// Mitsubishi GX Works2 project: PLC(原)   PLC: L06

// task 1# (event TRUE, interval 0, priority 31): 
// task 10# (event TRUE, interval 0, priority 31): 
// task 工位6（点胶A面） (event TRUE, interval 0, priority 31): 
// task 工位7（点胶B面） (event TRUE, interval 0, priority 31): 
// task 工位8 (event TRUE, interval 0, priority 31): 
// task 工位9（出料及载座升降） (event TRUE, interval 0, priority 31): 
// task 工站5（排不良） (event TRUE, interval 0, priority 31): 工站5（降载座）
// task 手动 (event TRUE, interval 0, priority 31): 手动
// task 报警 (event TRUE, interval 0, priority 31): 报警
// task 输出1 (event TRUE, interval 0, priority 31): 输出1
// task 降载座工位 (event TRUE, interval 0, priority 31): 降载座工位
// task 马达初始化 (event TRUE, interval 0, priority 31): 
// task 5# (event TRUE, interval 0, priority 31): 
// task 工站2（AOI测试） (event TRUE, interval 0, priority 31): 工站2
// task 工站3（开短路测试） (event TRUE, interval 0, priority 31): 工站3
// task 工站4（开短路测试） (event TRUE, interval 0, priority 31): 工站4
// task 测试程序 (event TRUE, interval 0, priority 31): 
// task 4# (event TRUE, interval 0, priority 31): 
// task 1#1 (event TRUE, interval 0, priority 31): 1#
// task 2# (event TRUE, interval 0, priority 31): 2#
// task 3# (event TRUE, interval 0, priority 31): 3#
// task 4#1 (event TRUE, interval 0, priority 31): 4#
// task 5#1 (event TRUE, interval 0, priority 31): 5#
// task 6# (event TRUE, interval 0, priority 31): 
// task 6#1 (event TRUE, interval 0, priority 31): 6#
// task 7#1 (event TRUE, interval 0, priority 31): 7#
// task 8#1 (event TRUE, interval 0, priority 31): 8#
// task 9#1 (event TRUE, interval 0, priority 31): 9#
// task 10#1 (event TRUE, interval 0, priority 31): 10#
// task 11# (event TRUE, interval 0, priority 31): 11#
// task 12# (event TRUE, interval 0, priority 31): 12#
// task 马达初始化1 (event TRUE, interval 0, priority 31): 马达初始化
// task 工位10 (event TRUE, interval 0, priority 31): 工位1
// task 7# (event TRUE, interval 0, priority 31): 
// task 8# (event TRUE, interval 0, priority 31): 
// task 9# (event TRUE, interval 0, priority 31): 
// task 初始化及工位控制 (event TRUE, interval 0, priority 31): 初始化及工位控制
// task 升载座 (event TRUE, interval 0, priority 31): 升载座
// task 工位1 (event TRUE, interval 0, priority 31): 

PROGRAM 1#
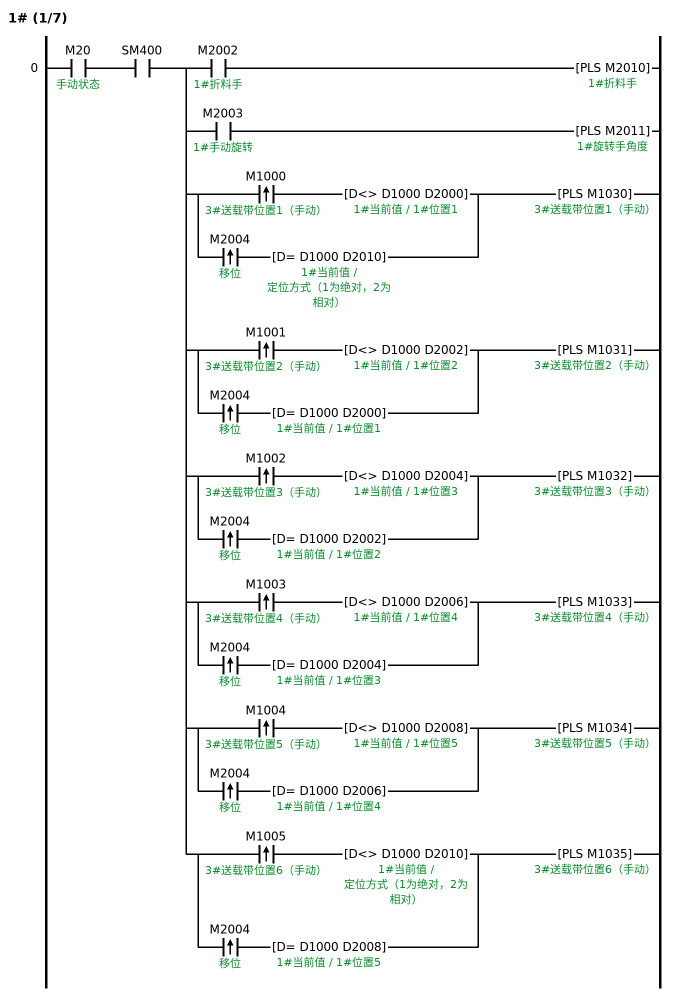
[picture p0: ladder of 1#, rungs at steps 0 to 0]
0     LD      M20  ; 手动状态
      AND     SM400
      MPS
      AND     M2002  ; 1#折料手
      PLS     M2010  ; 1#折料手
      MRD
      AND     M2003  ; 1#手动旋转
      PLS     M2011  ; 1#旋转手角度
      MRD
      LDP     M1000  ; 3#送载带位置1（手动）
      ANDD<>  D1000 D2000  ; 1#当前值 / 1#位置1
      LDP     M2004  ; 移位
      ANDD=   D1000 D2010  ; 1#当前值 / 定位方式（1为绝对，2为相对）
      ORB
      ANB
      PLS     M1030  ; 3#送载带位置1（手动）
      MRD
      LDP     M1001  ; 3#送载带位置2（手动）
      ANDD<>  D1000 D2002  ; 1#当前值 / 1#位置2
      LDP     M2004  ; 移位
      ANDD=   D1000 D2000  ; 1#当前值 / 1#位置1
      ORB
      ANB
      PLS     M1031  ; 3#送载带位置2（手动）
      MRD
      LDP     M1002  ; 3#送载带位置3（手动）
      ANDD<>  D1000 D2004  ; 1#当前值 / 1#位置3
      LDP     M2004  ; 移位
      ANDD=   D1000 D2002  ; 1#当前值 / 1#位置2
      ORB
      ANB
      PLS     M1032  ; 3#送载带位置3（手动）
      MRD
      LDP     M1003  ; 3#送载带位置4（手动）
      ANDD<>  D1000 D2006  ; 1#当前值 / 1#位置4
      LDP     M2004  ; 移位
      ANDD=   D1000 D2004  ; 1#当前值 / 1#位置3
      ORB
      ANB
      PLS     M1033  ; 3#送载带位置4（手动）
      MRD
      LDP     M1004  ; 3#送载带位置5（手动）
      ANDD<>  D1000 D2008  ; 1#当前值 / 1#位置5
      LDP     M2004  ; 移位
      ANDD=   D1000 D2006  ; 1#当前值 / 1#位置4
      ORB
      ANB
      PLS     M1034  ; 3#送载带位置5（手动）
      MPP
      LDP     M1005  ; 3#送载带位置6（手动）
      ANDD<>  D1000 D2010  ; 1#当前值 / 定位方式（1为绝对，2为相对）
      LDP     M2004  ; 移位
      ANDD=   D1000 D2008  ; 1#当前值 / 1#位置5
      ORB
      ANB
      PLS     M1035  ; 3#送载带位置6（手动）
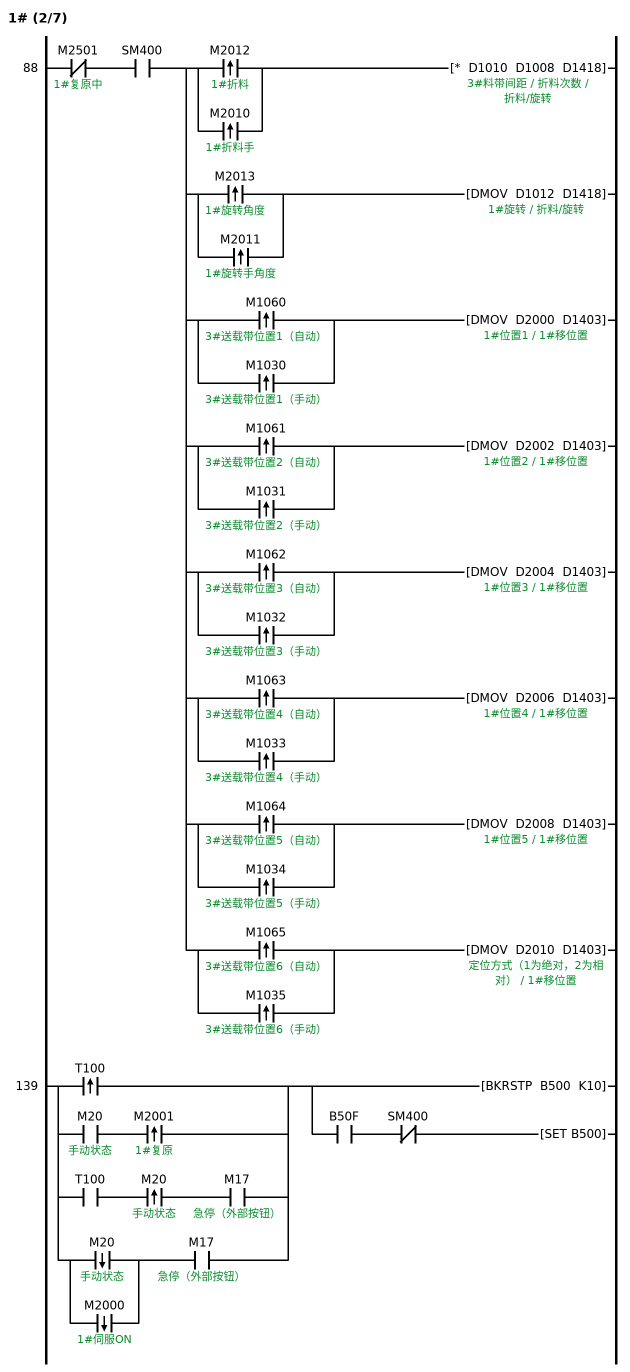
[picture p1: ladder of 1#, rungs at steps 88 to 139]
88    LDI     M2501  ; 1#复原中
      AND     SM400
      MPS
      LDP     M2012  ; 1#折料
      ORP     M2010  ; 1#折料手
      ANB
      *       D1010 D1008 D1418  ; 3#料带间距 / 折料次数 / 折料/旋转
      MRD
      LDP     M2013  ; 1#旋转角度
      ORP     M2011  ; 1#旋转手角度
      ANB
      DMOV    D1012 D1418  ; 1#旋转
      MRD
      LDP     M1060  ; 3#送载带位置1（自动）
      ORP     M1030  ; 3#送载带位置1（手动）
      ANB
      DMOV    D2000 D1403  ; 1#移位置
      MRD
      LDP     M1061  ; 3#送载带位置2（自动）
      ORP     M1031  ; 3#送载带位置2（手动）
      ANB
      DMOV    D2002 D1403
      MRD
      LDP     M1062  ; 3#送载带位置3（自动）
      ORP     M1032  ; 3#送载带位置3（手动）
      ANB
      DMOV    D2004 D1403
      MRD
      LDP     M1063  ; 3#送载带位置4（自动）
      ORP     M1033  ; 3#送载带位置4（手动）
      ANB
      DMOV    D2006 D1403
      MRD
      LDP     M1064  ; 3#送载带位置5（自动）
      ORP     M1034  ; 3#送载带位置5（手动）
      ANB
      DMOV    D2008 D1403
      MPP
      LDP     M1065  ; 3#送载带位置6（自动）
      ORP     M1035  ; 3#送载带位置6（手动）
      ANB
      DMOV    D2010 D1403
139   LDP     T100
      LD      M20  ; 手动状态
      ANDP    M2001  ; 1#复原
      ORB
      LD      T100
      ANDP    M20  ; 手动状态
      AND     M17  ; 急停（外部按钮）
      ORB
      LDF     M20  ; 手动状态
      ORF     M2000  ; 1#伺服ON
      AND     M17  ; 急停（外部按钮）
      ORB
      BKRSTP  B500 K10
      AND     B50F
      ANI     SM400
      SET     B500
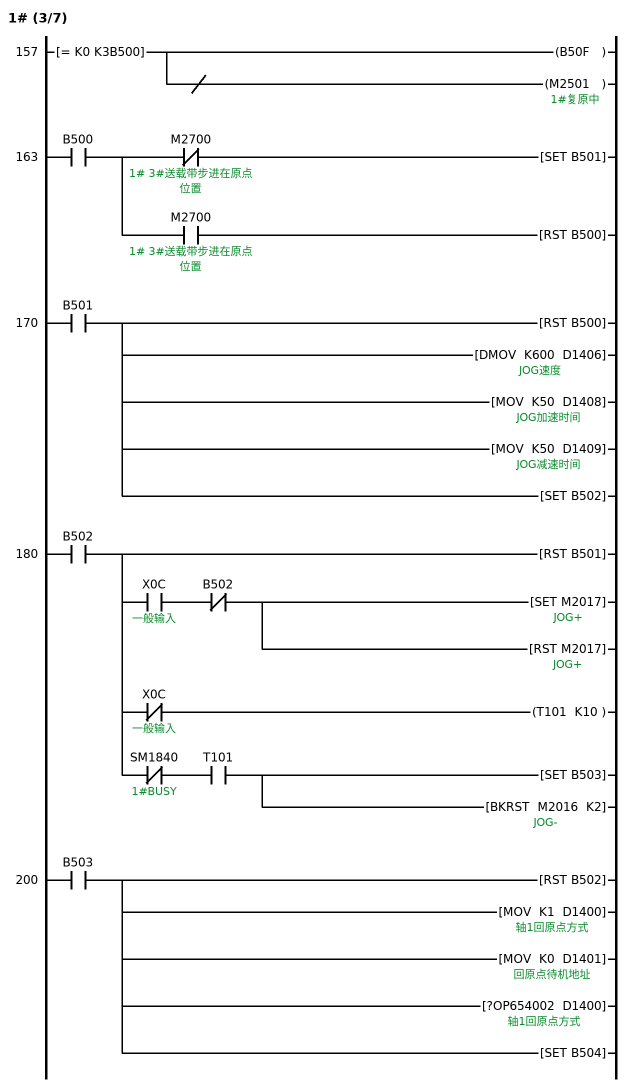
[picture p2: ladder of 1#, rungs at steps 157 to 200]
157   LD=     K0 K3B500
      OUT     B50F
      INV
      OUT     M2501  ; 1#复原中
163   LD      B500
      MPS
      ANI     M2700  ; 1# 3#送载带步进在原点位置
      SET     B501
      MPP
      AND     M2700  ; 1# 3#送载带步进在原点位置
      RST     B500
170   LD      B501
      RST     B500
      DMOV    K600 D1406  ; JOG速度
      MOV     K50 D1408  ; JOG加速时间
      MOV     K50 D1409  ; JOG减速时间
      SET     B502
180   LD      B502
      RST     B501
      MPS
      AND     X0C  ; 一般输入
      ANI     B502
      SET     M2017  ; JOG+
      RST     M2017  ; JOG+
      MRD
      ANI     X0C  ; 一般输入
      OUT     T101 K10
      MPP
      ANI     SM1840  ; 1#BUSY
      AND     T101
      SET     B503
      BKRST   M2016 K2  ; JOG-
200   LD      B503
      RST     B502
      MOV     K1 D1400  ; 轴1回原点方式
      MOV     K0 D1401  ; 回原点待机地址
      ?OP654002 D1400
      SET     B504
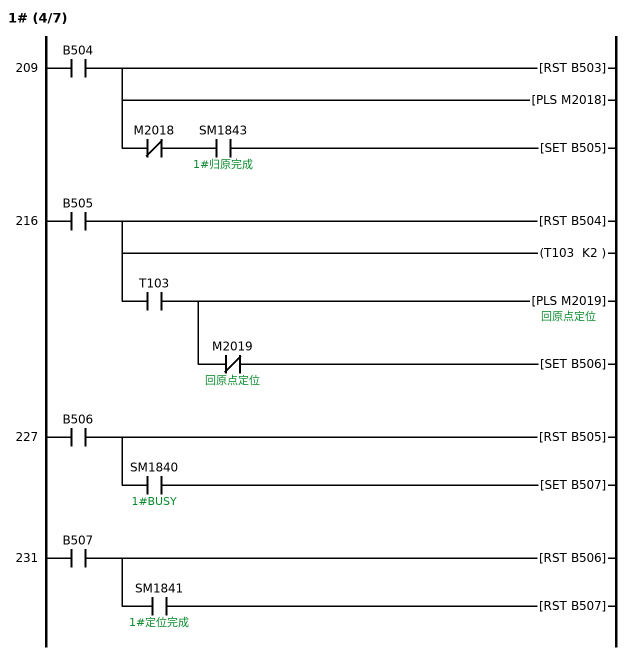
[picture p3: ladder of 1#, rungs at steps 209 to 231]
209   LD      B504
      RST     B503
      PLS     M2018
      ANI     M2018
      AND     SM1843  ; 1#归原完成
      SET     B505
216   LD      B505
      RST     B504
      OUT     T103 K2
      AND     T103
      PLS     M2019  ; 回原点定位
      ANI     M2019  ; 回原点定位
      SET     B506
227   LD      B506
      RST     B505
      AND     SM1840  ; 1#BUSY
      SET     B507
231   LD      B507
      RST     B506
      AND     SM1841  ; 1#定位完成
      RST     B507
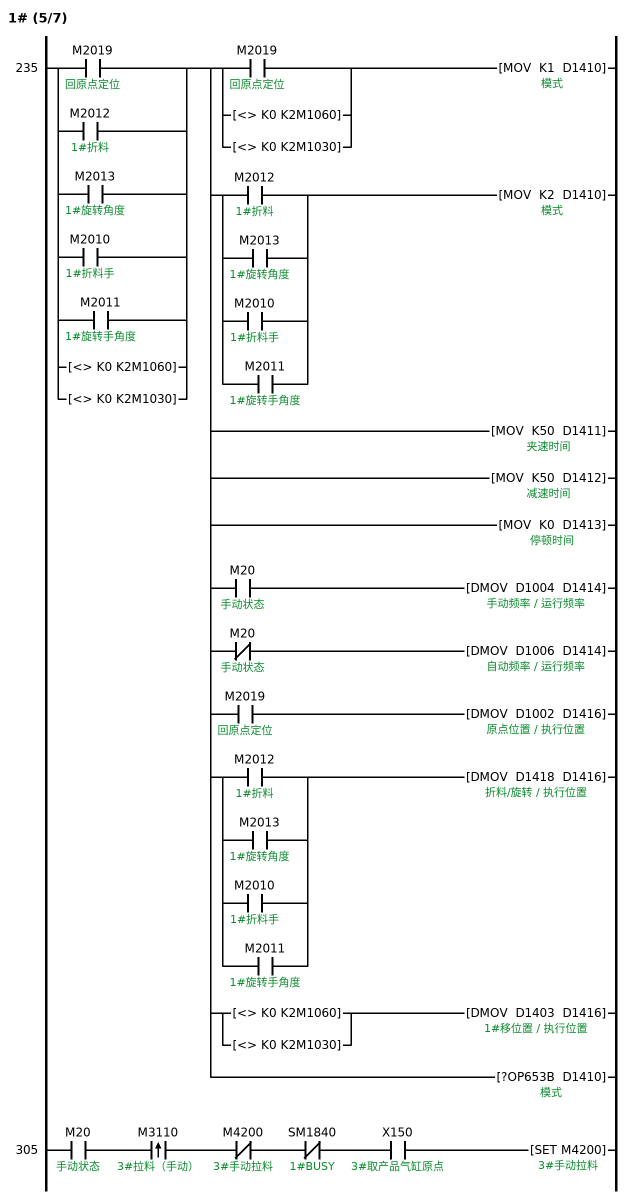
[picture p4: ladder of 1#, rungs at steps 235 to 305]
235   LD      M2019  ; 回原点定位
      OR      M2012  ; 1#折料
      OR      M2013  ; 1#旋转角度
      OR      M2010  ; 1#折料手
      OR      M2011  ; 1#旋转手角度
      OR<>    K0 K2M1060  ; 3#送载带位置1（自动）
      OR<>    K0 K2M1030  ; 3#送载带位置1（手动）
      MPS
      LD      M2019  ; 回原点定位
      OR<>    K0 K2M1060  ; 3#送载带位置1（自动）
      OR<>    K0 K2M1030  ; 3#送载带位置1（手动）
      ANB
      MOV     K1 D1410  ; 模式
      MRD
      LD      M2012  ; 1#折料
      OR      M2013  ; 1#旋转角度
      OR      M2010  ; 1#折料手
      OR      M2011  ; 1#旋转手角度
      ANB
      MOV     K2 D1410
      MPP
      MOV     K50 D1411  ; 夹速时间
      MOV     K50 D1412  ; 减速时间
      MOV     K0 D1413  ; 停顿时间
      MPS
      AND     M20  ; 手动状态
      DMOV    D1004 D1414  ; 手动频率 / 运行频率
      MRD
      ANI     M20  ; 手动状态
      DMOV    D1006 D1414  ; 自动频率
      MRD
      AND     M2019  ; 回原点定位
      DMOV    D1002 D1416  ; 原点位置 / 执行位置
      MRD
      LD      M2012  ; 1#折料
      OR      M2013  ; 1#旋转角度
      OR      M2010  ; 1#折料手
      OR      M2011  ; 1#旋转手角度
      ANB
      DMOV    D1418 D1416
      MRD
      LD<>    K0 K2M1060  ; 3#送载带位置1（自动）
      OR<>    K0 K2M1030  ; 3#送载带位置1（手动）
      ANB
      DMOV    D1403 D1416
      MPP
      ?OP653B D1410
305   LD      M20  ; 手动状态
      ANDP    M3110  ; 3#拉料（手动）
      ANI     M4200  ; 3#手动拉料
      ANI     SM1840  ; 1#BUSY
      AND     X150  ; 3#取产品气缸原点
      SET     M4200  ; 3#手动拉料
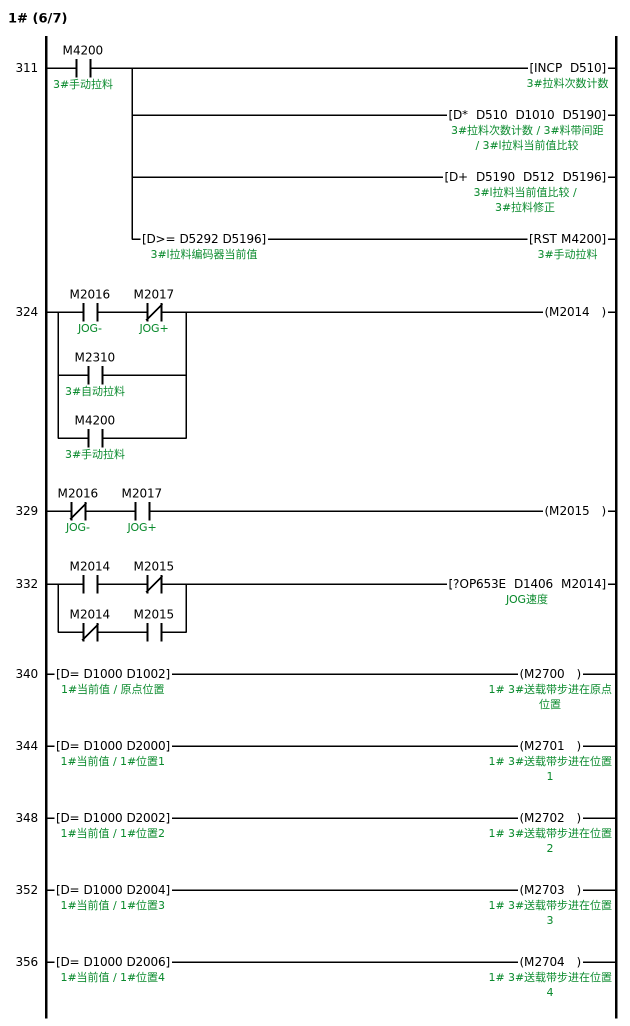
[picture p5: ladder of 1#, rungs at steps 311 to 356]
311   LD      M4200  ; 3#手动拉料
      INCP    D510  ; 3#拉料次数计数
      D*      D510 D1010 D5190  ; 3#l拉料当前值比较
      D+      D5190 D512 D5196  ; 3#拉料修正
      ANDD>=  D5292 D5196  ; 3#l拉料编码器当前值
      RST     M4200  ; 3#手动拉料
324   LD      M2016  ; JOG-
      ANI     M2017  ; JOG+
      OR      M2310  ; 3#自动拉料
      OR      M4200  ; 3#手动拉料
      OUT     M2014
329   LDI     M2016  ; JOG-
      AND     M2017  ; JOG+
      OUT     M2015
332   LD      M2014
      ANI     M2015
      LDI     M2014
      AND     M2015
      ORB
      ?OP653E D1406 M2014
340   LDD=    D1000 D1002  ; 1#当前值 / 原点位置
      OUT     M2700  ; 1# 3#送载带步进在原点位置
344   LDD=    D1000 D2000  ; 1#当前值 / 1#位置1
      OUT     M2701  ; 1# 3#送载带步进在位置1
348   LDD=    D1000 D2002  ; 1#当前值 / 1#位置2
      OUT     M2702  ; 1# 3#送载带步进在位置2
352   LDD=    D1000 D2004  ; 1#当前值 / 1#位置3
      OUT     M2703  ; 1# 3#送载带步进在位置3
356   LDD=    D1000 D2006  ; 1#当前值 / 1#位置4
      OUT     M2704  ; 1# 3#送载带步进在位置4
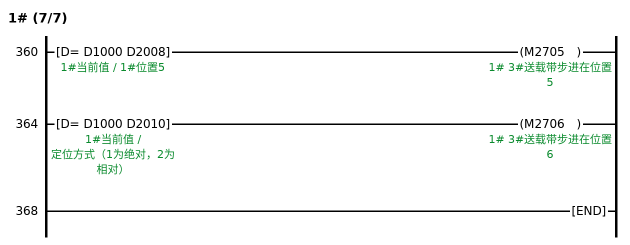
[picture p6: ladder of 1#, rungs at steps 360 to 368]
360   LDD=    D1000 D2008  ; 1#当前值 / 1#位置5
      OUT     M2705  ; 1# 3#送载带步进在位置5
364   LDD=    D1000 D2010  ; 1#当前值 / 定位方式（1为绝对，2为相对）
      OUT     M2706  ; 1# 3#送载带步进在位置6
368   END
END_PROGRAM

PROGRAM 10#
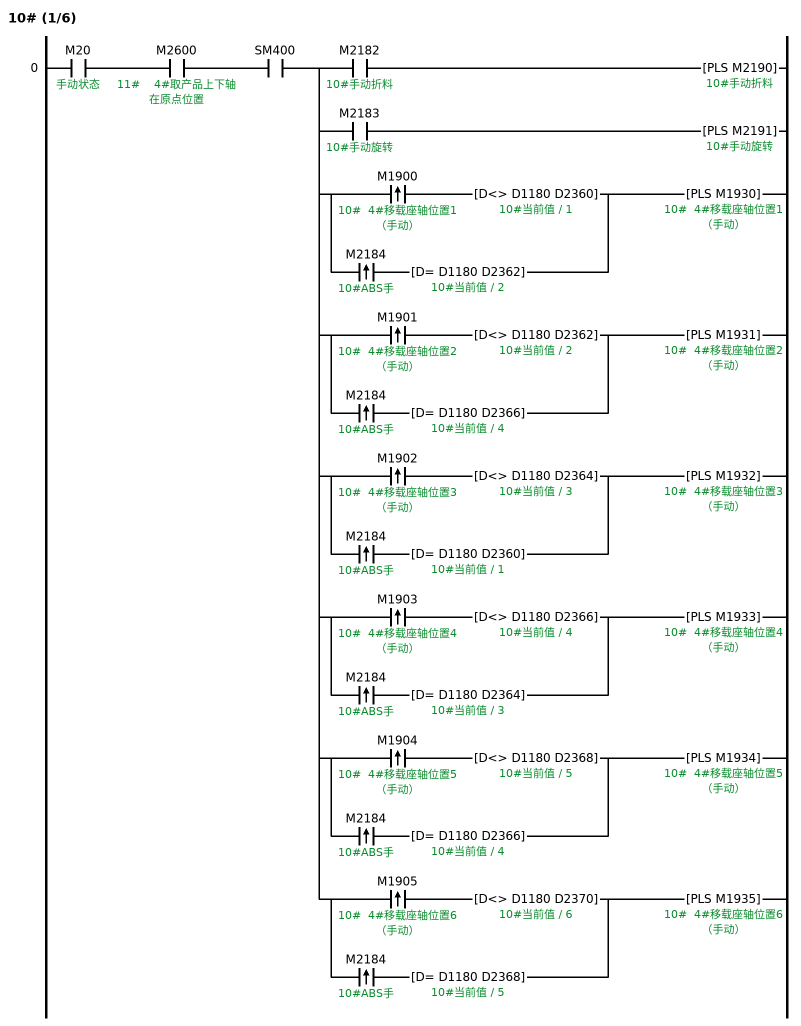
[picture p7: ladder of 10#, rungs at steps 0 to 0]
0     LD      M20  ; 手动状态
      AND     M2600  ; 11#    4#取产品上下轴在原点位置
      AND     SM400
      MPS
      AND     M2182  ; 10#手动折料
      PLS     M2190  ; 10#手动折料
      MRD
      AND     M2183  ; 10#手动旋转
      PLS     M2191  ; 10#手动旋转
      MRD
      LDP     M1900  ; 10#  4#移载座轴位置1（手动）
      ANDD<>  D1180 D2360  ; 10#当前值 / 1
      LDP     M2184  ; 10#ABS手
      ANDD=   D1180 D2362  ; 10#当前值 / 2
      ORB
      ANB
      PLS     M1930  ; 10#  4#移载座轴位置1（手动）
      MRD
      LDP     M1901  ; 10#  4#移载座轴位置2（手动）
      ANDD<>  D1180 D2362  ; 10#当前值 / 2
      LDP     M2184  ; 10#ABS手
      ANDD=   D1180 D2366  ; 10#当前值 / 4
      ORB
      ANB
      PLS     M1931  ; 10#  4#移载座轴位置2（手动）
      MRD
      LDP     M1902  ; 10#  4#移载座轴位置3（手动）
      ANDD<>  D1180 D2364  ; 10#当前值 / 3
      LDP     M2184  ; 10#ABS手
      ANDD=   D1180 D2360  ; 10#当前值 / 1
      ORB
      ANB
      PLS     M1932  ; 10#  4#移载座轴位置3（手动）
      MRD
      LDP     M1903  ; 10#  4#移载座轴位置4（手动）
      ANDD<>  D1180 D2366  ; 10#当前值 / 4
      LDP     M2184  ; 10#ABS手
      ANDD=   D1180 D2364  ; 10#当前值 / 3
      ORB
      ANB
      PLS     M1933  ; 10#  4#移载座轴位置4（手动）
      MRD
      LDP     M1904  ; 10#  4#移载座轴位置5（手动）
      ANDD<>  D1180 D2368  ; 10#当前值 / 5
      LDP     M2184  ; 10#ABS手
      ANDD=   D1180 D2366  ; 10#当前值 / 4
      ORB
      ANB
      PLS     M1934  ; 10#  4#移载座轴位置5（手动）
      MPP
      LDP     M1905  ; 10#  4#移载座轴位置6（手动）
      ANDD<>  D1180 D2370  ; 10#当前值 / 6
      LDP     M2184  ; 10#ABS手
      ANDD=   D1180 D2368  ; 10#当前值 / 5
      ORB
      ANB
      PLS     M1935  ; 10#  4#移载座轴位置6（手动）
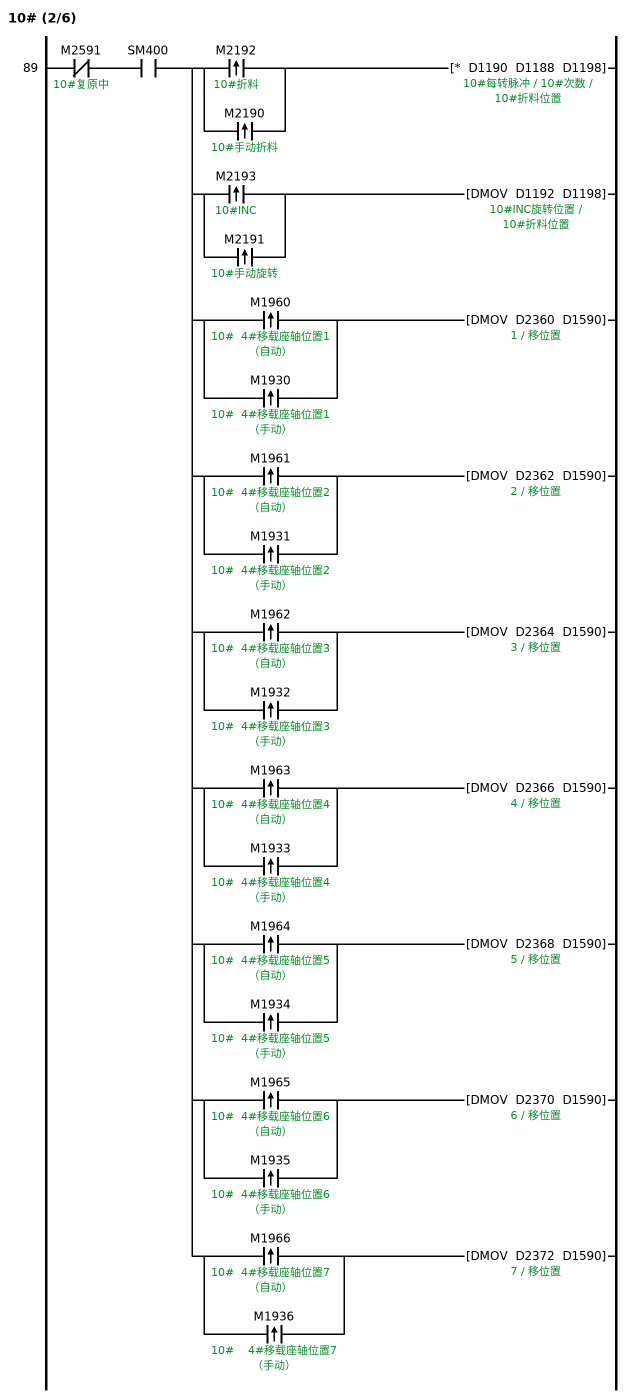
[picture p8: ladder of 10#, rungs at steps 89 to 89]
89    LDI     M2591  ; 10#复原中
      AND     SM400
      MPS
      LDP     M2192  ; 10#折料
      ORP     M2190  ; 10#手动折料
      ANB
      *       D1190 D1188 D1198  ; 10#每转脉冲 / 10#次数 / 10#折料位置
      MRD
      LDP     M2193  ; 10#INC
      ORP     M2191  ; 10#手动旋转
      ANB
      DMOV    D1192 D1198  ; 10#INC旋转位置
      MRD
      LDP     M1960  ; 10#  4#移载座轴位置1（自动）
      ORP     M1930  ; 10#  4#移载座轴位置1（手动）
      ANB
      DMOV    D2360 D1590  ; 移位置
      MRD
      LDP     M1961  ; 10#  4#移载座轴位置2（自动）
      ORP     M1931  ; 10#  4#移载座轴位置2（手动）
      ANB
      DMOV    D2362 D1590
      MRD
      LDP     M1962  ; 10#  4#移载座轴位置3（自动）
      ORP     M1932  ; 10#  4#移载座轴位置3（手动）
      ANB
      DMOV    D2364 D1590
      MRD
      LDP     M1963  ; 10#  4#移载座轴位置4（自动）
      ORP     M1933  ; 10#  4#移载座轴位置4（手动）
      ANB
      DMOV    D2366 D1590
      MRD
      LDP     M1964  ; 10#  4#移载座轴位置5（自动）
      ORP     M1934  ; 10#  4#移载座轴位置5（手动）
      ANB
      DMOV    D2368 D1590
      MRD
      LDP     M1965  ; 10#  4#移载座轴位置6（自动）
      ORP     M1935  ; 10#  4#移载座轴位置6（手动）
      ANB
      DMOV    D2370 D1590
      MPP
      LDP     M1966  ; 10#  4#移载座轴位置7（自动）
      ORP     M1936  ; 10#    4#移载座轴位置7（手动）
      ANB
      DMOV    D2372 D1590  ; 7
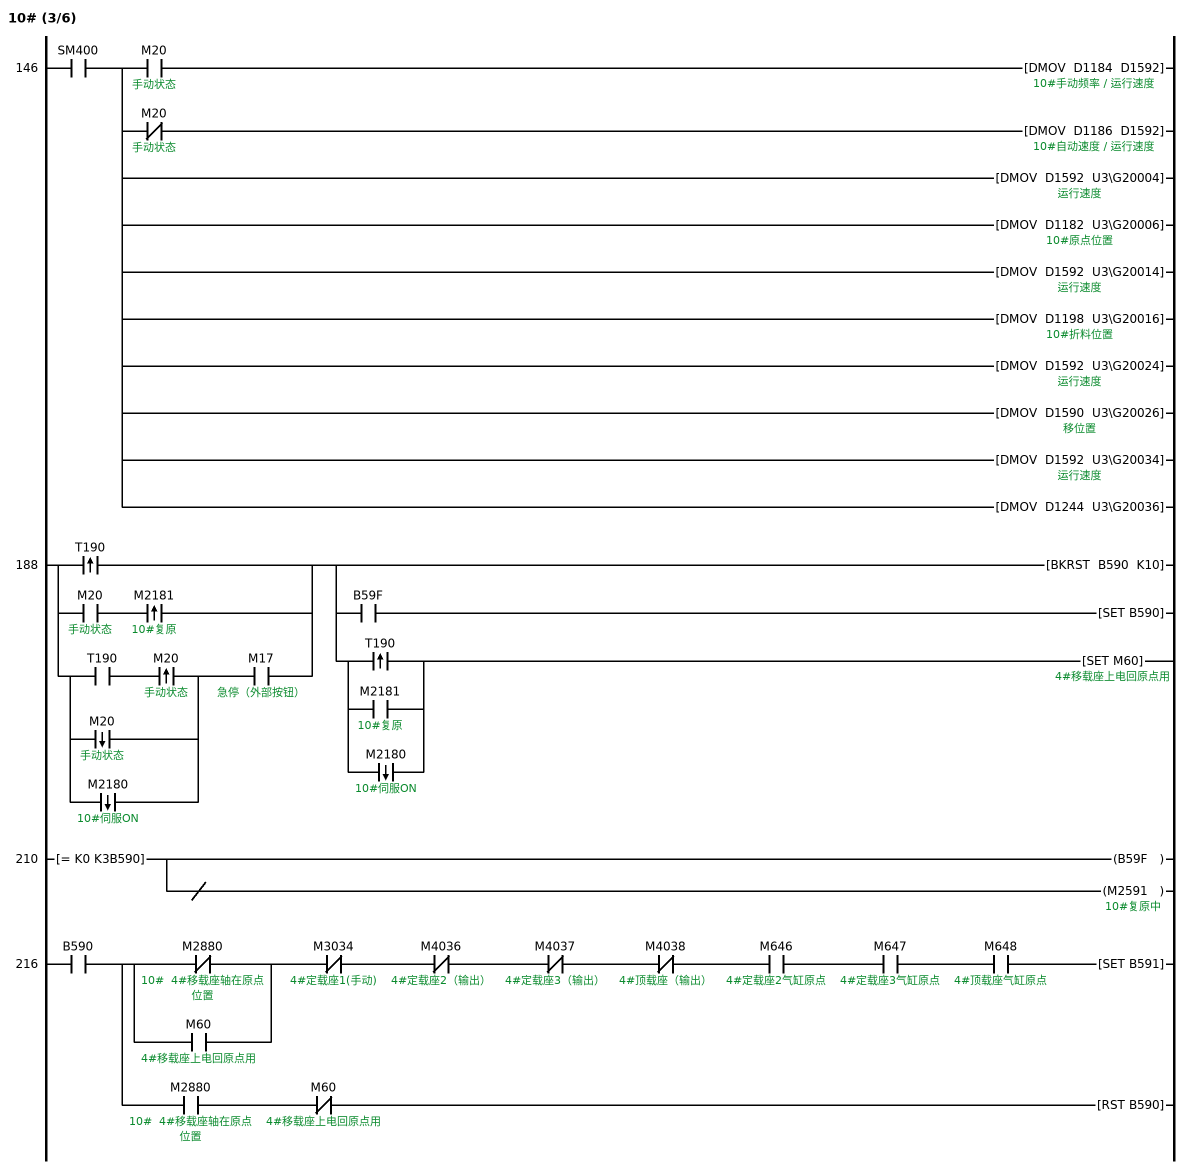
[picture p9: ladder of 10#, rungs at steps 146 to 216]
146   LD      SM400
      MPS
      AND     M20  ; 手动状态
      DMOV    D1184 D1592  ; 10#手动频率 / 运行速度
      MRD
      ANI     M20  ; 手动状态
      DMOV    D1186 D1592  ; 10#自动速度
      MPP
      DMOV    D1592 U3\G20004
      DMOV    D1182 U3\G20006  ; 10#原点位置
      DMOV    D1592 U3\G20014
      DMOV    D1198 U3\G20016
      DMOV    D1592 U3\G20024
      DMOV    D1590 U3\G20026
      DMOV    D1592 U3\G20034
      DMOV    D1244 U3\G20036
188   LDP     T190
      LD      M20  ; 手动状态
      ANDP    M2181  ; 10#复原
      ORB
      LD      T190
      ANDP    M20  ; 手动状态
      ORF     M20  ; 手动状态
      ORF     M2180  ; 10#伺服ON
      AND     M17  ; 急停（外部按钮）
      ORB
      BKRST   B590 K10
      MPS
      AND     B59F
      SET     B590
      MPP
      LDP     T190
      OR      M2181  ; 10#复原
      ORF     M2180  ; 10#伺服ON
      ANB
      SET     M60  ; 4#移载座上电回原点用
210   LD=     K0 K3B590
      OUT     B59F
      INV
      OUT     M2591  ; 10#复原中
216   LD      B590
      MPS
      LDI     M2880  ; 10#  4#移载座轴在原点位置
      OR      M60  ; 4#移载座上电回原点用
      ANB
      ANI     M3034  ; 4#定载座1(手动)
      ANI     M4036  ; 4#定载座2（输出）
      ANI     M4037  ; 4#定载座3（输出）
      ANI     M4038  ; 4#顶载座（输出）
      AND     M646  ; 4#定载座2气缸原点
      AND     M647  ; 4#定载座3气缸原点
      AND     M648  ; 4#顶载座气缸原点
      SET     B591
      MPP
      AND     M2880  ; 10#  4#移载座轴在原点位置
      ANI     M60  ; 4#移载座上电回原点用
      RST     B590
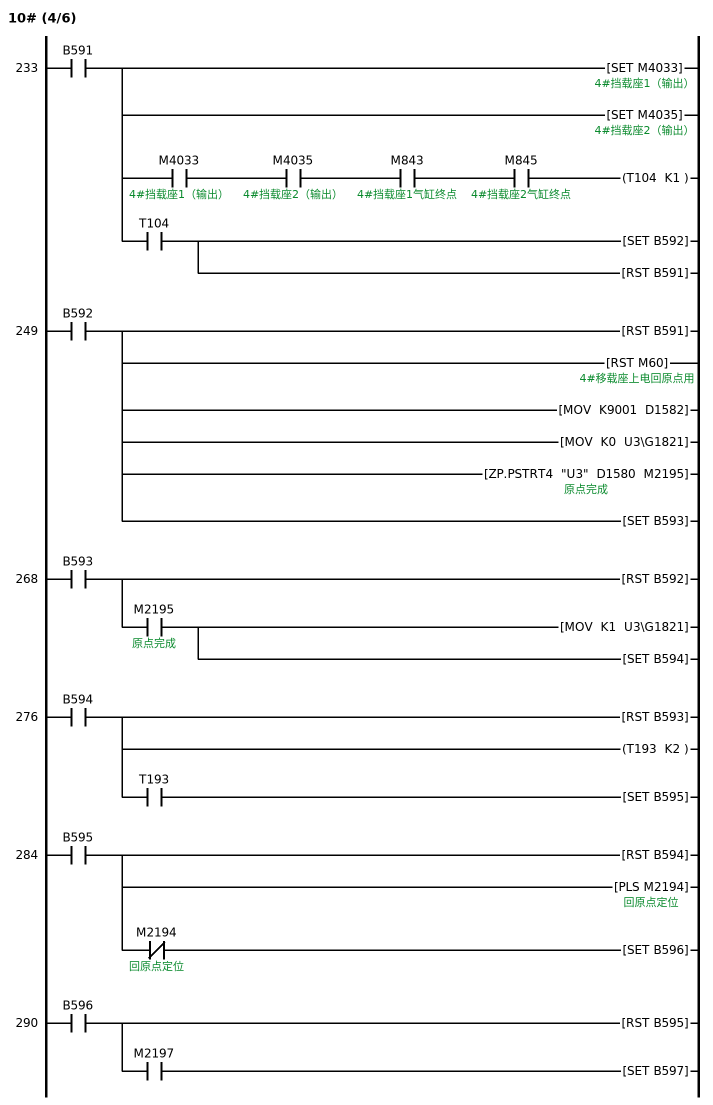
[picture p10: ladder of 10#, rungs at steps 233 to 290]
233   LD      B591
      SET     M4033  ; 4#挡载座1（输出）
      SET     M4035  ; 4#挡载座2（输出）
      MPS
      AND     M4033  ; 4#挡载座1（输出）
      AND     M4035  ; 4#挡载座2（输出）
      AND     M843  ; 4#挡载座1气缸终点
      AND     M845  ; 4#挡载座2气缸终点
      OUT     T104 K1
      MPP
      AND     T104
      SET     B592
      RST     B591
249   LD      B592
      RST     B591
      RST     M60  ; 4#移载座上电回原点用
      MOV     K9001 D1582
      MOV     K0 U3\G1821
      ZP.PSTRT4 "U3" D1580 M2195  ; 原点完成
      SET     B593
268   LD      B593
      RST     B592
      AND     M2195  ; 原点完成
      MOV     K1 U3\G1821
      SET     B594
276   LD      B594
      RST     B593
      OUT     T193 K2
      AND     T193
      SET     B595
284   LD      B595
      RST     B594
      PLS     M2194  ; 回原点定位
      ANI     M2194  ; 回原点定位
      SET     B596
290   LD      B596
      RST     B595
      AND     M2197
      SET     B597
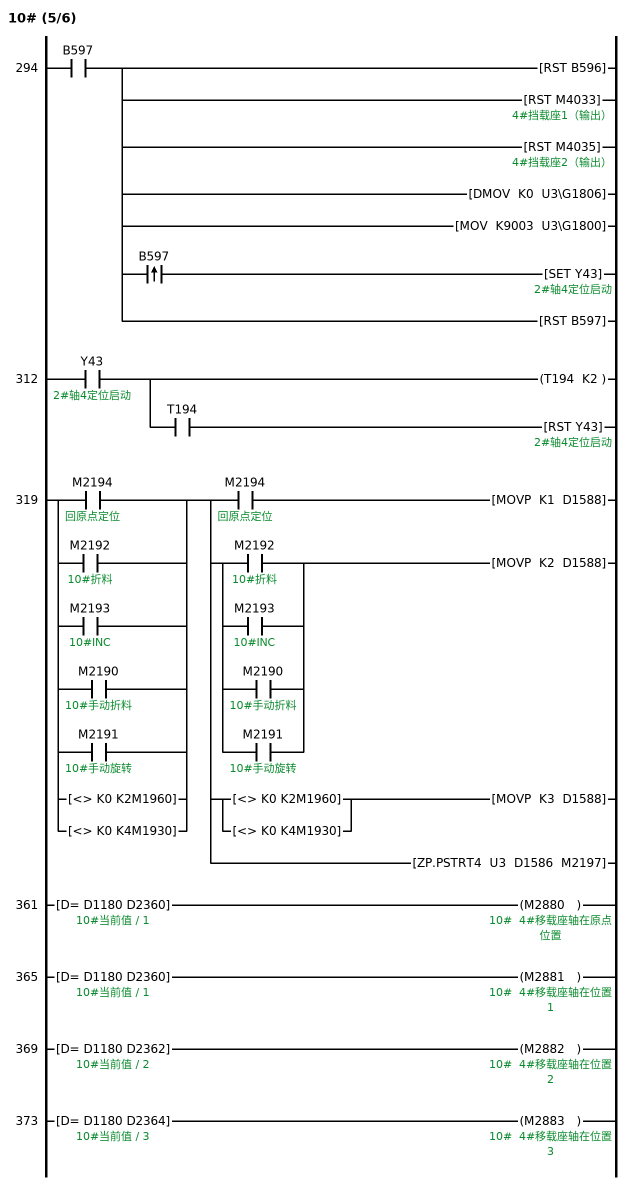
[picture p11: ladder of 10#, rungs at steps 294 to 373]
294   LD      B597
      RST     B596
      RST     M4033  ; 4#挡载座1（输出）
      RST     M4035  ; 4#挡载座2（输出）
      DMOV    K0 U3\G1806
      MOV     K9003 U3\G1800
      MPS
      ANDP    B597
      SET     Y43  ; 2#轴4定位启动
      MPP
      RST     B597
312   LD      Y43  ; 2#轴4定位启动
      OUT     T194 K2
      AND     T194
      RST     Y43  ; 2#轴4定位启动
319   LD      M2194  ; 回原点定位
      OR      M2192  ; 10#折料
      OR      M2193  ; 10#INC
      OR      M2190  ; 10#手动折料
      OR      M2191  ; 10#手动旋转
      OR<>    K0 K2M1960  ; 10#  4#移载座轴位置1（自动）
      OR<>    K0 K4M1930  ; 10#  4#移载座轴位置1（手动）
      MPS
      AND     M2194  ; 回原点定位
      MOVP    K1 D1588
      MRD
      LD      M2192  ; 10#折料
      OR      M2193  ; 10#INC
      OR      M2190  ; 10#手动折料
      OR      M2191  ; 10#手动旋转
      ANB
      MOVP    K2 D1588
      MRD
      LD<>    K0 K2M1960  ; 10#  4#移载座轴位置1（自动）
      OR<>    K0 K4M1930  ; 10#  4#移载座轴位置1（手动）
      ANB
      MOVP    K3 D1588
      MPP
      ZP.PSTRT4 U3 D1586 M2197
361   LDD=    D1180 D2360  ; 10#当前值 / 1
      OUT     M2880  ; 10#  4#移载座轴在原点位置
365   LDD=    D1180 D2360  ; 10#当前值 / 1
      OUT     M2881  ; 10#  4#移载座轴在位置1
369   LDD=    D1180 D2362  ; 10#当前值 / 2
      OUT     M2882  ; 10#  4#移载座轴在位置2
373   LDD=    D1180 D2364  ; 10#当前值 / 3
      OUT     M2883  ; 10#  4#移载座轴在位置3
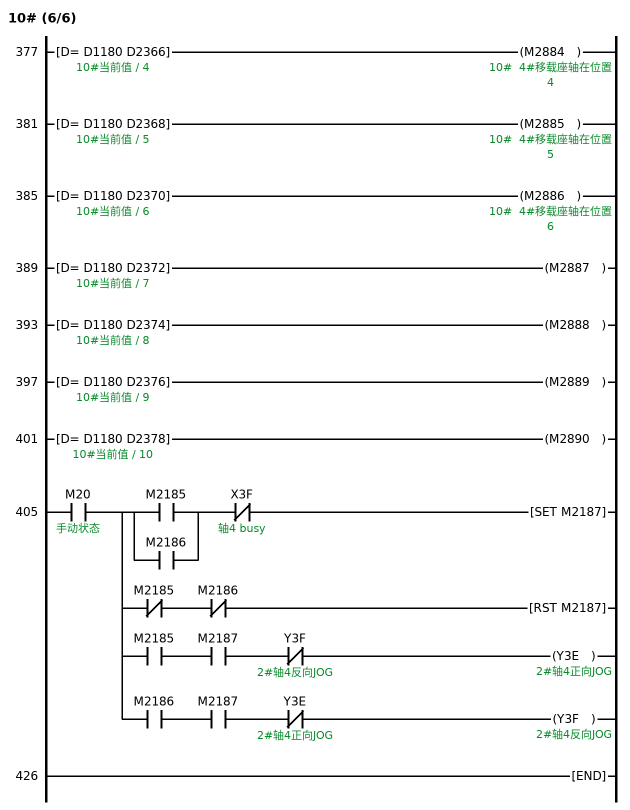
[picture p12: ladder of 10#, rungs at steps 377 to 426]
377   LDD=    D1180 D2366  ; 10#当前值 / 4
      OUT     M2884  ; 10#  4#移载座轴在位置4
381   LDD=    D1180 D2368  ; 10#当前值 / 5
      OUT     M2885  ; 10#  4#移载座轴在位置5
385   LDD=    D1180 D2370  ; 10#当前值 / 6
      OUT     M2886  ; 10#  4#移载座轴在位置6
389   LDD=    D1180 D2372  ; 10#当前值 / 7
      OUT     M2887
393   LDD=    D1180 D2374  ; 10#当前值 / 8
      OUT     M2888
397   LDD=    D1180 D2376  ; 10#当前值 / 9
      OUT     M2889
401   LDD=    D1180 D2378  ; 10#当前值 / 10
      OUT     M2890
405   LD      M20  ; 手动状态
      MPS
      LD      M2185
      OR      M2186
      ANB
      ANI     X3F  ; 轴4 busy
      SET     M2187
      MRD
      ANI     M2185
      ANI     M2186
      RST     M2187
      MRD
      AND     M2185
      AND     M2187
      ANI     Y3F  ; 2#轴4反向JOG
      OUT     Y3E  ; 2#轴4正向JOG
      MPP
      AND     M2186
      AND     M2187
      ANI     Y3E  ; 2#轴4正向JOG
      OUT     Y3F  ; 2#轴4反向JOG
426   END
END_PROGRAM

PROGRAM 11#
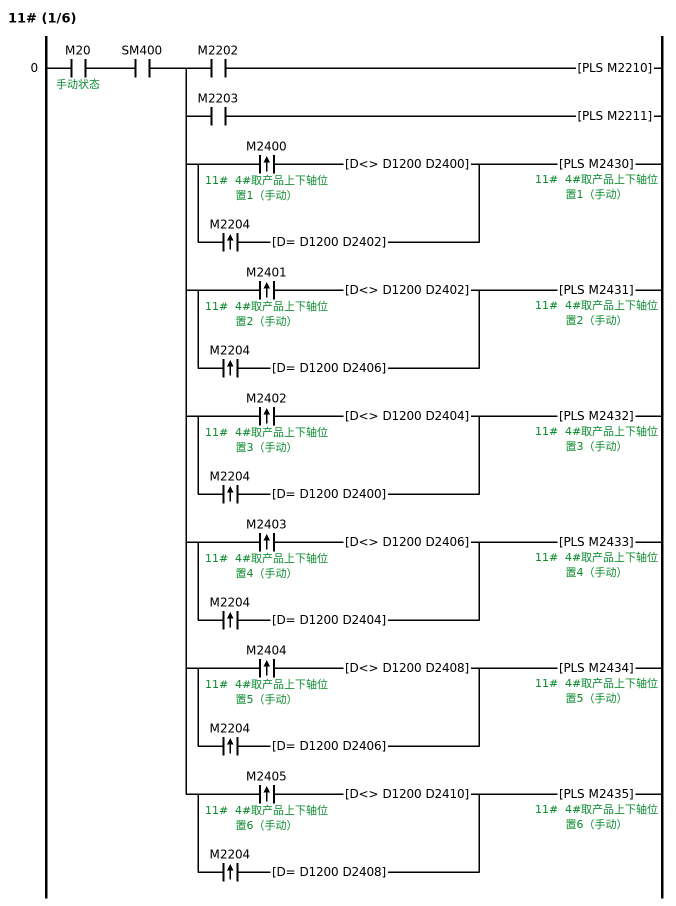
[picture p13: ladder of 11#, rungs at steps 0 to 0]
0     LD      M20  ; 手动状态
      AND     SM400
      MPS
      AND     M2202
      PLS     M2210
      MRD
      AND     M2203
      PLS     M2211
      MRD
      LDP     M2400  ; 11#  4#取产品上下轴位置1（手动）
      ANDD<>  D1200 D2400
      LDP     M2204
      ANDD=   D1200 D2402
      ORB
      ANB
      PLS     M2430  ; 11#  4#取产品上下轴位置1（手动）
      MRD
      LDP     M2401  ; 11#  4#取产品上下轴位置2（手动）
      ANDD<>  D1200 D2402
      LDP     M2204
      ANDD=   D1200 D2406
      ORB
      ANB
      PLS     M2431  ; 11#  4#取产品上下轴位置2（手动）
      MRD
      LDP     M2402  ; 11#  4#取产品上下轴位置3（手动）
      ANDD<>  D1200 D2404
      LDP     M2204
      ANDD=   D1200 D2400
      ORB
      ANB
      PLS     M2432  ; 11#  4#取产品上下轴位置3（手动）
      MRD
      LDP     M2403  ; 11#  4#取产品上下轴位置4（手动）
      ANDD<>  D1200 D2406
      LDP     M2204
      ANDD=   D1200 D2404
      ORB
      ANB
      PLS     M2433  ; 11#  4#取产品上下轴位置4（手动）
      MRD
      LDP     M2404  ; 11#  4#取产品上下轴位置5（手动）
      ANDD<>  D1200 D2408
      LDP     M2204
      ANDD=   D1200 D2406
      ORB
      ANB
      PLS     M2434  ; 11#  4#取产品上下轴位置5（手动）
      MPP
      LDP     M2405  ; 11#  4#取产品上下轴位置6（手动）
      ANDD<>  D1200 D2410
      LDP     M2204
      ANDD=   D1200 D2408
      ORB
      ANB
      PLS     M2435  ; 11#  4#取产品上下轴位置6（手动）
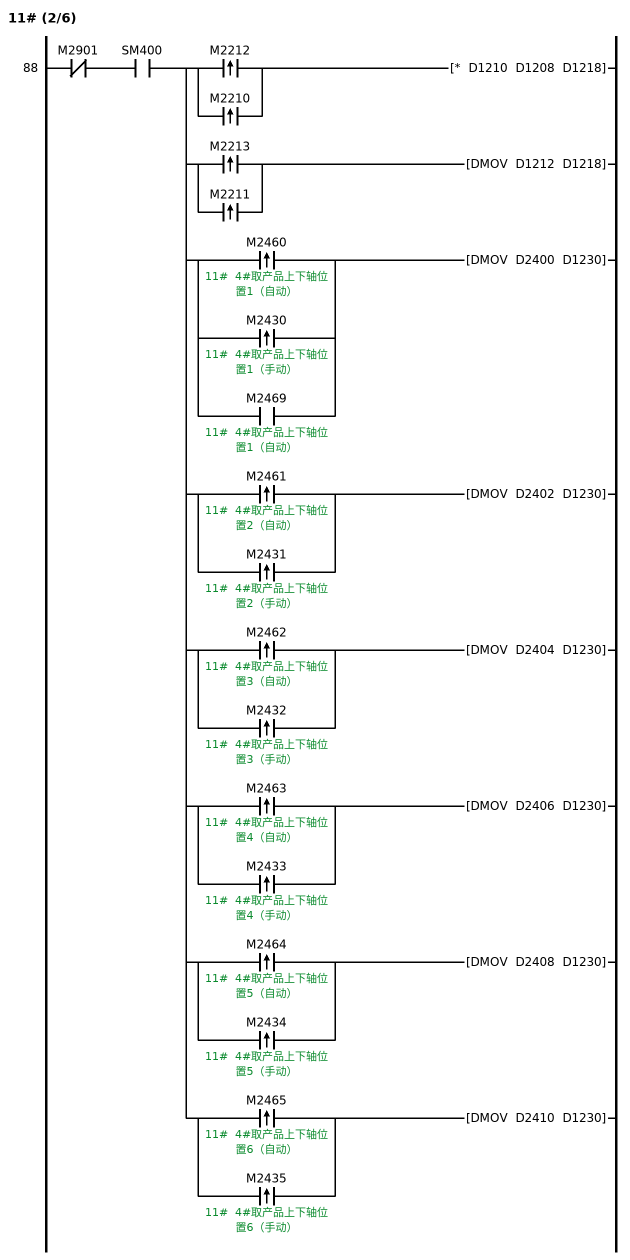
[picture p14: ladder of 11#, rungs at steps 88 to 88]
88    LDI     M2901
      AND     SM400
      MPS
      LDP     M2212
      ORP     M2210
      ANB
      *       D1210 D1208 D1218
      MRD
      LDP     M2213
      ORP     M2211
      ANB
      DMOV    D1212 D1218
      MRD
      LDP     M2460  ; 11#  4#取产品上下轴位置1（自动）
      ORP     M2430  ; 11#  4#取产品上下轴位置1（手动）
      OR      M2469  ; 11#  4#取产品上下轴位置1（自动）
      ANB
      DMOV    D2400 D1230
      MRD
      LDP     M2461  ; 11#  4#取产品上下轴位置2（自动）
      ORP     M2431  ; 11#  4#取产品上下轴位置2（手动）
      ANB
      DMOV    D2402 D1230
      MRD
      LDP     M2462  ; 11#  4#取产品上下轴位置3（自动）
      ORP     M2432  ; 11#  4#取产品上下轴位置3（手动）
      ANB
      DMOV    D2404 D1230
      MRD
      LDP     M2463  ; 11#  4#取产品上下轴位置4（自动）
      ORP     M2433  ; 11#  4#取产品上下轴位置4（手动）
      ANB
      DMOV    D2406 D1230
      MRD
      LDP     M2464  ; 11#  4#取产品上下轴位置5（自动）
      ORP     M2434  ; 11#  4#取产品上下轴位置5（手动）
      ANB
      DMOV    D2408 D1230
      MPP
      LDP     M2465  ; 11#  4#取产品上下轴位置6（自动）
      ORP     M2435  ; 11#  4#取产品上下轴位置6（手动）
      ANB
      DMOV    D2410 D1230
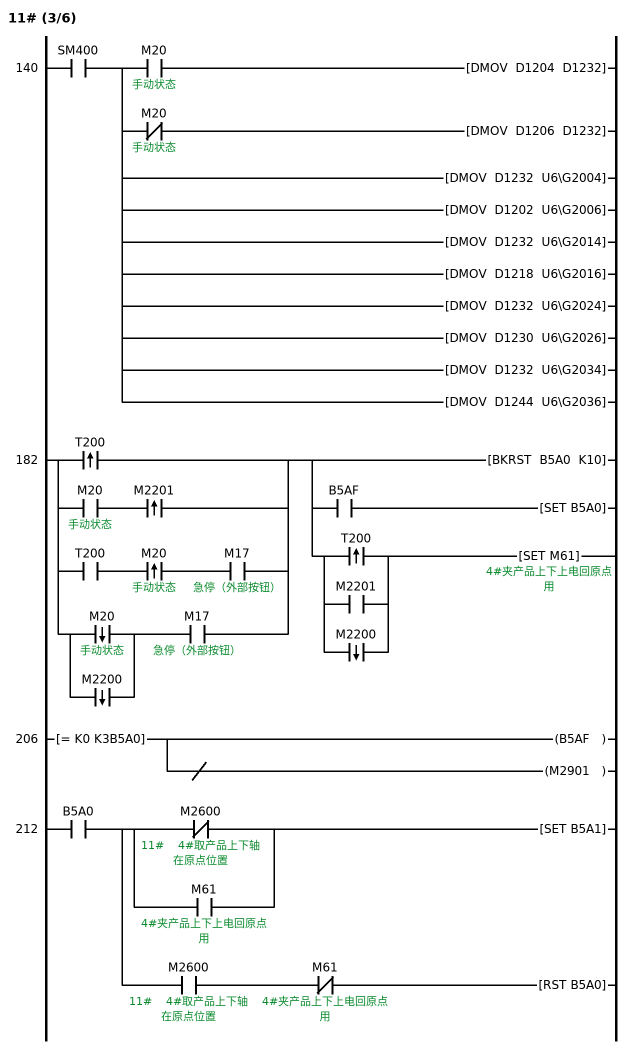
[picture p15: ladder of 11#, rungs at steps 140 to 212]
140   LD      SM400
      MPS
      AND     M20  ; 手动状态
      DMOV    D1204 D1232
      MRD
      ANI     M20  ; 手动状态
      DMOV    D1206 D1232
      MPP
      DMOV    D1232 U6\G2004
      DMOV    D1202 U6\G2006
      DMOV    D1232 U6\G2014
      DMOV    D1218 U6\G2016
      DMOV    D1232 U6\G2024
      DMOV    D1230 U6\G2026
      DMOV    D1232 U6\G2034
      DMOV    D1244 U6\G2036
182   LDP     T200
      LD      M20  ; 手动状态
      ANDP    M2201
      ORB
      LD      T200
      ANDP    M20  ; 手动状态
      AND     M17  ; 急停（外部按钮）
      ORB
      LDF     M20  ; 手动状态
      ORF     M2200
      AND     M17  ; 急停（外部按钮）
      ORB
      BKRST   B5A0 K10
      MPS
      AND     B5AF
      SET     B5A0
      MPP
      LDP     T200
      OR      M2201
      ORF     M2200
      ANB
      SET     M61  ; 4#夹产品上下上电回原点用
206   LD=     K0 K3B5A0
      OUT     B5AF
      INV
      OUT     M2901
212   LD      B5A0
      MPS
      LDI     M2600  ; 11#    4#取产品上下轴在原点位置
      OR      M61  ; 4#夹产品上下上电回原点用
      ANB
      SET     B5A1
      MPP
      AND     M2600  ; 11#    4#取产品上下轴在原点位置
      ANI     M61  ; 4#夹产品上下上电回原点用
      RST     B5A0
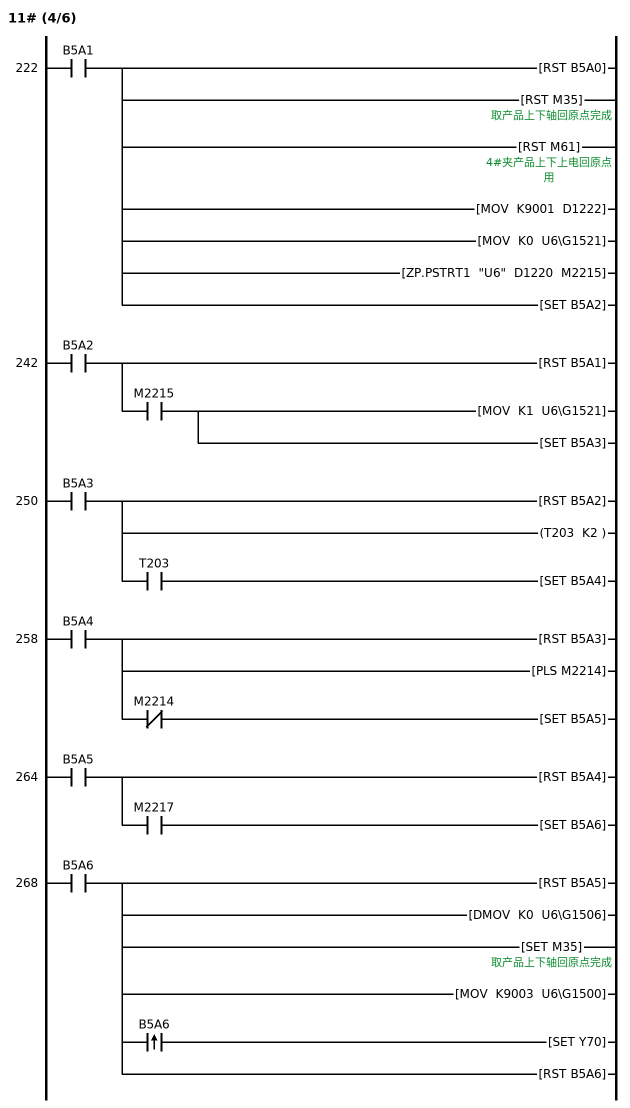
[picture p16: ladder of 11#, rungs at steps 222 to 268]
222   LD      B5A1
      RST     B5A0
      RST     M35  ; 取产品上下轴回原点完成
      RST     M61  ; 4#夹产品上下上电回原点用
      MOV     K9001 D1222
      MOV     K0 U6\G1521
      ZP.PSTRT1 "U6" D1220 M2215
      SET     B5A2
242   LD      B5A2
      RST     B5A1
      AND     M2215
      MOV     K1 U6\G1521
      SET     B5A3
250   LD      B5A3
      RST     B5A2
      OUT     T203 K2
      AND     T203
      SET     B5A4
258   LD      B5A4
      RST     B5A3
      PLS     M2214
      ANI     M2214
      SET     B5A5
264   LD      B5A5
      RST     B5A4
      AND     M2217
      SET     B5A6
268   LD      B5A6
      RST     B5A5
      DMOV    K0 U6\G1506
      SET     M35  ; 取产品上下轴回原点完成
      MOV     K9003 U6\G1500
      MPS
      ANDP    B5A6
      SET     Y70
      MPP
      RST     B5A6
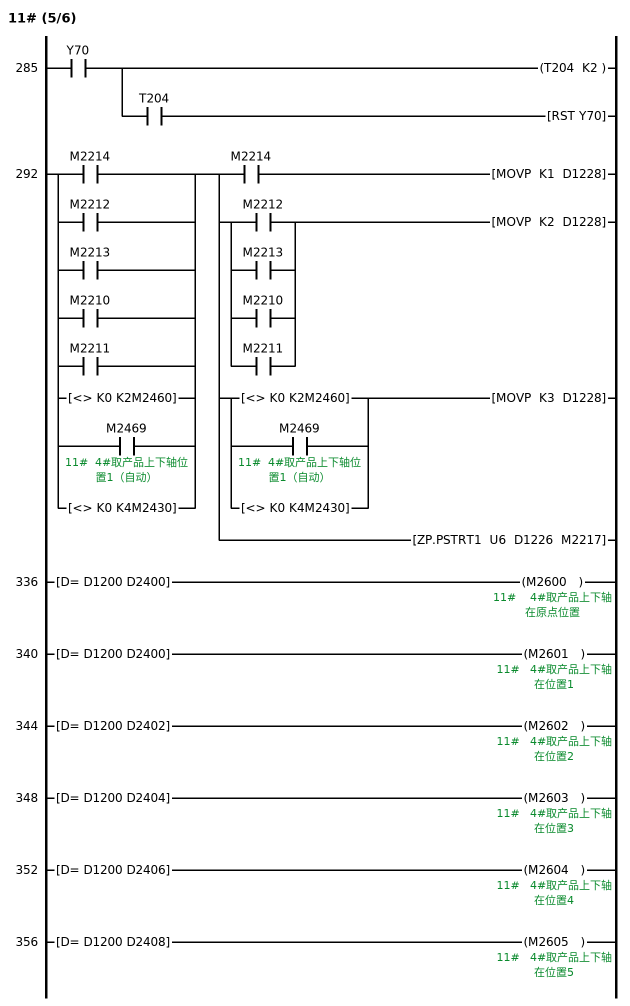
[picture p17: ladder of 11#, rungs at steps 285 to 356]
285   LD      Y70
      OUT     T204 K2
      AND     T204
      RST     Y70
292   LD      M2214
      OR      M2212
      OR      M2213
      OR      M2210
      OR      M2211
      OR<>    K0 K2M2460  ; 11#  4#取产品上下轴位置1（自动）
      OR      M2469  ; 11#  4#取产品上下轴位置1（自动）
      OR<>    K0 K4M2430  ; 11#  4#取产品上下轴位置1（手动）
      MPS
      AND     M2214
      MOVP    K1 D1228
      MRD
      LD      M2212
      OR      M2213
      OR      M2210
      OR      M2211
      ANB
      MOVP    K2 D1228
      MRD
      LD<>    K0 K2M2460  ; 11#  4#取产品上下轴位置1（自动）
      OR      M2469  ; 11#  4#取产品上下轴位置1（自动）
      OR<>    K0 K4M2430  ; 11#  4#取产品上下轴位置1（手动）
      ANB
      MOVP    K3 D1228
      MPP
      ZP.PSTRT1 U6 D1226 M2217
336   LDD=    D1200 D2400
      OUT     M2600  ; 11#    4#取产品上下轴在原点位置
340   LDD=    D1200 D2400
      OUT     M2601  ; 11#   4#取产品上下轴在位置1
344   LDD=    D1200 D2402
      OUT     M2602  ; 11#   4#取产品上下轴在位置2
348   LDD=    D1200 D2404
      OUT     M2603  ; 11#   4#取产品上下轴在位置3
352   LDD=    D1200 D2406
      OUT     M2604  ; 11#   4#取产品上下轴在位置4
356   LDD=    D1200 D2408
      OUT     M2605  ; 11#   4#取产品上下轴在位置5
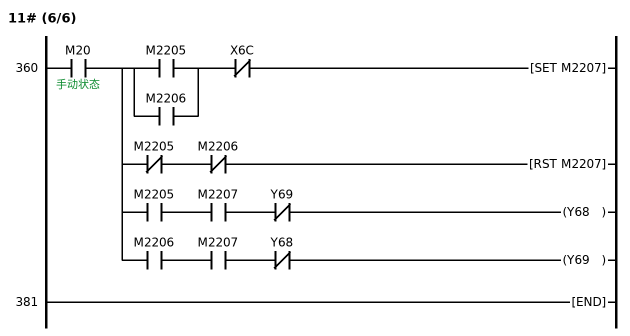
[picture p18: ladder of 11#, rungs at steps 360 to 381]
360   LD      M20  ; 手动状态
      MPS
      LD      M2205
      OR      M2206
      ANB
      ANI     X6C
      SET     M2207
      MRD
      ANI     M2205
      ANI     M2206
      RST     M2207
      MRD
      AND     M2205
      AND     M2207
      ANI     Y69
      OUT     Y68
      MPP
      AND     M2206
      AND     M2207
      ANI     Y68
      OUT     Y69
381   END
END_PROGRAM

PROGRAM 12#
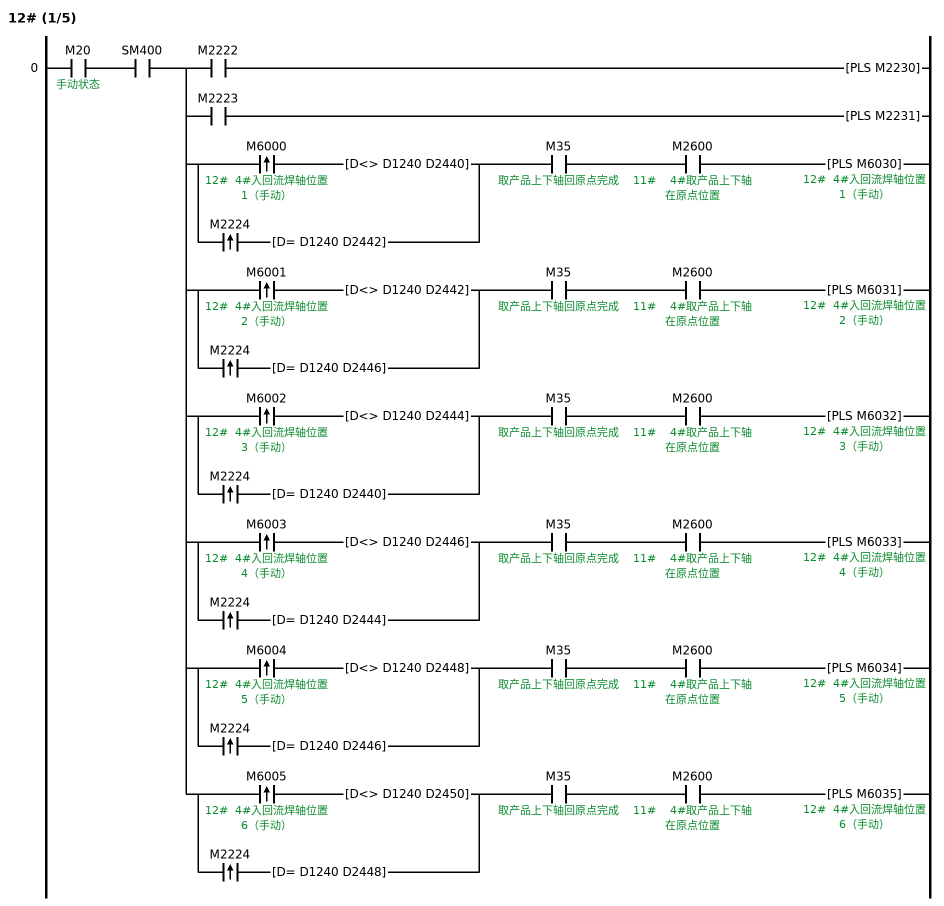
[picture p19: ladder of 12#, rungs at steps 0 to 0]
0     LD      M20  ; 手动状态
      AND     SM400
      MPS
      AND     M2222
      PLS     M2230
      MRD
      AND     M2223
      PLS     M2231
      MRD
      LDP     M6000  ; 12#  4#入回流焊轴位置1（手动）
      ANDD<>  D1240 D2440
      LDP     M2224
      ANDD=   D1240 D2442
      ORB
      ANB
      AND     M35  ; 取产品上下轴回原点完成
      AND     M2600  ; 11#    4#取产品上下轴在原点位置
      PLS     M6030  ; 12#  4#入回流焊轴位置1（手动）
      MRD
      LDP     M6001  ; 12#  4#入回流焊轴位置2（手动）
      ANDD<>  D1240 D2442
      LDP     M2224
      ANDD=   D1240 D2446
      ORB
      ANB
      AND     M35  ; 取产品上下轴回原点完成
      AND     M2600  ; 11#    4#取产品上下轴在原点位置
      PLS     M6031  ; 12#  4#入回流焊轴位置2（手动）
      MRD
      LDP     M6002  ; 12#  4#入回流焊轴位置3（手动）
      ANDD<>  D1240 D2444
      LDP     M2224
      ANDD=   D1240 D2440
      ORB
      ANB
      AND     M35  ; 取产品上下轴回原点完成
      AND     M2600  ; 11#    4#取产品上下轴在原点位置
      PLS     M6032  ; 12#  4#入回流焊轴位置3（手动）
      MRD
      LDP     M6003  ; 12#  4#入回流焊轴位置4（手动）
      ANDD<>  D1240 D2446
      LDP     M2224
      ANDD=   D1240 D2444
      ORB
      ANB
      AND     M35  ; 取产品上下轴回原点完成
      AND     M2600  ; 11#    4#取产品上下轴在原点位置
      PLS     M6033  ; 12#  4#入回流焊轴位置4（手动）
      MRD
      LDP     M6004  ; 12#  4#入回流焊轴位置5（手动）
      ANDD<>  D1240 D2448
      LDP     M2224
      ANDD=   D1240 D2446
      ORB
      ANB
      AND     M35  ; 取产品上下轴回原点完成
      AND     M2600  ; 11#    4#取产品上下轴在原点位置
      PLS     M6034  ; 12#  4#入回流焊轴位置5（手动）
      MPP
      LDP     M6005  ; 12#  4#入回流焊轴位置6（手动）
      ANDD<>  D1240 D2450
      LDP     M2224
      ANDD=   D1240 D2448
      ORB
      ANB
      AND     M35  ; 取产品上下轴回原点完成
      AND     M2600  ; 11#    4#取产品上下轴在原点位置
      PLS     M6035  ; 12#  4#入回流焊轴位置6（手动）
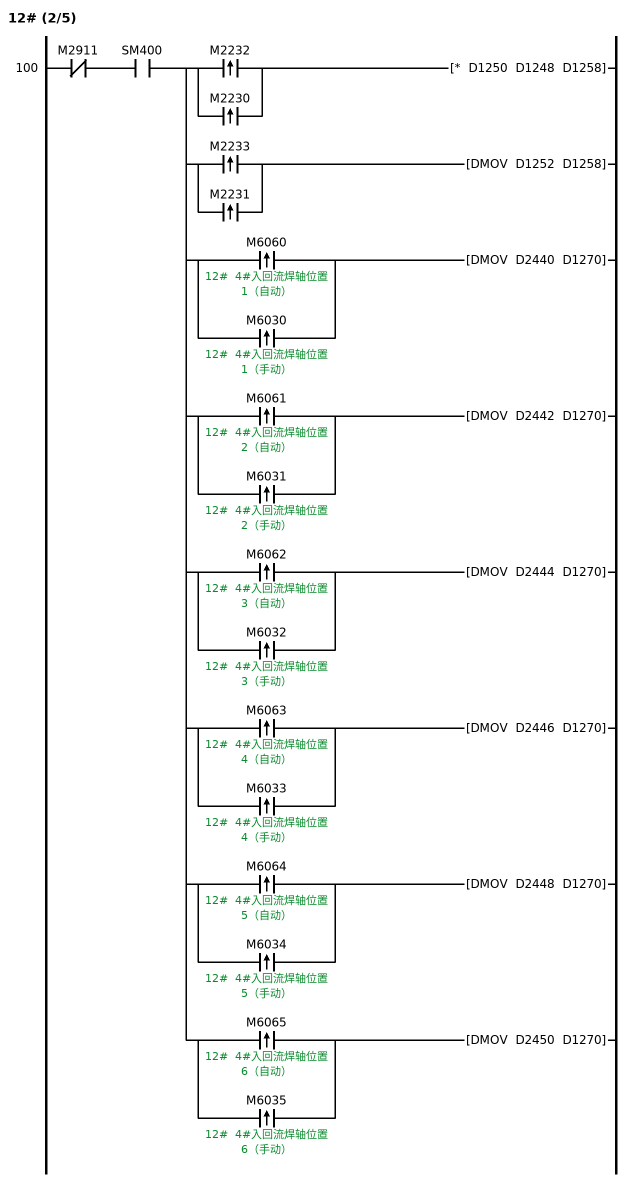
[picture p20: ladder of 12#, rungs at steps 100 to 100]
100   LDI     M2911
      AND     SM400
      MPS
      LDP     M2232
      ORP     M2230
      ANB
      *       D1250 D1248 D1258
      MRD
      LDP     M2233
      ORP     M2231
      ANB
      DMOV    D1252 D1258
      MRD
      LDP     M6060  ; 12#  4#入回流焊轴位置1（自动）
      ORP     M6030  ; 12#  4#入回流焊轴位置1（手动）
      ANB
      DMOV    D2440 D1270
      MRD
      LDP     M6061  ; 12#  4#入回流焊轴位置2（自动）
      ORP     M6031  ; 12#  4#入回流焊轴位置2（手动）
      ANB
      DMOV    D2442 D1270
      MRD
      LDP     M6062  ; 12#  4#入回流焊轴位置3（自动）
      ORP     M6032  ; 12#  4#入回流焊轴位置3（手动）
      ANB
      DMOV    D2444 D1270
      MRD
      LDP     M6063  ; 12#  4#入回流焊轴位置4（自动）
      ORP     M6033  ; 12#  4#入回流焊轴位置4（手动）
      ANB
      DMOV    D2446 D1270
      MRD
      LDP     M6064  ; 12#  4#入回流焊轴位置5（自动）
      ORP     M6034  ; 12#  4#入回流焊轴位置5（手动）
      ANB
      DMOV    D2448 D1270
      MPP
      LDP     M6065  ; 12#  4#入回流焊轴位置6（自动）
      ORP     M6035  ; 12#  4#入回流焊轴位置6（手动）
      ANB
      DMOV    D2450 D1270
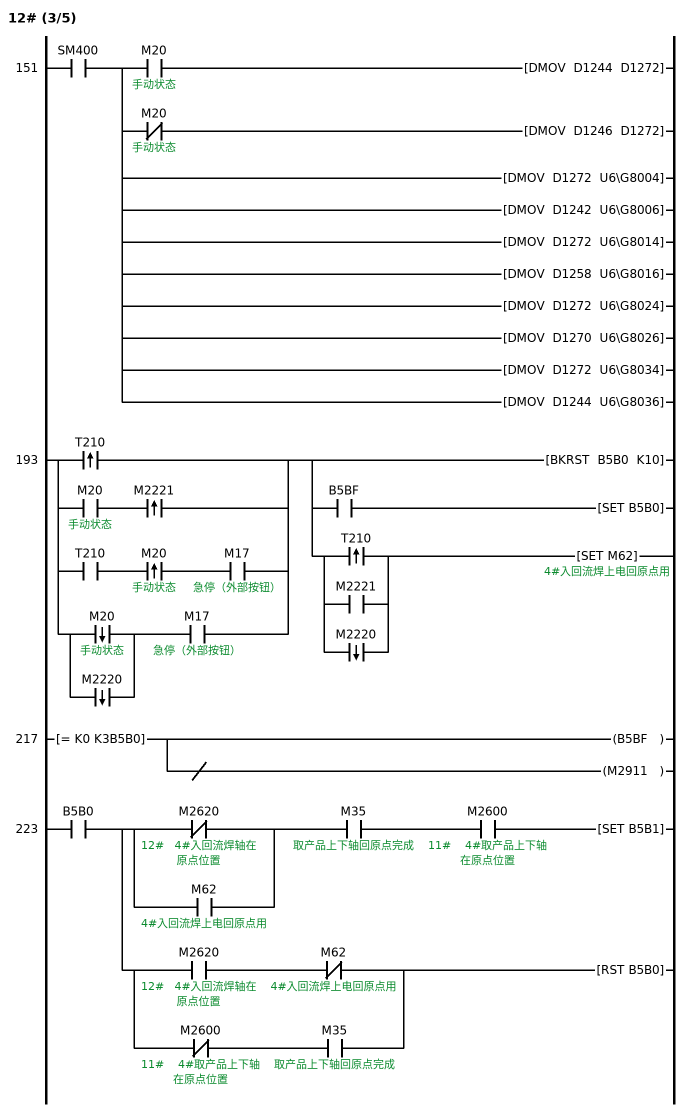
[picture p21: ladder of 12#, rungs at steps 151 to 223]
151   LD      SM400
      MPS
      AND     M20  ; 手动状态
      DMOV    D1244 D1272
      MRD
      ANI     M20  ; 手动状态
      DMOV    D1246 D1272
      MPP
      DMOV    D1272 U6\G8004
      DMOV    D1242 U6\G8006
      DMOV    D1272 U6\G8014
      DMOV    D1258 U6\G8016
      DMOV    D1272 U6\G8024
      DMOV    D1270 U6\G8026
      DMOV    D1272 U6\G8034
      DMOV    D1244 U6\G8036
193   LDP     T210
      LD      M20  ; 手动状态
      ANDP    M2221
      ORB
      LD      T210
      ANDP    M20  ; 手动状态
      AND     M17  ; 急停（外部按钮）
      ORB
      LDF     M20  ; 手动状态
      ORF     M2220
      AND     M17  ; 急停（外部按钮）
      ORB
      BKRST   B5B0 K10
      MPS
      AND     B5BF
      SET     B5B0
      MPP
      LDP     T210
      OR      M2221
      ORF     M2220
      ANB
      SET     M62  ; 4#入回流焊上电回原点用
217   LD=     K0 K3B5B0
      OUT     B5BF
      INV
      OUT     M2911
223   LD      B5B0
      MPS
      LDI     M2620  ; 12#   4#入回流焊轴在原点位置
      OR      M62  ; 4#入回流焊上电回原点用
      ANB
      AND     M35  ; 取产品上下轴回原点完成
      AND     M2600  ; 11#    4#取产品上下轴在原点位置
      SET     B5B1
      MPP
      LD      M2620  ; 12#   4#入回流焊轴在原点位置
      ANI     M62  ; 4#入回流焊上电回原点用
      LDI     M2600  ; 11#    4#取产品上下轴在原点位置
      AND     M35  ; 取产品上下轴回原点完成
      ORB
      ANB
      RST     B5B0
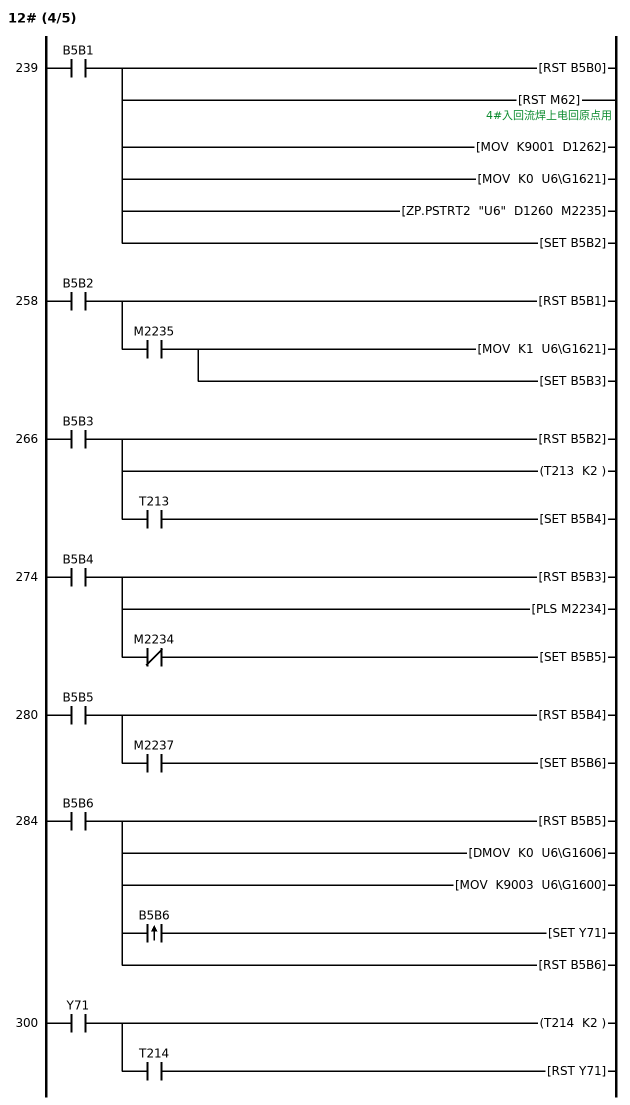
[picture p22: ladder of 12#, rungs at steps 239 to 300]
239   LD      B5B1
      RST     B5B0
      RST     M62  ; 4#入回流焊上电回原点用
      MOV     K9001 D1262
      MOV     K0 U6\G1621
      ZP.PSTRT2 "U6" D1260 M2235
      SET     B5B2
258   LD      B5B2
      RST     B5B1
      AND     M2235
      MOV     K1 U6\G1621
      SET     B5B3
266   LD      B5B3
      RST     B5B2
      OUT     T213 K2
      AND     T213
      SET     B5B4
274   LD      B5B4
      RST     B5B3
      PLS     M2234
      ANI     M2234
      SET     B5B5
280   LD      B5B5
      RST     B5B4
      AND     M2237
      SET     B5B6
284   LD      B5B6
      RST     B5B5
      DMOV    K0 U6\G1606
      MOV     K9003 U6\G1600
      MPS
      ANDP    B5B6
      SET     Y71
      MPP
      RST     B5B6
300   LD      Y71
      OUT     T214 K2
      AND     T214
      RST     Y71
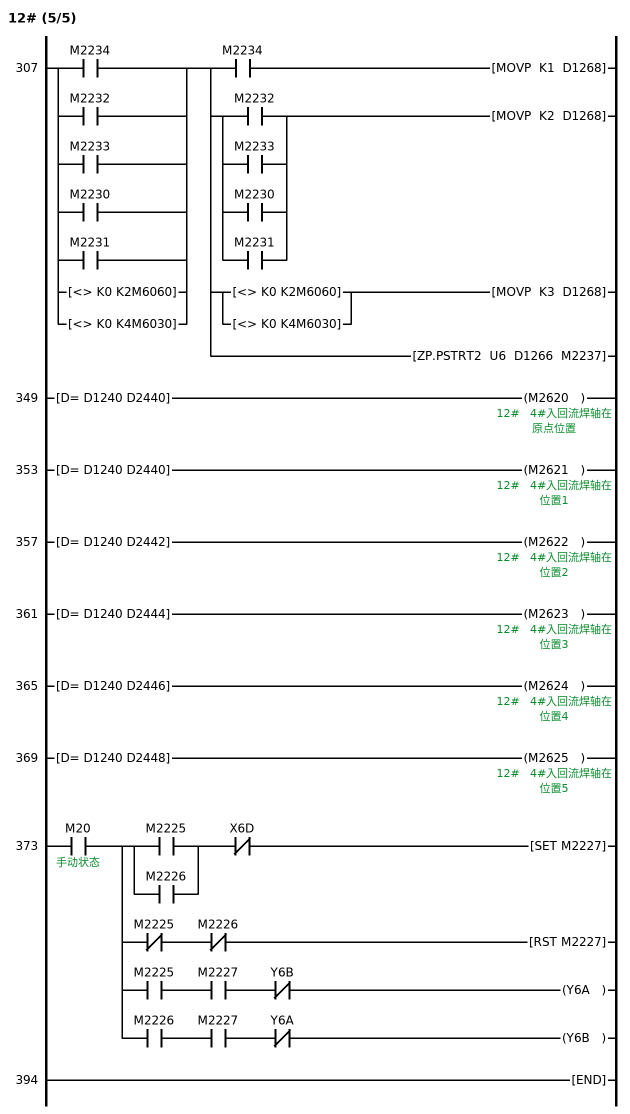
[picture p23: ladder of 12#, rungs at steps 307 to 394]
307   LD      M2234
      OR      M2232
      OR      M2233
      OR      M2230
      OR      M2231
      OR<>    K0 K2M6060  ; 12#  4#入回流焊轴位置1（自动）
      OR<>    K0 K4M6030  ; 12#  4#入回流焊轴位置1（手动）
      MPS
      AND     M2234
      MOVP    K1 D1268
      MRD
      LD      M2232
      OR      M2233
      OR      M2230
      OR      M2231
      ANB
      MOVP    K2 D1268
      MRD
      LD<>    K0 K2M6060  ; 12#  4#入回流焊轴位置1（自动）
      OR<>    K0 K4M6030  ; 12#  4#入回流焊轴位置1（手动）
      ANB
      MOVP    K3 D1268
      MPP
      ZP.PSTRT2 U6 D1266 M2237
349   LDD=    D1240 D2440
      OUT     M2620  ; 12#   4#入回流焊轴在原点位置
353   LDD=    D1240 D2440
      OUT     M2621  ; 12#   4#入回流焊轴在位置1
357   LDD=    D1240 D2442
      OUT     M2622  ; 12#   4#入回流焊轴在位置2
361   LDD=    D1240 D2444
      OUT     M2623  ; 12#   4#入回流焊轴在位置3
365   LDD=    D1240 D2446
      OUT     M2624  ; 12#   4#入回流焊轴在位置4
369   LDD=    D1240 D2448
      OUT     M2625  ; 12#   4#入回流焊轴在位置5
373   LD      M20  ; 手动状态
      MPS
      LD      M2225
      OR      M2226
      ANB
      ANI     X6D
      SET     M2227
      MRD
      ANI     M2225
      ANI     M2226
      RST     M2227
      MRD
      AND     M2225
      AND     M2227
      ANI     Y6B
      OUT     Y6A
      MPP
      AND     M2226
      AND     M2227
      ANI     Y6A
      OUT     Y6B
394   END
END_PROGRAM

PROGRAM 2#
0     LD      M20  ; 手动状态
      AND     SM400
      MPS
      AND     M2022  ; 2#折料手
      PLS     M2030  ; 2#折料手
      MRD
      AND     M2023  ; 2#旋转手
      PLS     M2031  ; 2#旋转手
      MRD
      LDP     M1100
      ANDD<>  D1020 D2040  ; 2#当前 / 2#位置1
      LDP     M2024  ; 2#手动移位
      ANDD=   D1020 D2050  ; 2#当前 / 2#位置6
      ORB
      ANB
      PLS     M1130
      MRD
      LDP     M1101
      ANDD<>  D1020 D2042  ; 2#当前 / 2#位置2
      LDP     M2024  ; 2#手动移位
      ANDD=   D1020 D2040  ; 2#当前 / 2#位置1
      ORB
      ANB
      PLS     M1131
      MRD
      LDP     M1102
      ANDD<>  D1020 D2044  ; 2#当前 / 2#位置3
      LDP     M2024  ; 2#手动移位
      ANDD=   D1020 D2042  ; 2#当前 / 2#位置2
      ORB
      ANB
      PLS     M1132
      MRD
      LDP     M1103
      ANDD<>  D1020 D2046  ; 2#当前 / 2#位置4
      LDP     M2024  ; 2#手动移位
      ANDD=   D1020 D2044  ; 2#当前 / 2#位置3
      ORB
      ANB
      PLS     M1133
      MRD
      LDP     M1104
      ANDD<>  D1020 D2048  ; 2#当前 / 2#位置5
      LDP     M2024  ; 2#手动移位
      ANDD=   D1020 D2046  ; 2#当前 / 2#位置4
      ORB
      ANB
      PLS     M1134
      MPP
      LDP     M1105
      ANDD<>  D1020 D2050  ; 2#当前 / 2#位置6
      LDP     M2024  ; 2#手动移位
      ANDD=   D1020 D2048  ; 2#当前 / 2#位置5
      ORB
      ANB
      PLS     M1135
88    LDI     M2511  ; 2#复原中
      AND     SM400
      MPS
      LDP     M2032  ; 2#折料
      ORP     M2030  ; 2#折料手
      ANB
      *       D1030 D1028 D1438  ; 一圈脉冲 / 次数 / 折料/旋转
      MRD
      LDP     M2033  ; 2#旋转
      ORP     M2031  ; 2#旋转手
      ANB
      DMOV    D1032 D1438  ; 2#旋转角度
      MRD
      LDP     M1160
      ORP     M1130
      ANB
      DMOV    D2040 D1423  ; 2#移位置
      MRD
      LDP     M1161
      ORP     M1131
      ANB
      DMOV    D2042 D1423
      MRD
      LDP     M1162
      ORP     M1132
      ANB
      DMOV    D2044 D1423
      MRD
      LDP     M1163
      ORP     M1133
      ANB
      DMOV    D2046 D1423
      MRD
      LDP     M1164
      ORP     M1134
      ANB
      DMOV    D2048 D1423
      MPP
      LDP     M1165
      ORP     M1135
      ANB
      DMOV    D2050 D1423
139   LDP     T110
      LD      M20  ; 手动状态
      ANDP    M2021  ; 2#复原
      ORB
      LDP     M20  ; 手动状态
      AND     T110
      ORF     M20  ; 手动状态
      ORF     M2020  ; 2#伺服ON
      AND     M17  ; 急停（外部按钮）
      ORB
      BKRSTP  B510 K10
      AND     B51F
      SET     B510
154   LD=     K0 K3B510
      OUT     B51F
      INV
      OUT     M2511  ; 2#复原中
160   LD      B510
      MPS
      ANI     M2720  ; 2#
      SET     B511
      MPP
      AND     M2720  ; 2#
      RST     B510
167   LD      B511
      RST     B510
      DMOV    K1000 D1426  ; JOG速度
      MOV     K50 D1428  ; JOG加速时间
      MOV     K50 D1429  ; JOG减速时间
      SET     B512
177   LD      B512
      RST     B511
      OUT     T111 K1
      ANI     SM1860
      AND     T111
      SET     B513
      BKRST   M2036 K2  ; GOJ+
189   LD      B513
      RST     B512
      MOV     K1 D1420  ; 回原点类型
      MOV     K0 D1421  ; 回原点待机地址
      ?OP654102 D1420
      SET     B514
198   LD      B514
      RST     B513
      PLS     M2038
      ANI     M2038
      AND     SM1863
      SET     B515
205   LD      B515
      RST     B514
      OUT     T113 K2
      AND     T113
      PLS     M2039  ; 2#原点定位
      ANI     M2039  ; 2#原点定位
      SET     B516
216   LD      B516
      RST     B515
      AND     SM1860
      SET     B517
220   LD      B517
      RST     B516
      AND     SM1861
      RST     B517
224   LD      M2039  ; 2#原点定位
      OR      M2032  ; 2#折料
      OR      M2033  ; 2#旋转
      OR      M2030  ; 2#折料手
      OR      M2031  ; 2#旋转手
      OR<>    K0 K2M1160
      OR<>    K0 K2M1130
      MPS
      LD      M2039  ; 2#原点定位
      OR<>    K0 K2M1160
      OR<>    K0 K2M1130
      ANB
      MOV     K1 D1430  ; 模式
      MRD
      LD      M2032  ; 2#折料
      OR      M2033  ; 2#旋转
      OR      M2030  ; 2#折料手
      OR      M2031  ; 2#旋转手
      ANB
      MOV     K2 D1430
      MPP
      MOV     K50 D1431  ; 夹速时间
      MOV     K50 D1432  ; 减速时间
      MOV     K0 D1433  ; 停顿时间
      MPS
      AND     M20  ; 手动状态
      DMOV    D1024 D1434  ; 手动频率 / 运行频率
      MRD
      ANI     M20  ; 手动状态
      DMOV    D1026 D1434  ; 自动频率
      MRD
      AND     M2039  ; 2#原点定位
      DMOV    D1022 D1436  ; 机械原点 / 执行位置
      MRD
      LD      M2032  ; 2#折料
      OR      M2033  ; 2#旋转
      OR      M2030  ; 2#折料手
      OR      M2031  ; 2#旋转手
      ANB
      DMOV    D1438 D1436
      MRD
      LD<>    K0 K2M1160
      OR<>    K0 K2M1130
      ANB
      DMOV    D1423 D1436
      MPP
      ?OP653C D1430
294   LD      M2036  ; GOJ+
      ANI     M2037  ; GOJ-
      OUT     M2034
297   LDI     M2036  ; GOJ+
      AND     M2037  ; GOJ-
      OUT     M2035
300   LD      M2034
      ANI     M2035
      LDI     M2034
      AND     M2035
      ORB
      ?OP653F D1426 M2034
308   LDD=    D1020 D1022  ; 2#当前 / 机械原点
      OUT     M2720  ; 2#
312   LDD=    D1020 D2040  ; 2#当前 / 2#位置1
      OUT     M2721  ; 2#
316   LDD=    D1020 D2042  ; 2#当前 / 2#位置2
      OUT     M2722  ; 2#
320   LDD=    D1020 D2044  ; 2#当前 / 2#位置3
      OUT     M2723  ; 2#
324   LDD=    D1020 D2046  ; 2#当前 / 2#位置4
      OUT     M2724  ; 2#
328   LDD=    D1020 D2048  ; 2#当前 / 2#位置5
      OUT     M2725  ; 2#
332   LDD=    D1020 D2050  ; 2#当前 / 2#位置6
      OUT     M2726  ; 2#
336   LDD=    D1020 D2052  ; 2#当前 / 2#位置7
      OUT     M2727  ; 2#
340   LDD=    D1020 D2054  ; 2#当前 / 2#位置8
      OUT     M2728
344   LDD=    D1020 D2056  ; 2#当前 / 2#位置9
      OUT     M2729
348   END
END_PROGRAM

PROGRAM 3#
0     LD      M20  ; 手动状态
      AND     SM400
      MPS
      AND     M2042  ; 3#手动折料
      PLS     M2050  ; 3#手动折料
      MRD
      AND     M2043  ; 3#手动旋转
      PLS     M2051  ; 3#手动旋转
      MRD
      LDP     M1200  ; 3#  2#送载带位置1（手动）
      ANDD<>  D1040 D2080  ; 3#当前值 / 1
      LDP     M2044  ; 3#ABS手
      ANDD=   D1040 D2082  ; 3#当前值 / 2
      ORB
      ANB
      PLS     M1230  ; 3#  2#送载带位置1（手动）
      MRD
      LDP     M1201  ; 3#  2#送载带位置2（手动）
      ANDD<>  D1040 D2082  ; 3#当前值 / 2
      LDP     M2044  ; 3#ABS手
      ANDD=   D1040 D2086  ; 3#当前值 / 4
      ORB
      ANB
      PLS     M1231  ; 3#  2#送载带位置2（手动）
      MRD
      LDP     M1202  ; 3#  2#送载带位置3（手动）
      ANDD<>  D1040 D2084  ; 3#当前值 / 3
      LDP     M2044  ; 3#ABS手
      ANDD=   D1040 D2080  ; 3#当前值 / 1
      ORB
      ANB
      PLS     M1232  ; 3#  2#送载带位置3（手动）
      MRD
      LDP     M1203  ; 3#  2#送载带位置4（手动）
      ANDD<>  D1040 D2086  ; 3#当前值 / 4
      LDP     M2044  ; 3#ABS手
      ANDD=   D1040 D2084  ; 3#当前值 / 3
      ORB
      ANB
      PLS     M1233  ; 3#  2#送载带位置4（手动）
      MRD
      LDP     M1204  ; 3#  2#送载带位置5（手动）
      ANDD<>  D1040 D2088  ; 3#当前值 / 5
      LDP     M2044  ; 3#ABS手
      ANDD=   D1040 D2086  ; 3#当前值 / 4
      ORB
      ANB
      PLS     M1234  ; 3#  2#送载带位置5（手动）
      MPP
      LDP     M1205
      ANDD<>  D1040 D2090  ; 3#当前值 / 6
      LDP     M2044  ; 3#ABS手
      ANDD=   D1040 D2088  ; 3#当前值 / 5
      ORB
      ANB
      PLS     M1235
88    LDI     M2521  ; 3#复原中
      AND     SM400
      MPS
      LDP     M2052  ; 3#折料
      ORP     M2050  ; 3#手动折料
      ANB
      *       D1050 D1048 D1058  ; 2#料带间距 / 3#次数 / 3#折料位置
      MRD
      LDP     M2053  ; 3#INC
      ORP     M2051  ; 3#手动旋转
      ANB
      DMOV    D1052 D1058  ; 3#INC旋转位置
      MRD
      LDP     M1260  ; 3#  2#送载带位置1（自动）
      ORP     M1230  ; 3#  2#送载带位置1（手动）
      ANB
      DMOV    D2080 D1450  ; 3#移位位置
      MRD
      LDP     M1261  ; 3#  2#送载带位置2（自动）
      ORP     M1231  ; 3#  2#送载带位置2（手动）
      ANB
      DMOV    D2082 D1450
      MRD
      LDP     M1262  ; 3#  2#送载带位置3（自动）
      ORP     M1232  ; 3#  2#送载带位置3（手动）
      ANB
      DMOV    D2084 D1450
      MRD
      LDP     M1263  ; 3#  2#送载带位置4（自动）
      ORP     M1233  ; 3#  2#送载带位置4（手动）
      ANB
      DMOV    D2086 D1450
      MRD
      LDP     M1264  ; 3#  2#送载带位置5（自动）
      ORP     M1234  ; 3#  2#送载带位置5（手动）
      ANB
      DMOV    D2088 D1450
      MPP
      LDP     M1265
      ORP     M1235
      ANB
      DMOV    D2090 D1450
139   LD      SM400
      MPS
      AND     M20  ; 手动状态
      DMOV    D1044 D1452  ; 3#手动频率 / 3#速度
      MRD
      ANI     M20  ; 手动状态
      DMOV    D1046 D1452  ; 3#自动速度
      MPP
      DMOV    D1452 U1\G2004
      DMOV    D1042 U1\G2006  ; 3#原点位置
      DMOV    D1452 U1\G2014
      DMOV    D1058 U1\G2016
      DMOV    D1452 U1\G2024
      DMOV    D1450 U1\G2026
      DMOV    D1452 U1\G2034
      DMOV    D1244 U1\G2036
181   LDP     T120
      LD      M20  ; 手动状态
      ANDP    M2041  ; 3#复原
      ORB
      LD      T120
      ANDP    M20  ; 手动状态
      ORF     M20  ; 手动状态
      ORF     M2040  ; 3#伺服ON
      AND     M17  ; 急停（外部按钮）
      ORB
      BKRST   B520 K10
      AND     B52F
      SET     B520
196   LD=     K0 K3B520
      OUT     B52F
      INV
      OUT     M2521  ; 3#复原中
202   LD      B520
      MPS
      ANI     M2740  ; 3#  2#送载带步进在原点位置
      ANI     SM400
      SET     B521
      MPP
      LD      M2740  ; 3#  2#送载带步进在原点位置
      OR      SM400
      ANB
      RST     B520
212   LD      B521
      RST     B520
      MOV     K9001 D1442  ; 原点执行
      MOV     K0 U1\G1521
      ZP.PSTRT1 "U1" D1440 M2055  ; 原点执行 / 原点完成
      SET     B522
230   LD      B522
      RST     B521
      AND     M2055  ; 原点完成
      MOV     K1 U1\G1521
      SET     B523
238   LD      B523
      RST     B522
      OUT     T123 K2
      AND     T123
      SET     B524
246   LD      B524
      RST     B523
      PLS     M2054  ; 回原点定位
      ANI     M2054  ; 回原点定位
      SET     B525
252   LD      B525
      RST     B524
      AND     M2057  ; 点胶A面X轴定位完成标志
      SET     B526
256   LD      B526
      RST     B525
      DMOV    K0 U1\G1506
      MOV     K9003 U1\G1500
      MPS
      ANDP    B526
      SET     Y20  ; 轴1定位启动
      MPP
      RST     B526
272   LD      Y20  ; 轴1定位启动
      OUT     T124 K2
      AND     T124
      RST     Y20  ; 轴1定位启动
279   LD      M2054  ; 回原点定位
      OR      M2052  ; 3#折料
      OR      M2053  ; 3#INC
      OR      M2050  ; 3#手动折料
      OR      M2051  ; 3#手动旋转
      OR<>    K0 K2M1260  ; 3#  2#送载带位置1（自动）
      OR<>    K0 K4M1230  ; 3#  2#送载带位置1（手动）
      MPS
      AND     M2054  ; 回原点定位
      MOVP    K1 D1448  ; 定位
      MRD
      LD      M2052  ; 3#折料
      OR      M2053  ; 3#INC
      OR      M2050  ; 3#手动折料
      OR      M2051  ; 3#手动旋转
      ANB
      MOVP    K2 D1448
      MRD
      LD<>    K0 K2M1260  ; 3#  2#送载带位置1（自动）
      OR<>    K0 K4M1230  ; 3#  2#送载带位置1（手动）
      ANB
      MOVP    K3 D1448
      MPP
      ZP.PSTRT1 U1 D1446 M2057  ; 定位
321   LDD=    D1040 D1042  ; 3#当前值 / 3#原点位置
      OUT     M2740  ; 3#  2#送载带步进在原点位置
325   LDD=    D1040 D2080  ; 3#当前值 / 1
      OUT     M2741  ; 3#  2#送载带步进在位置1
329   LDD=    D1040 D2082  ; 3#当前值 / 2
      OUT     M2742  ; 3#  2#送载带步进在位置2
333   LDD=    D1040 D2084  ; 3#当前值 / 3
      OUT     M2743  ; 3#  2#送载带步进在位置3
337   LDD=    D1040 D2086  ; 3#当前值 / 4
      OUT     M2744  ; 3#  2#送载带步进在位置4
341   LDD=    D1040 D2088  ; 3#当前值 / 5
      OUT     M2745  ; 3#  2#送载带步进在位置5
345   LD      M20  ; 手动状态
      ANDP    M3100  ; 2#拉料（手动）
      OR      M4102
      ANI     X1C  ; 轴1 busy
      ANI     M4100  ; 2#手动拉料
      AND     M615  ; 2#取产品上下气缸原点
      SET     M4100  ; 2#手动拉料
352   LD      M4100  ; 2#手动拉料
      INCP    D500  ; 2#拉料次数计数
      D*      D500 D1050 D5180  ; 2#拉料当前值比较
      D+P     D5180 D502 D5186  ; 2#拉料修正
      ANDD>=  D5280 D5186  ; 2#拉料编码器当前值
      RST     M4100  ; 2#手动拉料
365   LD      M20  ; 手动状态
      OR      M2300
      MPS
      LD      M2045  ; 2#拉料JOG+
      OR      M2046  ; 2#拉料JOG-
      OR      M4100  ; 2#手动拉料
      OR      M2300
      ANB
      ANI     X1C  ; 轴1 busy
      SET     M2047
      MRD
      ANI     M2045  ; 2#拉料JOG+
      ANI     M2046  ; 2#拉料JOG-
      ANI     M4100  ; 2#手动拉料
      ANI     M2300
      RST     M2047
      MRD
      AND     M2045  ; 2#拉料JOG+
      AND     M2047
      ANI     Y19  ; 轴1反向JOG
      OUT     Y18  ; 轴1正向JOG
      MPP
      LD      M2046  ; 2#拉料JOG-
      OR      M4100  ; 2#手动拉料
      OR      M2300
      ANB
      AND     M2047
      ANI     Y18  ; 轴1正向JOG
      OUT     Y19  ; 轴1反向JOG
394   END
END_PROGRAM

PROGRAM 4#
0     LD      M20  ; 手动状态
      AND     SM400
      MPS
      AND     M2062  ; 4#手动折料
      PLS     M2070  ; 4#手动折料
      MRD
      AND     M2063  ; 4#手动旋转
      PLS     M2071  ; 4#手动旋转
      MRD
      LDP     M1300  ; 4#  2#移载座轴位置1（手动）
      ANDD<>  D1060 D2120  ; 4#当前值 / 4#位置1
      LDP     M2064  ; 4#ABS手
      ANDD=   D1060 D2138  ; 4#当前值 / 4#位置10
      ORB
      ANB
      PLS     M1330  ; 4#  2#移载座轴位置1（手动）
      MRD
      LDP     M1301  ; 4#  2#移载座轴位置2（手动）
      ANDD<>  D1060 D2122  ; 4#当前值 / 4#位置2
      LDP     M2064  ; 4#ABS手
      ANDD=   D1060 D2120  ; 4#当前值 / 4#位置1
      ORB
      ANB
      PLS     M1331  ; 4#  2#移载座轴位置2（手动）
      MRD
      LDP     M1302  ; 4#  2#移载座轴位置3（手动）
      ANDD<>  D1060 D2124  ; 4#当前值 / 4#位置3
      LDP     M2064  ; 4#ABS手
      ANDD=   D1060 D2122  ; 4#当前值 / 4#位置2
      ORB
      ANB
      PLS     M1332  ; 4#  2#移载座轴位置3（手动）
      MRD
      LDP     M1303  ; 4#  2#移载座轴位置4（手动）
      ANDD<>  D1060 D2126  ; 4#当前值 / 4#位置4
      LDP     M2064  ; 4#ABS手
      ANDD=   D1060 D2124  ; 4#当前值 / 4#位置3
      ORB
      ANB
      PLS     M1333  ; 4#  2#移载座轴位置4（手动）
      MRD
      LDP     M1304  ; 4#  2#移载座轴位置5（手动）
      ANDD<>  D1060 D2128  ; 4#当前值 / 4#位置5
      LDP     M2064  ; 4#ABS手
      ANDD=   D1060 D2126  ; 4#当前值 / 4#位置4
      ORB
      ANB
      PLS     M1334  ; 4#  2#移载座轴位置5（手动）
      MRD
      LDP     M1305  ; 4#  2#移载座轴位置6（手动）
      ANDD<>  D1060 D2130  ; 4#当前值 / 4#位置6
      LDP     M2064  ; 4#ABS手
      ANDD=   D1060 D2128  ; 4#当前值 / 4#位置5
      ORB
      ANB
      PLS     M1335  ; 4#  2#移载座轴位置6（手动）
      MRD
      LDP     M1306  ; 4#  2#移载座轴位置7（手动）
      ANDD<>  D1060 D2132  ; 4#当前值 / 4#位置7
      LDP     M2064  ; 4#ABS手
      ANDD=   D1060 D2130  ; 4#当前值 / 4#位置6
      ORB
      ANB
      PLS     M1336  ; 4#  2#移载座轴位置7（手动）
      MRD
      LDP     M1307  ; 4#  2#移载座轴位置8（手动）
      ANDD<>  D1060 D2134  ; 4#当前值 / 4#位置8
      LDP     M2064  ; 4#ABS手
      ANDD=   D1060 D2132  ; 4#当前值 / 4#位置7
      ORB
      ANB
      PLS     M1337  ; 4#  2#移载座轴位置8（手动）
      MRD
      LDP     M1308  ; 4#  2#移载座轴位置9（手动）
      ANDD<>  D1060 D2136  ; 4#当前值 / 4#位置9
      LDP     M2064  ; 4#ABS手
      ANDD=   D1060 D2134  ; 4#当前值 / 4#位置8
      ORB
      ANB
      PLS     M1338  ; 4#  2#移载座轴位置9（手动）
      MPP
      LDP     M1309  ; 4#  2#移载座轴位置10（手动）
      ANDD<>  D1060 D2138  ; 4#当前值 / 4#位置10
      LDP     M2064  ; 4#ABS手
      ANDD=   D1060 D2136  ; 4#当前值 / 4#位置9
      ORB
      ANB
      PLS     M1339  ; 4#  2#移载座轴位置10（手动）
140   LD      SM400
      MPS
      ANI     M4515  ; 产品选择按钮（OFF为产品1）
      DMOV    D6100 D2120  ; 2#产品1移载座位置1
      MRD
      AND     M4515  ; 产品选择按钮（OFF为产品1）
      DMOV    D6200 D2120  ; 2#产品2移载座位置1
      MRD
      ANI     M4515  ; 产品选择按钮（OFF为产品1）
      DMOV    D6102 D2122  ; 2#产品1移载座位置2
      MRD
      AND     M4515  ; 产品选择按钮（OFF为产品1）
      DMOV    D6202 D2122  ; 2#产品2移载座位置2
      MRD
      ANI     M4515  ; 产品选择按钮（OFF为产品1）
      DMOV    D6104 D2124  ; 2#产品1移载座位置3
      MRD
      AND     M4515  ; 产品选择按钮（OFF为产品1）
      DMOV    D6204 D2124  ; 2#产品2移载座位置3
      MRD
      ANI     M4515  ; 产品选择按钮（OFF为产品1）
      DMOV    D6106 D2126  ; 2#产品1移载座位置4
      MRD
      AND     M4515  ; 产品选择按钮（OFF为产品1）
      DMOV    D6206 D2126  ; 2#产品2移载座位置4
      MRD
      ANI     M4515  ; 产品选择按钮（OFF为产品1）
      DMOV    D6108 D2128  ; 2#产品1移载座位置5
      MPP
      AND     M4515  ; 产品选择按钮（OFF为产品1）
      DMOV    D6208 D2128  ; 2#产品2移载座位置5
181   LDI     M2531  ; 4#复原中
      AND     M2801  ; 6#  2#装产品轴在位置1
      AND     SM400
      MPS
      LDP     M2072  ; 4#折料
      ORP     M2070  ; 4#手动折料
      ANB
      *       D1070 D1068 D1078  ; 4#每转脉冲 / 4#次数 / 4#折料位置
      MRD
      LDP     M2073  ; 4#INC
      ORP     M2071  ; 4#手动旋转
      ANB
      DMOV    D1072 D1078  ; 4#INC旋转位置
      MRD
      LDP     M1360  ; 4#  2#移载座轴位置1（自动）
      ORP     M1330  ; 4#  2#移载座轴位置1（手动）
      ANB
      DMOV    D2120 D1470  ; 移位置
      MRD
      LDP     M1361  ; 4#  2#移载座轴位置2（自动）
      ORP     M1331  ; 4#  2#移载座轴位置2（手动）
      ANB
      DMOV    D2122 D1470
      MRD
      LDP     M1362  ; 4#  2#移载座轴位置3（自动）
      ORP     M1332  ; 4#  2#移载座轴位置3（手动）
      ANB
      DMOV    D2124 D1470
      MRD
      LDP     M1363  ; 4#  2#移载座轴位置4（自动）
      ORP     M1333  ; 4#  2#移载座轴位置4（手动）
      ANB
      DMOV    D2126 D1470
      MPP
      LDP     M1364  ; 4#  2#移载座轴位置5（自动）
      ORP     M1334  ; 4#  2#移载座轴位置5（手动）
      ANB
      DMOV    D2128 D1470
227   LD      SM400
      MPS
      ANI     M4515  ; 产品选择按钮（OFF为产品1）
      DMOV    D6110 D2130  ; 2#产品1移载座位置6
      MRD
      AND     M4515  ; 产品选择按钮（OFF为产品1）
      DMOV    D6210 D2130  ; 2#产品2移载座位置6
      MRD
      ANI     M4515  ; 产品选择按钮（OFF为产品1）
      DMOV    D6112 D2132  ; 2#产品1移载座位置7
      MRD
      AND     M4515  ; 产品选择按钮（OFF为产品1）
      DMOV    D6212 D2132  ; 2#产品2移载座位置7
      MRD
      ANI     M4515  ; 产品选择按钮（OFF为产品1）
      DMOV    D6114 D2134  ; 2#产品1移载座位置8
      MRD
      AND     M4515  ; 产品选择按钮（OFF为产品1）
      DMOV    D6214 D2134  ; 2#产品2移载座位置8
      MRD
      ANI     M4515  ; 产品选择按钮（OFF为产品1）
      DMOV    D6116 D2136  ; 2#产品1移载座位置9
      MRD
      AND     M4515  ; 产品选择按钮（OFF为产品1）
      DMOV    D6216 D2136  ; 2#产品2移载座位置9
      MRD
      ANI     M4515  ; 产品选择按钮（OFF为产品1）
      DMOV    D6118 D2138  ; 2#产品1移载座位置10
      MPP
      AND     M4515  ; 产品选择按钮（OFF为产品1）
      DMOV    D6218 D2138
268   LDI     M2531  ; 4#复原中
      AND     SM400
      MPS
      LDP     M1365  ; 4#  2#移载座轴位置6（自动）
      ORP     M1335  ; 4#  2#移载座轴位置6（手动）
      ANB
      DMOV    D2130 D1470
      MRD
      LDP     M1366  ; 4#  2#移载座轴位置7（自动）
      ORP     M1336  ; 4#  2#移载座轴位置7（手动）
      ANB
      DMOV    D2132 D1470
      MRD
      LDP     M1367  ; 4#  2#移载座轴位置8（自动）
      ORP     M1337  ; 4#  2#移载座轴位置8（手动）
      ANB
      DMOV    D2134 D1470
      MRD
      LDP     M1368  ; 4#  2#移载座轴位置9（自动）
      ORP     M1338  ; 4#  2#移载座轴位置9（手动）
      ANB
      DMOV    D2136 D1470
      MPP
      LDP     M1369  ; 4#  2#移载座轴位置10（自动）
      ORP     M1339  ; 4#  2#移载座轴位置10（手动）
      ANB
      DMOV    D2138 D1470
300   LD      SM400
      MPS
      AND     M20  ; 手动状态
      DMOV    D1064 D1472  ; 4#手动频率 / 运行速度
      MRD
      ANI     M20  ; 手动状态
      DMOV    D1066 D1472  ; 4#自动速度
      MPP
      DMOV    D1472 U1\G8004
      DMOV    D1062 U1\G8006  ; 4#原点位置
      DMOV    D1472 U1\G8014
      DMOV    D1078 U1\G8016
      DMOV    D1472 U1\G8024
      DMOV    D1470 U1\G8026
      DMOV    D1472 U1\G8034
      DMOV    D1244 U1\G8036
342   LDP     T130
      LD      M20  ; 手动状态
      ANDP    M2061  ; 4#复原
      ORB
      LDP     M20  ; 手动状态
      AND     T130
      ORF     M20  ; 手动状态
      ORF     M2060  ; 4#伺服ON
      AND     M17  ; 急停（外部按钮）
      ORB
      BKRST   B530 K10
      MPS
      AND     B53F
      SET     B530
      MPP
      LDP     T130
      OR      M2061  ; 4#复原
      ORF     M2060  ; 4#伺服ON
      ANB
      SET     M54  ; 2#移载座轴上电回原点用
364   LD=     K0 K3B530
      OUT     B53F
      INV
      OUT     M2531  ; 4#复原中
370   LD      B530
      MPS
      LDI     M2760  ; 4#  2#移载座轴在原点位置
      OR      M54  ; 2#移载座轴上电回原点用
      ANB
      AND     M609  ; 2#挡载座气缸原点
      ANI     M4010  ; 2#定载座1（输出）
      ANI     M4011  ; 2#定载座2（输出）
      ANI     M4012  ; 2#压产品（输出）
      AND     M610  ; 2#定载座1气缸原点
      AND     M611  ; 2#定载座2气缸原点
      AND     M612  ; 2#压产品气缸原点
      SET     B531
      MPP
      AND     M2760  ; 4#  2#移载座轴在原点位置
      ANI     M54  ; 2#移载座轴上电回原点用
      RST     B530
387   LD      B531
      RST     B530
      RST     M54  ; 2#移载座轴上电回原点用
      MOV     K9001 D1462
      MOV     K0 U1\G1621
      ZP.PSTRT2 "U1" D1460 M2075  ; 原点完成
      SET     B532
406   LD      B532
      RST     B531
      AND     M2075  ; 原点完成
      MOV     K1 U1\G1621
      SET     B533
414   LD      B533
      RST     B532
      OUT     T133 K2
      AND     T133
      SET     B534
422   LD      B534
      RST     B533
      PLS     M2074  ; 回原点定位
      ANI     M2074  ; 回原点定位
      SET     B535
428   LD      B535
      RST     B534
      AND     M2077
      SET     B536
432   LD      B536
      RST     B535
      DMOV    K0 U1\G1606
      MOV     K9003 U1\G1600
      MPS
      ANDP    B536
      SET     Y21  ; 轴2定位启动
      MPP
      RST     B536
448   LD      Y21  ; 轴2定位启动
      OUT     T134 K2
      AND     T134
      RST     Y21  ; 轴2定位启动
455   LD      M2074  ; 回原点定位
      OR      M2072  ; 4#折料
      OR      M2073  ; 4#INC
      OR      M2070  ; 4#手动折料
      OR      M2071  ; 4#手动旋转
      OR<>    K0 K2M1360  ; 4#  2#移载座轴位置1（自动）
      OR      M1368  ; 4#  2#移载座轴位置9（自动）
      OR      M1369  ; 4#  2#移载座轴位置10（自动）
      OR<>    K0 K4M1330  ; 4#  2#移载座轴位置1（手动）
      MPS
      AND     M2074  ; 回原点定位
      MOVP    K1 D1468
      MRD
      LD      M2072  ; 4#折料
      OR      M2073  ; 4#INC
      OR      M2070  ; 4#手动折料
      OR      M2071  ; 4#手动旋转
      ANB
      MOVP    K2 D1468
      MRD
      LD<>    K0 K2M1360  ; 4#  2#移载座轴位置1（自动）
      OR      M1368  ; 4#  2#移载座轴位置9（自动）
      OR      M1369  ; 4#  2#移载座轴位置10（自动）
      OR<>    K0 K4M1330  ; 4#  2#移载座轴位置1（手动）
      ANB
      MOVP    K3 D1468
      MPP
      ZP.PSTRT2 U1 D1466 M2077
501   LDD=    D1060 D2120  ; 4#当前值 / 4#位置1
      OUT     M2760  ; 4#  2#移载座轴在原点位置
505   LDD=    D1060 D2120  ; 4#当前值 / 4#位置1
      OUT     M2761  ; 4#  2#移载座轴在位置1
509   LDD=    D1060 D2122  ; 4#当前值 / 4#位置2
      OUT     M2762  ; 4#  2#移载座轴在位置2
513   LDD=    D1060 D2124  ; 4#当前值 / 4#位置3
      OUT     M2763  ; 4#  2#移载座轴在位置3
517   LDD=    D1060 D2126  ; 4#当前值 / 4#位置4
      OUT     M2764  ; 4#  2#移载座轴在位置4
521   LDD=    D1060 D2128  ; 4#当前值 / 4#位置5
      OUT     M2765  ; 4#  2#移载座轴在位置5
525   LDD=    D1060 D2130  ; 4#当前值 / 4#位置6
      OUT     M2766  ; 4#  2#移载座轴在位置6
529   LDD=    D1060 D2132  ; 4#当前值 / 4#位置7
      OUT     M2767  ; 4#  2#移载座轴在位置7
533   LDD=    D1060 D2134  ; 4#当前值 / 4#位置8
      OUT     M2768  ; 4#  2#移载座轴在位置8
537   LDD=    D1060 D2136  ; 4#当前值 / 4#位置9
      OUT     M2769  ; 4#  2#移载座轴在位置9
541   LDD=    D1060 D2138  ; 4#当前值 / 4#位置10
      OUT     M2770  ; 4#  2#移载座轴在位置10
545   LD      M20  ; 手动状态
      MPS
      LD      M2065
      OR      M2066
      ANB
      ANI     X1D  ; 轴2 busy
      SET     M2067
      MRD
      ANI     M2065
      ANI     M2066
      RST     M2067
      MRD
      AND     M2065
      AND     M2067
      ANI     Y1B  ; 轴2反向JOG
      OUT     Y1A  ; 轴2正向JOG
      MPP
      AND     M2066
      AND     M2067
      ANI     Y1A  ; 轴2正向JOG
      OUT     Y1B  ; 轴2反向JOG
566   END
END_PROGRAM

PROGRAM 5#
0     LD      M20  ; 手动状态
      AND     SM400
      MPS
      AND     M2082  ; 5#手动折料
      PLS     M2090  ; 5#手动折料
      MRD
      AND     M2083  ; 5#手动旋转
      PLS     M2091  ; 5#手动旋转
      MRD
      LDP     M1400  ; 5#  2#出载带移载位置1（手动）
      ANDD<>  D1080 D2160  ; 5#当前值 / 1
      LDP     M2084  ; 5#ABS手
      ANDD=   D1080 D2162  ; 5#当前值 / 2
      ORB
      ANB
      ANI     M4015  ; 2#取产品上下输出
      AND     M615  ; 2#取产品上下气缸原点
      PLS     M1430  ; 5#  2#出载带移载位置1（手动）
      MRD
      LDP     M1401  ; 5#  2#出载带移载位置2（手动）
      ANDD<>  D1080 D2162  ; 5#当前值 / 2
      LDP     M2084  ; 5#ABS手
      ANDD=   D1080 D2166  ; 5#当前值 / 4
      ORB
      ANB
      ANI     M4015  ; 2#取产品上下输出
      AND     M615  ; 2#取产品上下气缸原点
      PLS     M1431  ; 5#  2#出载带移载位置2（手动）
      MRD
      LDP     M1402  ; 5#  2#出载带移载位置3（手动）
      ANDD<>  D1080 D2164  ; 5#当前值 / 3
      LDP     M2084  ; 5#ABS手
      ANDD=   D1080 D2160  ; 5#当前值 / 1
      ORB
      ANB
      ANI     M4015  ; 2#取产品上下输出
      AND     M615  ; 2#取产品上下气缸原点
      PLS     M1432  ; 5#  2#出载带移载位置3（手动）
      MRD
      LDP     M1403  ; 5#  2#出载带移载位置4（手动）
      ANDD<>  D1080 D2166  ; 5#当前值 / 4
      LDP     M2084  ; 5#ABS手
      ANDD=   D1080 D2164  ; 5#当前值 / 3
      ORB
      ANB
      ANI     M4015  ; 2#取产品上下输出
      AND     M615  ; 2#取产品上下气缸原点
      PLS     M1433  ; 5#  2#出载带移载位置4（手动）
      MRD
      LDP     M1404  ; 5#  2#出载带移载位置5（手动）
      ANDD<>  D1080 D2168  ; 5#当前值 / 5
      LDP     M2084  ; 5#ABS手
      ANDD=   D1080 D2166  ; 5#当前值 / 4
      ORB
      ANB
      ANI     M4015  ; 2#取产品上下输出
      AND     M615  ; 2#取产品上下气缸原点
      PLS     M1434  ; 5#  2#出载带移载位置5（手动）
      MPP
      LDP     M1405  ; 5#  2#出载带移载位置6（手动）
      ANDD<>  D1080 D2170  ; 5#当前值 / 6
      LDP     M2084  ; 5#ABS手
      ANDD=   D1080 D2168  ; 5#当前值 / 5
      ORB
      ANB
      ANI     M4015  ; 2#取产品上下输出
      AND     M615  ; 2#取产品上下气缸原点
      PLS     M1435  ; 5#  2#出载带移载位置6（手动）
100   LDI     M2541  ; 5#复原中
      AND     SM400
      MPS
      LDP     M2092  ; 5#折料
      ORP     M2090  ; 5#手动折料
      ANB
      *       D1090 D1088 D1098  ; 5#每转脉冲 / 5#次数 / 5#折料位置
      MRD
      LDP     M2093  ; 5#INC
      ORP     M2091  ; 5#手动旋转
      ANB
      DMOV    D1092 D1098  ; 5#INC旋转位置
      MRD
      LDP     M1460  ; 5#  2#出载带移载位置1（自动）
      ORP     M1430  ; 5#  2#出载带移载位置1（手动）
      ANB
      DMOV    D2160 D1490  ; 移位置
      MRD
      LDP     M1461  ; 5#  2#出载带移载位置2（自动）
      ORP     M1431  ; 5#  2#出载带移载位置2（手动）
      ANB
      DMOV    D2162 D1490
      MRD
      LDP     M1462  ; 5#  2#出载带移载位置3（自动）
      ORP     M1432  ; 5#  2#出载带移载位置3（手动）
      ANB
      DMOV    D2164 D1490
      MRD
      LDP     M1463  ; 5#  2#出载带移载位置4（自动）
      ORP     M1433  ; 5#  2#出载带移载位置4（手动）
      ANB
      DMOV    D2166 D1490
      MRD
      LDP     M1464  ; 5#  2#出载带移载位置5（自动）
      ORP     M1434  ; 5#  2#出载带移载位置5（手动）
      ANB
      DMOV    D2168 D1490
      MPP
      LDP     M1465  ; 5#  2#出载带移载位置6（自动）
      ORP     M1435  ; 5#  2#出载带移载位置6（手动）
      ANB
      DMOV    D2170 D1490
151   LD      SM400
      MPS
      AND     M20  ; 手动状态
      DMOV    D1084 D1492  ; 5#手动频率 / 运行速度
      MRD
      ANI     M20  ; 手动状态
      DMOV    D1086 D1492  ; 5#自动速度
      MPP
      DMOV    D1492 U1\G14004
      DMOV    D1082 U1\G14006  ; 5#原点位置
      DMOV    D1492 U1\G14014
      DMOV    D1098 U1\G14016
      DMOV    D1492 U1\G14024
      DMOV    D1490 U1\G14026
      DMOV    D1492 U1\G14034
      DMOV    D1244 U1\G14036
193   LDP     T140
      LD      M20  ; 手动状态
      ANDP    M2081  ; 5#复原
      ORB
      LD      T140
      ANDP    M20  ; 手动状态
      ORF     M20  ; 手动状态
      ORF     M2080  ; 5#伺服ON
      AND     M17  ; 急停（外部按钮）
      ORB
      BKRST   B540 K10
      MPS
      AND     B54F
      SET     B540
      MPP
      LDP     T140
      OR      M2081  ; 5#复原
      ORF     M2080  ; 5#伺服ON
      ANB
      SET     M55  ; 2#出载带移栽上电回原点用
215   LD=     K0 K3B540
      OUT     B54F
      INV
      OUT     M2541  ; 5#复原中
221   LD      B540
      MPS
      LDI     M2780  ; 5#  2#出载带移载在原点位置
      OR      M55  ; 2#出载带移栽上电回原点用
      ANB
      ANI     M4015  ; 2#取产品上下输出
      AND     M615  ; 2#取产品上下气缸原点
      SET     B541
      MPP
      AND     M2780  ; 5#  2#出载带移载在原点位置
      ANI     M55  ; 2#出载带移栽上电回原点用
      RST     B540
233   LD      B541
      RST     B540
      RST     M55  ; 2#出载带移栽上电回原点用
      MOV     K9001 D1482
      MOV     K0 U1\G1721
      ZP.PSTRT3 "U1" D1480 M2095  ; 原点完成
      SET     B542
252   LD      B542
      RST     B541
      AND     M2095  ; 原点完成
      MOV     K1 U1\G1721
      SET     B543
260   LD      B543
      RST     B542
      OUT     T143 K2
      AND     T143
      SET     B544
268   LD      B544
      RST     B543
      PLS     M2094  ; 回原点定位
      ANI     M2094  ; 回原点定位
      SET     B545
274   LD      B545
      RST     B544
      AND     M2097
      SET     B546
278   LD      B546
      RST     B545
      DMOV    K0 U1\G1706
      MOV     K9003 U1\G1700
      MPS
      ANDP    B546
      SET     Y22  ; 轴+3定位启动
      MPP
      RST     B546
294   LD      Y22  ; 轴+3定位启动
      OUT     T144 K2
      AND     T144
      RST     Y22  ; 轴+3定位启动
301   LD      M2094  ; 回原点定位
      OR      M2092  ; 5#折料
      OR      M2093  ; 5#INC
      OR      M2090  ; 5#手动折料
      OR      M2091  ; 5#手动旋转
      OR<>    K0 K2M1460  ; 5#  2#出载带移载位置1（自动）
      OR<>    K0 K4M1430  ; 5#  2#出载带移载位置1（手动）
      MPS
      AND     M2094  ; 回原点定位
      MOVP    K1 D1488
      MRD
      LD      M2092  ; 5#折料
      OR      M2093  ; 5#INC
      OR      M2090  ; 5#手动折料
      OR      M2091  ; 5#手动旋转
      ANB
      MOVP    K2 D1488
      MRD
      LD<>    K0 K2M1460  ; 5#  2#出载带移载位置1（自动）
      OR<>    K0 K4M1430  ; 5#  2#出载带移载位置1（手动）
      ANB
      MOVP    K3 D1488
      MPP
      ANI     M4015  ; 2#取产品上下输出
      AND     M615  ; 2#取产品上下气缸原点
      ZP.PSTRT3 U1 D1486 M2097
345   LDD=    D1080 D2160  ; 5#当前值 / 1
      OUT     M2780  ; 5#  2#出载带移载在原点位置
349   LDD=    D1080 D2160  ; 5#当前值 / 1
      OUT     M2781  ; 5#  2#出载带移载在位置1
353   LDD=    D1080 D2162  ; 5#当前值 / 2
      OUT     M2782  ; 5#  2#出载带移载在位置2
357   LDD=    D1080 D2164  ; 5#当前值 / 3
      OUT     M2783  ; 5#  2#出载带移载在位置3
361   LDD=    D1080 D2166  ; 5#当前值 / 4
      OUT     M2784  ; 5#  2#出载带移载在位置4
365   LDD=    D1080 D2168  ; 5#当前值 / 5
      OUT     M2785  ; 5#  2#出载带移载在位置5
369   LDD=    D1080 D2170  ; 5#当前值 / 6
      OUT     M2786  ; 5#  2#出载带移载在位置6
373   LD      M20  ; 手动状态
      MPS
      LD      M2085
      OR      M2086
      ANB
      ANI     X1E  ; 轴3 busy
      SET     M2087
      MRD
      ANI     M2085
      ANI     M2086
      RST     M2087
      MRD
      AND     M2085
      AND     M2087
      ANI     Y1D  ; 轴3反向JOG
      OUT     Y1C  ; 轴3正向JOG
      MPP
      AND     M2086
      AND     M2087
      ANI     Y1C  ; 轴3正向JOG
      OUT     Y1D  ; 轴3反向JOG
394   END
END_PROGRAM

PROGRAM 6#
0     LD      M20  ; 手动状态
      AND     SM400
      MPS
      AND     M2102  ; 6#手动折料
      PLS     M2110  ; 6#手动折料
      MRD
      AND     M2103  ; 6#手动旋转
      PLS     M2111  ; 6#手动旋转
      MRD
      LDP     M1500  ; 6#  2#装产品轴位置1（手动）
      ANDD<>  D1100 D2200  ; 6#当前值 / 1
      LDP     M2104  ; 6#ABS手
      ANDD=   D1100 D2202  ; 6#当前值 / 2
      ORB
      ANB
      ANI     M4017  ; 2#推产品（输出）
      ANI     M4018  ; 2#挡产品（输出）
      AND     M617  ; 2#推产品气缸原点
      AND     M618  ; 2#挡产品气缸原点
      PLS     M1530  ; 6#  2#装产品轴位置1（手动）
      MRD
      LDP     M1501  ; 6#  2#装产品轴位置2（手动）
      ANDD<>  D1100 D2202  ; 6#当前值 / 2
      LDP     M2104  ; 6#ABS手
      ANDD=   D1100 D2206  ; 6#当前值 / 4
      ORB
      ANB
      ANI     M4017  ; 2#推产品（输出）
      ANI     M4018  ; 2#挡产品（输出）
      AND     M617  ; 2#推产品气缸原点
      AND     M618  ; 2#挡产品气缸原点
      PLS     M1531  ; 6#  2#装产品轴位置2（手动）
      MRD
      LDP     M1502  ; 6#  2#装产品轴位置3（手动）
      ANDD<>  D1100 D2204  ; 6#当前值 / 3
      LDP     M2104  ; 6#ABS手
      ANDD=   D1100 D2200  ; 6#当前值 / 1
      ORB
      ANB
      ANI     M4017  ; 2#推产品（输出）
      ANI     M4018  ; 2#挡产品（输出）
      AND     M617  ; 2#推产品气缸原点
      AND     M618  ; 2#挡产品气缸原点
      PLS     M1532  ; 6#   2#装产品轴位置3（手动）
      MRD
      LDP     M1503  ; 6#  2#装产品轴位置4（手动）
      ANDD<>  D1100 D2206  ; 6#当前值 / 4
      LDP     M2104  ; 6#ABS手
      ANDD=   D1100 D2204  ; 6#当前值 / 3
      ORB
      ANB
      ANI     M4017  ; 2#推产品（输出）
      ANI     M4018  ; 2#挡产品（输出）
      AND     M617  ; 2#推产品气缸原点
      AND     M618  ; 2#挡产品气缸原点
      PLS     M1533  ; 6#  2# 装产品轴位置4（手动）
      MRD
      LDP     M1504  ; 6#   2#装产品轴位置5（手动）
      ANDD<>  D1100 D2208  ; 6#当前值 / 5
      LDP     M2104  ; 6#ABS手
      ANDD=   D1100 D2206  ; 6#当前值 / 4
      ORB
      ANB
      ANI     M4017  ; 2#推产品（输出）
      ANI     M4018  ; 2#挡产品（输出）
      AND     M617  ; 2#推产品气缸原点
      AND     M618  ; 2#挡产品气缸原点
      PLS     M1534  ; 6#  2#装产品轴位置5（手动）
      MPP
      LDP     M1505  ; 6#  2#装产品轴位置6（手动）
      ANDD<>  D1100 D2210  ; 6#当前值 / 6
      LDP     M2104  ; 6#ABS手
      ANDD=   D1100 D2208  ; 6#当前值 / 5
      ORB
      ANB
      ANI     M4017  ; 2#推产品（输出）
      ANI     M4018  ; 2#挡产品（输出）
      AND     M617  ; 2#推产品气缸原点
      AND     M618  ; 2#挡产品气缸原点
      PLS     M1535  ; 6#  2#装产品轴位置6（手动）
112   LDI     M2551  ; 6#复原中
      AND     SM400
      MPS
      LDP     M2112  ; 6#折料
      ORP     M2110  ; 6#手动折料
      ANB
      *       D1110 D1108 D1118  ; 6#每转脉冲 / 6#次数 / 6#折料位置
      MRD
      LDP     M2113  ; 6#INC
      ORP     M2111  ; 6#手动旋转
      ANB
      DMOV    D1112 D1118  ; 6#INC旋转位置
      MRD
      LDP     M1560  ; 6#   2#装产品轴位置1（自动）
      ORP     M1530  ; 6#  2#装产品轴位置1（手动）
      ANB
      DMOV    D2200 D1510  ; 开路NG位
      MRD
      LDP     M1561  ; 6#  2#装产品轴位置2（自动）
      ORP     M1531  ; 6#  2#装产品轴位置2（手动）
      ANB
      DMOV    D2202 D1510
      MRD
      LDP     M1562  ; 6#  2#装产品轴位置3（自动）
      ORP     M1532  ; 6#   2#装产品轴位置3（手动）
      ANB
      DMOV    D2204 D1510
      MRD
      LDP     M1563  ; 6#   2#装产品轴位置4（自动）
      ORP     M1533  ; 6#  2# 装产品轴位置4（手动）
      ANB
      DMOV    D2206 D1510
      MRD
      LDP     M1564  ; 6#  2#装产品轴位置5（自动）
      ORP     M1534  ; 6#  2#装产品轴位置5（手动）
      ANB
      DMOV    D2208 D1510
      MPP
      LDP     M1565  ; 6#  2#装产品轴位置6（自动）
      ORP     M1535  ; 6#  2#装产品轴位置6（手动）
      ANB
      DMOV    D2210 D1510
163   LD      SM400
      MPS
      AND     M20  ; 手动状态
      DMOV    D1104 D1512  ; 6#手动频率 / 短路NG位
      MRD
      ANI     M20  ; 手动状态
      DMOV    D1106 D1512  ; 6#自动速度
      MPP
      DMOV    D1512 U1\G20004
      DMOV    D1102 U1\G20006  ; 6#原点位置
      DMOV    D1512 U1\G20014
      DMOV    D1118 U1\G20016
      DMOV    D1512 U1\G20024
      DMOV    D1510 U1\G20026
      DMOV    D1512 U1\G20034
      DMOV    D1244 U1\G20036
205   LDP     T150
      LD      M20  ; 手动状态
      ANDP    M2101  ; 6#复原
      ORB
      LD      T150
      ANDP    M20  ; 手动状态
      ORF     M20  ; 手动状态
      ORF     M2100  ; 6#伺服ON
      AND     M17  ; 急停（外部按钮）
      ORB
      BKRST   B550 K10
      MPS
      AND     B55F
      SET     B550
      MPP
      LDP     T150
      OR      M2101  ; 6#复原
      ORF     M2100  ; 6#伺服ON
      ANB
      SET     M56  ; 2#装产品上电回原点用
227   LD=     K0 K3B550
      OUT     B55F
      INV
      OUT     M2551  ; 6#复原中
233   LD      B550
      MPS
      LDI     M2800  ; 6#  2#装产品轴在原点位置
      OR      M56  ; 2#装产品上电回原点用
      ANB
      ANI     M4017  ; 2#推产品（输出）
      ANI     M4018  ; 2#挡产品（输出）
      AND     M617  ; 2#推产品气缸原点
      AND     M618  ; 2#挡产品气缸原点
      SET     B551
      MPP
      AND     M2800  ; 6#  2#装产品轴在原点位置
      ANI     M56  ; 2#装产品上电回原点用
      RST     B550
247   LD      B551
      RST     B550
      RST     M56  ; 2#装产品上电回原点用
      MOV     K9001 D1502  ; 位置2
      MOV     K0 U1\G1821
      ZP.PSTRT4 "U1" D1500 M2115  ; 位置1 / 原点完成
      SET     B552
266   LD      B552
      RST     B551
      AND     M2115  ; 原点完成
      MOV     K1 U1\G1821
      SET     B553
274   LD      B553
      RST     B552
      OUT     T153 K2
      AND     T153
      SET     B554
282   LD      B554
      RST     B553
      PLS     M2114  ; 回原点定位
      ANI     M2114  ; 回原点定位
      SET     B555
288   LD      B555
      RST     B554
      AND     M2117
      SET     B556
292   LD      B556
      RST     B555
      DMOV    K0 U1\G1806
      MOV     K9003 U1\G1800
      MPS
      ANDP    B556
      SET     Y23  ; 轴4定位启动
      MPP
      RST     B556
308   LD      Y23  ; 轴4定位启动
      OUT     T154 K2
      AND     T154
      RST     Y23  ; 轴4定位启动
315   LD      M2114  ; 回原点定位
      OR      M2112  ; 6#折料
      OR      M2113  ; 6#INC
      OR      M2110  ; 6#手动折料
      OR      M2111  ; 6#手动旋转
      OR<>    K0 K2M1560  ; 6#   2#装产品轴位置1（自动）
      OR<>    K0 K4M1530  ; 6#  2#装产品轴位置1（手动）
      MPS
      AND     M2114  ; 回原点定位
      MOVP    K1 D1508  ; 位置5
      MRD
      LD      M2112  ; 6#折料
      OR      M2113  ; 6#INC
      OR      M2110  ; 6#手动折料
      OR      M2111  ; 6#手动旋转
      ANB
      MOVP    K2 D1508
      MRD
      LD<>    K0 K2M1560  ; 6#   2#装产品轴位置1（自动）
      OR<>    K0 K4M1530  ; 6#  2#装产品轴位置1（手动）
      ANB
      MOVP    K3 D1508
      MPP
      ZP.PSTRT4 U1 D1506 M2117  ; 位置4
357   LDD=    D1100 D2200  ; 6#当前值 / 1
      OUT     M2800  ; 6#  2#装产品轴在原点位置
361   LDD=    D1100 D2200  ; 6#当前值 / 1
      OUT     M2801  ; 6#  2#装产品轴在位置1
365   LDD=    D1100 D2202  ; 6#当前值 / 2
      OUT     M2802  ; 6#  2#装产品轴在位置2
369   LDD=    D1100 D2204  ; 6#当前值 / 3
      OUT     M2803  ; 6#  2#装产品轴在位置3
373   LDD=    D1100 D2206  ; 6#当前值 / 4
      OUT     M2804  ; 6#  2#装产品轴在位置4
377   LDD=    D1100 D2208  ; 6#当前值 / 5
      OUT     M2805  ; 6#  2#装产品轴在位置5
381   LDD=    D1100 D2210  ; 6#当前值 / 6
      OUT     M2806  ; 6#  2#装产品轴在位置6
385   LD      M20  ; 手动状态
      MPS
      LD      M2105
      OR      M2106
      ANB
      ANI     X1F  ; 轴4 busy
      SET     M2107
      MRD
      ANI     M2105
      ANI     M2106
      RST     M2107
      MRD
      AND     M2105
      AND     M2107
      ANI     Y1F  ; 轴4反向JOG
      OUT     Y1E  ; 轴4正向JOG
      MPP
      AND     M2106
      AND     M2107
      ANI     Y1E  ; 轴4正向JOG
      OUT     Y1F  ; 轴4反向JOG
406   END
END_PROGRAM

PROGRAM 7#
0     LD      M20  ; 手动状态
      AND     SM400
      MPS
      AND     M2122  ; 7#手动折料
      PLS     M2130  ; 7#手动折料
      MRD
      AND     M2123  ; 7#手动旋转
      PLS     M2131  ; 7#手动旋转
      MRD
      LDP     M1600  ; 7#  3#移载座轴位置1（手动）
      ANDD<>  D1120 D2240  ; 7#当前值 / 1
      LDP     M2124  ; 7#ABS手
      ANDD=   D1120 D2258  ; 7#当前值 / 10
      ORB
      ANB
      PLS     M1630  ; 7#  3#移载座轴位置1（手动）
      MRD
      LDP     M1601  ; 7#  3#移载座轴位置2（手动）
      ANDD<>  D1120 D2242  ; 7#当前值 / 2
      LDP     M2124  ; 7#ABS手
      ANDD=   D1120 D2240  ; 7#当前值 / 1
      ORB
      ANB
      PLS     M1631  ; 7#  3#移载座轴位置2（手动）
      MRD
      LDP     M1602  ; 7#  3#移载座轴位置3（手动）
      ANDD<>  D1120 D2244  ; 7#当前值 / 3
      LDP     M2124  ; 7#ABS手
      ANDD=   D1120 D2242  ; 7#当前值 / 2
      ORB
      ANB
      PLS     M1632  ; 7#  3#移载座轴位置3（手动）
      MRD
      LDP     M1603  ; 7#  3#移载座轴位置4（手动）
      ANDD<>  D1120 D2246  ; 7#当前值 / 4
      LDP     M2124  ; 7#ABS手
      ANDD=   D1120 D2244  ; 7#当前值 / 3
      ORB
      ANB
      PLS     M1633  ; 7#  3#移载座轴位置4（手动）
      MRD
      LDP     M1604  ; 7#  3#移载座轴位置5（手动）
      ANDD<>  D1120 D2248  ; 7#当前值 / 5
      LDP     M2124  ; 7#ABS手
      ANDD=   D1120 D2246  ; 7#当前值 / 4
      ORB
      ANB
      PLS     M1634  ; 7#  3#移载座轴位置5（手动）
      MRD
      LDP     M1605  ; 7#  3#移载座轴位置6（手动）
      ANDD<>  D1120 D2250  ; 7#当前值 / 6
      LDP     M2124  ; 7#ABS手
      ANDD=   D1120 D2248  ; 7#当前值 / 5
      ORB
      ANB
      PLS     M1635  ; 7#  3#移载座轴位置6（手动）
      MRD
      LDP     M1606  ; 7#  3#位置7
      ANDD<>  D1120 D2252  ; 7#当前值 / 7
      LDP     M2124  ; 7#ABS手
      ANDD=   D1120 D2250  ; 7#当前值 / 6
      ORB
      ANB
      PLS     M1636  ; 7#  3#位置7
      MRD
      LDP     M1607  ; 7#  3#位置8
      ANDD<>  D1120 D2254  ; 7#当前值 / 8
      LDP     M2124  ; 7#ABS手
      ANDD=   D1120 D2252  ; 7#当前值 / 7
      ORB
      ANB
      PLS     M1637  ; 7#  3#位置8
      MRD
      LDP     M1608  ; 7#  3#位置9
      ANDD<>  D1120 D2256  ; 7#当前值 / 9
      LDP     M2124  ; 7#ABS手
      ANDD=   D1120 D2254  ; 7#当前值 / 8
      ORB
      ANB
      PLS     M1638  ; 7#  3#位置9
      MPP
      LDP     M1609  ; 7#  3#位置10
      ANDD<>  D1120 D2258  ; 7#当前值 / 10
      LDP     M2124  ; 7#ABS手
      ANDD=   D1120 D2256  ; 7#当前值 / 9
      ORB
      ANB
      PLS     M1639  ; 7#  3#位置10
140   LD      SM400
      MPS
      ANI     M4515  ; 产品选择按钮（OFF为产品1）
      DMOV    D6300 D2240  ; 3#产品1移载座位置1
      MRD
      AND     M4515  ; 产品选择按钮（OFF为产品1）
      DMOV    D6400 D2240  ; 3#产品2移载座位置1
      MRD
      ANI     M4515  ; 产品选择按钮（OFF为产品1）
      DMOV    D6302 D2242  ; 3#产品1移载座位置2
      MRD
      AND     M4515  ; 产品选择按钮（OFF为产品1）
      DMOV    D6402 D2242  ; 3#产品2移载座位置2
      MRD
      ANI     M4515  ; 产品选择按钮（OFF为产品1）
      DMOV    D6304 D2244  ; 3#产品1移载座位置3
      MRD
      AND     M4515  ; 产品选择按钮（OFF为产品1）
      DMOV    D6404 D2244  ; 3#产品2移载座位置3
      MRD
      ANI     M4515  ; 产品选择按钮（OFF为产品1）
      DMOV    D6306 D2246  ; 3#产品1移载座位置4
      MRD
      AND     M4515  ; 产品选择按钮（OFF为产品1）
      DMOV    D6406 D2246  ; 3#产品2移载座位置4
      MRD
      ANI     M4515  ; 产品选择按钮（OFF为产品1）
      DMOV    D6308 D2248  ; 3#产品1移载座位置5
      MPP
      AND     M4515  ; 产品选择按钮（OFF为产品1）
      DMOV    D6408 D2248  ; 3#产品2移载座位置5
181   LD      SM400
      MPS
      ANI     M4516
      DMOV    D6310 D2250  ; 3#产品1移载座位置6
      MRD
      AND     M4516
      DMOV    D6410 D2250  ; 3#产品2移载座位置6
      MRD
      ANI     M4516
      DMOV    D6312 D2252  ; 3#产品1移载座位置7
      MRD
      AND     M4516
      DMOV    D6412 D2252  ; 3#产品2移载座位置7
      MRD
      ANI     M4516
      DMOV    D6314 D2254  ; 3#产品1移载座位置8
      MRD
      AND     M4516
      DMOV    D6414 D2254  ; 3#产品2移载座位置8
      MRD
      ANI     M4516
      DMOV    D6316 D2256  ; 3#产品1移载座位置9
      MRD
      AND     M4516
      DMOV    D6416 D2256  ; 3#产品2移载座位置9
      MRD
      ANI     M4516
      DMOV    D6318 D2258  ; 3#产品1移载座位置10
      MPP
      AND     M4516
      DMOV    D6418 D2258
222   LDI     M2561
      AND     M2861  ; 9#  3#装产品轴在位置1
      AND     SM400
      MPS
      LDP     M2132  ; 7#折料
      ORP     M2130  ; 7#手动折料
      ANB
      *       D1130 D1128 D1138  ; 7#每转脉冲 / 7#次数 / 7#折料位置
      MRD
      LDP     M2133  ; 7#INC
      ORP     M2131  ; 7#手动旋转
      ANB
      DMOV    D1132 D1138  ; 7#INC旋转位置
      MRD
      LDP     M1660  ; 7#  3#移载座轴位置1（自动）
      ORP     M1630  ; 7#  3#移载座轴位置1（手动）
      ANB
      DMOV    D2240 D1530  ; 移位置
      MRD
      LDP     M1661  ; 7#  3#移载座轴位置2（自动）
      ORP     M1631  ; 7#  3#移载座轴位置2（手动）
      ANB
      DMOV    D2242 D1530
      MRD
      LDP     M1662  ; 7#  3#移载座轴位置3（自动）
      ORP     M1632  ; 7#  3#移载座轴位置3（手动）
      ANB
      DMOV    D2244 D1530
      MRD
      LDP     M1663  ; 7#  3#移载座轴位置4（自动）
      ORP     M1633  ; 7#  3#移载座轴位置4（手动）
      ANB
      DMOV    D2246 D1530
      MRD
      LDP     M1664  ; 7#  3#移载座轴位置5（自动）
      ORP     M1634  ; 7#  3#移载座轴位置5（手动）
      ANB
      DMOV    D2248 D1530
      MRD
      LDP     M1665  ; 7#  3#移载座轴位置6（自动）
      ORP     M1635  ; 7#  3#移载座轴位置6（手动）
      ANB
      DMOV    D2250 D1530
      MRD
      LDP     M1666  ; 7#  3#位置7
      ORP     M1636  ; 7#  3#位置7
      ANB
      DMOV    D2252 D1530
      MRD
      LDP     M1667  ; 7#  3#位置8
      ORP     M1637  ; 7#  3#位置8
      ANB
      DMOV    D2254 D1530
      MRD
      LDP     M1668  ; 7#  3#位置9
      ORP     M1638  ; 7#  3#位置9
      ANB
      DMOV    D2256 D1530
      MPP
      LDP     M1669  ; 7#  3#位置10
      ORP     M1639  ; 7#  3#位置10
      ANB
      DMOV    D2258 D1530
298   LD      SM400
      MPS
      AND     M20  ; 手动状态
      DMOV    D1124 D1532  ; 7#手动频率 / 7#频率
      MRD
      ANI     M20  ; 手动状态
      DMOV    D1126 D1532  ; 7#自动速度
      MPP
      DMOV    D1532 U3\G2004
      DMOV    D1122 U3\G2006  ; 7#原点位置
      DMOV    D1532 U3\G2014
      DMOV    D1138 U3\G2016
      DMOV    D1532 U3\G2024
      DMOV    D1530 U3\G2026
      DMOV    D1532 U3\G2034
      DMOV    D1244 U3\G2036
340   LDP     T160
      LD      M20  ; 手动状态
      ANDP    M2121  ; 7#复原
      ORB
      LD      T160
      ANDP    M20  ; 手动状态
      AND     M17  ; 急停（外部按钮）
      ORB
      ORF     M20  ; 手动状态
      ORF     M2120  ; 7#伺服ON
      BKRST   B560 K10
      MPS
      AND     B56F
      SET     B560
      MPP
      LDP     T160
      OR      M2121  ; 7#复原
      ORF     M2120  ; 7#伺服ON
      ANB
      SET     M57  ; 3#移载座上电回原点用
362   LD=     K0 K3B560
      OUT     B56F
      INV
      OUT     M2561
368   LD      B560
      MPS
      LDI     M2820  ; 7#  3#移载座轴在原点位置
      OR      M57  ; 3#移载座上电回原点用
      ANB
      AND     M632  ; 3#挡载座原点
      ANI     M4023  ; 3#定载座1（输出）
      ANI     M4024  ; 3#定载座2（输出）
      ANI     M4025  ; 3#压产品（输出）
      AND     M633  ; 3#定载座1原点
      AND     M634  ; 3#定载座2原点
      AND     M635  ; 3#压产品气缸原点
      SET     B561
      MPP
      AND     M2820  ; 7#  3#移载座轴在原点位置
      ANI     M57  ; 3#移载座上电回原点用
      RST     B560
385   LD      B561
      RST     B560
      RST     M57  ; 3#移载座上电回原点用
      MOV     K9001 D1522
      MOV     K0 U3\G1521
      ZP.PSTRT1 "U3" D1520 M2135  ; 原点完成
      SET     B562
404   LD      B562
      RST     B561
      AND     M2135  ; 原点完成
      MOV     K1 U3\G1521
      SET     B563
412   LD      B563
      RST     B562
      OUT     T163 K2
      AND     T163
      SET     B564
420   LD      B564
      RST     B563
      PLS     M2134  ; 回原点定位
      ANI     M2134  ; 回原点定位
      SET     B565
426   LD      B565
      RST     B564
      AND     M2137
      SET     B566
430   LD      B566
      RST     B565
      DMOV    K0 U3\G1506
      MOV     K9003 U3\G1500
      MPS
      ANDP    B566
      SET     Y40  ; 2#轴1定位启动
      MPP
      RST     B566
446   LD      Y40  ; 2#轴1定位启动
      OUT     T164 K2
      AND     T164
      RST     Y40  ; 2#轴1定位启动
453   LD      M2134  ; 回原点定位
      OR      M2132  ; 7#折料
      OR      M2133  ; 7#INC
      OR      M2130  ; 7#手动折料
      OR      M2131  ; 7#手动旋转
      OR<>    K0 K2M1660  ; 7#  3#移载座轴位置1（自动）
      OR      M1668  ; 7#  3#位置9
      OR      M1669  ; 7#  3#位置10
      OR<>    K0 K4M1630  ; 7#  3#移载座轴位置1（手动）
      MPS
      AND     M2134  ; 回原点定位
      MOVP    K1 D1528
      MRD
      LD      M2132  ; 7#折料
      OR      M2133  ; 7#INC
      OR      M2130  ; 7#手动折料
      OR      M2131  ; 7#手动旋转
      ANB
      MOVP    K2 D1528
      MRD
      LD<>    K0 K2M1660  ; 7#  3#移载座轴位置1（自动）
      OR      M1668  ; 7#  3#位置9
      OR      M1669  ; 7#  3#位置10
      OR<>    K0 K4M1630  ; 7#  3#移载座轴位置1（手动）
      ANB
      MOVP    K3 D1528
      MPP
      ZP.PSTRT1 U3 D1526 M2137
499   LDD=    D1120 D2240  ; 7#当前值 / 1
      OUT     M2820  ; 7#  3#移载座轴在原点位置
503   LDD=    D1120 D2240  ; 7#当前值 / 1
      OUT     M2821  ; 7#  3#移载座轴在位置1
507   LDD=    D1120 D2242  ; 7#当前值 / 2
      OUT     M2822  ; 7#  3#移载座轴在位置2
511   LDD=    D1120 D2244  ; 7#当前值 / 3
      OUT     M2823  ; 7#  3#移载座轴在位置3
515   LDD=    D1120 D2246  ; 7#当前值 / 4
      OUT     M2824  ; 7#  3#移载座轴在位置4
519   LDD=    D1120 D2248  ; 7#当前值 / 5
      OUT     M2825  ; 7#  3#移载座轴在位置5
523   LDD=    D1120 D2250  ; 7#当前值 / 6
      OUT     M2826  ; 7#  3#移载座轴在位置6
527   LDD=    D1120 D2252  ; 7#当前值 / 7
      OUT     M2827  ; 7#  3#移载座轴在位置7
531   LDD=    D1120 D2254  ; 7#当前值 / 8
      OUT     M2828  ; 7#  3#移载座轴在位置8
535   LDD=    D1120 D2256  ; 7#当前值 / 9
      OUT     M2829  ; 7#  3#移载座轴在位置9
539   LDD=    D1120 D2258  ; 7#当前值 / 10
      OUT     M2830  ; 7#  3#移载座轴在位置10
543   LD      M20  ; 手动状态
      MPS
      LD      M2125
      OR      M2126
      ANB
      ANI     X3C  ; 轴1 busy
      SET     M2127
      MRD
      ANI     M2125
      ANI     M2126
      RST     M2127
      MRD
      AND     M2125
      AND     M2127
      ANI     Y39  ; 2#轴1反向JOG
      OUT     Y38  ; 2#轴1正向JOG
      MPP
      AND     M2126
      AND     M2127
      ANI     Y38  ; 2#轴1正向JOG
      OUT     Y39  ; 2#轴1反向JOG
564   END
END_PROGRAM

PROGRAM 8#
0     LD      M20  ; 手动状态
      AND     SM400
      MPS
      AND     M2142  ; 8#手动折料
      PLS     M2150  ; 8#手动折料
      MRD
      AND     M2143  ; 8#手动旋转
      PLS     M2151  ; 8#手动旋转
      MRD
      LDP     M1700  ; 8#   3#出载带移载位置1（手动）
      ANDD<>  D1140 D2280  ; 8#当前值 / 1
      LDP     M2144  ; 8#ABS手
      ANDD=   D1140 D2282  ; 8#当前值 / 2
      ORB
      ANB
      ANI     M4028  ; 3#取产品上下（输出）
      AND     M638  ; 3#取产品气缸原点
      PLS     M1730  ; 8#  3#出载带移载位置1（手动）
      MRD
      LDP     M1701  ; 8#   3#出载带移载位置2（手动）
      ANDD<>  D1140 D2282  ; 8#当前值 / 2
      LDP     M2144  ; 8#ABS手
      ANDD=   D1140 D2286  ; 8#当前值 / 4
      ORB
      ANB
      ANI     M4028  ; 3#取产品上下（输出）
      AND     M638  ; 3#取产品气缸原点
      PLS     M1731  ; 8#  3#出载带移载位置2（手动）
      MRD
      LDP     M1702  ; 8#   3#出载带移载位置3（手动）
      ANDD<>  D1140 D2284  ; 8#当前值 / 3
      LDP     M2144  ; 8#ABS手
      ANDD=   D1140 D2280  ; 8#当前值 / 1
      ORB
      ANB
      ANI     M4028  ; 3#取产品上下（输出）
      AND     M638  ; 3#取产品气缸原点
      PLS     M1732  ; 8#  3#出载带移载位置3（手动）
      MRD
      LDP     M1703  ; 8#   3#出载带移载位置4（手动）
      ANDD<>  D1140 D2286  ; 8#当前值 / 4
      LDP     M2144  ; 8#ABS手
      ANDD=   D1140 D2284  ; 8#当前值 / 3
      ORB
      ANB
      ANI     M4028  ; 3#取产品上下（输出）
      AND     M638  ; 3#取产品气缸原点
      PLS     M1733  ; 8#  3#出载带移载位置4（手动）
      MRD
      LDP     M1704  ; 8#   3#出载带移载位置5（手动）
      ANDD<>  D1140 D2288  ; 8#当前值 / 5
      LDP     M2144  ; 8#ABS手
      ANDD=   D1140 D2286  ; 8#当前值 / 4
      ORB
      ANB
      ANI     M4028  ; 3#取产品上下（输出）
      AND     M638  ; 3#取产品气缸原点
      PLS     M1734  ; 8#  3#出载带移载位置5（手动）
      MPP
      LDP     M1705  ; 8#   3#出载带移载位置6（手动）
      ANDD<>  D1140 D2290  ; 8#当前值 / 6
      LDP     M2144  ; 8#ABS手
      ANDD=   D1140 D2288  ; 8#当前值 / 5
      ORB
      ANB
      ANI     M4028  ; 3#取产品上下（输出）
      AND     M638  ; 3#取产品气缸原点
      PLS     M1735  ; 8#  3#出载带移载位置6（手动）
100   LDI     M2571  ; 8#复原中
      AND     SM400
      MPS
      LDP     M2152  ; 8#折料
      ORP     M2150  ; 8#手动折料
      ANB
      *       D1150 D1148 D1158  ; 8#每转脉冲 / 8#次数 / 8#折料位置
      MRD
      LDP     M2153  ; 8#INC
      ORP     M2151  ; 8#手动旋转
      ANB
      DMOV    D1152 D1158  ; 8#INC旋转位置
      MRD
      LDP     M1760  ; 8#  3#出载带移载位置1（自动）
      ORP     M1730  ; 8#  3#出载带移载位置1（手动）
      ANB
      DMOV    D2280 D1550  ; 移位置
      MRD
      LDP     M1761  ; 8#  3#出载带移载位置2（自动）
      ORP     M1731  ; 8#  3#出载带移载位置2（手动）
      ANB
      DMOV    D2282 D1550
      MRD
      LDP     M1762  ; 8#  3#出载带移载位置3（自动）
      ORP     M1732  ; 8#  3#出载带移载位置3（手动）
      ANB
      DMOV    D2284 D1550
      MRD
      LDP     M1763  ; 8#  3#出载带移载位置4（自动）
      ORP     M1733  ; 8#  3#出载带移载位置4（手动）
      ANB
      DMOV    D2286 D1550
      MRD
      LDP     M1764  ; 8#  3#出载带移载位置5（自动）
      ORP     M1734  ; 8#  3#出载带移载位置5（手动）
      ANB
      DMOV    D2288 D1550
      MPP
      LDP     M1765  ; 8#  3#出载带移载位置6（自动）
      ORP     M1735  ; 8#  3#出载带移载位置6（手动）
      ANB
      DMOV    D2290 D1550
151   LD      SM400
      MPS
      AND     M20  ; 手动状态
      DMOV    D1144 D1552  ; 8#手动频率 / 运行速度
      MRD
      ANI     M20  ; 手动状态
      DMOV    D1146 D1552  ; 8#自动速度
      MPP
      DMOV    D1552 U3\G8004
      DMOV    D1142 U3\G8006  ; 8#原点位置
      DMOV    D1552 U3\G8014
      DMOV    D1158 U3\G8016
      DMOV    D1552 U3\G8024
      DMOV    D1550 U3\G8026
      DMOV    D1552 U3\G8034
      DMOV    D1244 U3\G8036
193   LDP     T170
      LD      M20  ; 手动状态
      ANDP    M2141  ; 8#复原
      ORB
      LD      T170
      ANDP    M20  ; 手动状态
      ORF     M20  ; 手动状态
      ORF     M2140  ; 8#伺服ON
      AND     M17  ; 急停（外部按钮）
      ORB
      BKRST   B570 K10
      MPS
      AND     B57F
      SET     B570
      MPP
      LDP     T170
      OR      M2141  ; 8#复原
      ORF     M2140  ; 8#伺服ON
      ANB
      SET     M58  ; 3#出载带移载上电回原点用
215   LD=     K0 K3B570
      OUT     B57F
      INV
      OUT     M2571  ; 8#复原中
221   LD      B570
      MPS
      LDI     M2840  ; 8#  3#出载带移载在原点位置
      OR      M58  ; 3#出载带移载上电回原点用
      ANB
      ANI     M4028  ; 3#取产品上下（输出）
      AND     M638  ; 3#取产品气缸原点
      SET     B571
      MPP
      AND     M2840  ; 8#  3#出载带移载在原点位置
      ANI     M58  ; 3#出载带移载上电回原点用
      RST     B570
233   LD      B571
      RST     B570
      RST     M58  ; 3#出载带移载上电回原点用
      MOV     K9001 D1542
      MOV     K0 U3\G1621
      ZP.PSTRT2 "U3" D1540 M2155  ; 原点完成
      SET     B572
252   LD      B572
      RST     B571
      AND     M2155  ; 原点完成
      MOV     K1 U3\G1621
      SET     B573
260   LD      B573
      RST     B572
      OUT     T173 K2
      AND     T173
      SET     B574
268   LD      B574
      RST     B573
      PLS     M2154  ; 回原点定位
      ANI     M2154  ; 回原点定位
      SET     B575
274   LD      B575
      RST     B574
      AND     M2157  ; 点胶B面X轴定位完成标志
      SET     B576
278   LD      B576
      RST     B575
      DMOV    K0 U3\G1606
      MOV     K9003 U3\G1600
      MPS
      ANDP    B576
      SET     Y41  ; 2#轴2定位启动
      MPP
      RST     B576
294   LD      Y41  ; 2#轴2定位启动
      OUT     T174 K2
      AND     T174
      RST     Y41  ; 2#轴2定位启动
301   LD      M2154  ; 回原点定位
      OR      M2152  ; 8#折料
      OR      M2153  ; 8#INC
      OR      M2150  ; 8#手动折料
      OR      M2151  ; 8#手动旋转
      OR<>    K0 K2M1760  ; 8#  3#出载带移载位置1（自动）
      OR<>    K0 K4M1730  ; 8#  3#出载带移载位置1（手动）
      MPS
      AND     M2154  ; 回原点定位
      MOVP    K1 D1548
      MRD
      LD      M2152  ; 8#折料
      OR      M2153  ; 8#INC
      OR      M2150  ; 8#手动折料
      OR      M2151  ; 8#手动旋转
      ANB
      MOVP    K2 D1548
      MRD
      LD<>    K0 K2M1760  ; 8#  3#出载带移载位置1（自动）
      OR<>    K0 K4M1730  ; 8#  3#出载带移载位置1（手动）
      ANB
      MOVP    K3 D1548
      MPP
      ANI     M4028  ; 3#取产品上下（输出）
      AND     M638  ; 3#取产品气缸原点
      ZP.PSTRT2 U3 D1546 M2157
345   LDD=    D1140 D2280  ; 8#当前值 / 1
      OUT     M2840  ; 8#  3#出载带移载在原点位置
349   LDD=    D1140 D2280  ; 8#当前值 / 1
      OUT     M2841  ; 8#  3#出载带移载在位置1
353   LDD=    D1140 D2282  ; 8#当前值 / 2
      OUT     M2842  ; 8#  3#出载带移载在位置2
357   LDD=    D1140 D2284  ; 8#当前值 / 3
      OUT     M2843  ; 8#  3#出载带移载在位置3
361   LDD=    D1140 D2286  ; 8#当前值 / 4
      OUT     M2844  ; 8#  3#出载带移载在位置4
365   LDD=    D1140 D2288  ; 8#当前值 / 5
      OUT     M2845  ; 8#  3#出载带移载在位置5
369   LD      M20  ; 手动状态
      MPS
      LD      M2145
      OR      M2146
      ANB
      ANI     X3D  ; 轴2 busy
      SET     M2147
      MRD
      ANI     M2145
      ANI     M2146
      RST     M2147
      MRD
      AND     M2145
      AND     M2147
      ANI     Y3B  ; 2#轴2反向JOG
      OUT     Y3A  ; 2#轴2正向JOG
      MPP
      AND     M2146
      AND     M2147
      ANI     Y3A  ; 2#轴2正向JOG
      OUT     Y3B  ; 2#轴2反向JOG
390   END
END_PROGRAM

PROGRAM 9#
0     LD      M20  ; 手动状态
      AND     SM400
      MPS
      AND     M2162  ; 9#手动折料
      PLS     M2170  ; 9#手动折料
      MRD
      AND     M2163  ; 09#手动旋转
      PLS     M2171  ; 9#手动旋转
      MRD
      LDP     M1800  ; 9#   3#装产品轴位置1（手动）
      ANDD<>  D1160 D2320  ; 9#当前值 / 1
      LDP     M2164  ; 9#ABS手
      ANDD=   D1160 D2322  ; 9#当前值 / 2
      ORB
      ANB
      ANI     M4030  ; 3#推产品（输出）
      ANI     M4031  ; 3#挡产品（输出）
      AND     M640  ; 3#推产品气缸原点
      AND     M641  ; 3#挡产品气缸原点
      PLS     M1830  ; 9#   3#装产品轴位置1（手动）
      MRD
      LDP     M1801  ; 9#   3#装产品轴位置2（手动）
      ANDD<>  D1160 D2322  ; 9#当前值 / 2
      LDP     M2164  ; 9#ABS手
      ANDD=   D1160 D2326  ; 9#当前值 / 4
      ORB
      ANB
      ANI     M4030  ; 3#推产品（输出）
      ANI     M4031  ; 3#挡产品（输出）
      AND     M640  ; 3#推产品气缸原点
      AND     M641  ; 3#挡产品气缸原点
      PLS     M1831  ; 9#   3#装产品轴位置2（手动）
      MRD
      LDP     M1802  ; 9#   3#装产品轴位置3（手动）
      ANDD<>  D1160 D2324  ; 9#当前值 / 3
      LDP     M2164  ; 9#ABS手
      ANDD=   D1160 D2320  ; 9#当前值 / 1
      ORB
      ANB
      ANI     M4030  ; 3#推产品（输出）
      ANI     M4031  ; 3#挡产品（输出）
      AND     M640  ; 3#推产品气缸原点
      AND     M641  ; 3#挡产品气缸原点
      PLS     M1832  ; 9#   3#装产品轴位置3（手动）
      MRD
      LDP     M1803  ; 9#   3#装产品轴位置4（手动）
      ANDD<>  D1160 D2326  ; 9#当前值 / 4
      LDP     M2164  ; 9#ABS手
      ANDD=   D1160 D2324  ; 9#当前值 / 3
      ORB
      ANB
      ANI     M4030  ; 3#推产品（输出）
      ANI     M4031  ; 3#挡产品（输出）
      AND     M640  ; 3#推产品气缸原点
      AND     M641  ; 3#挡产品气缸原点
      PLS     M1833  ; 9#   3#装产品轴位置4（手动）
      MRD
      LDP     M1804  ; 9#   3#装产品轴位置5（手动）
      ANDD<>  D1160 D2328  ; 9#当前值 / 5
      LDP     M2164  ; 9#ABS手
      ANDD=   D1160 D2326  ; 9#当前值 / 4
      ORB
      ANB
      ANI     M4030  ; 3#推产品（输出）
      ANI     M4031  ; 3#挡产品（输出）
      AND     M640  ; 3#推产品气缸原点
      AND     M641  ; 3#挡产品气缸原点
      PLS     M1834  ; 9#   3#装产品轴位置5（手动）
      MPP
      LDP     M1805  ; 9#   3#装产品轴位置6（手动）
      ANDD<>  D1160 D2330  ; 9#当前值 / 6
      LDP     M2164  ; 9#ABS手
      ANDD=   D1160 D2328  ; 9#当前值 / 5
      ORB
      ANB
      ANI     M4030  ; 3#推产品（输出）
      ANI     M4031  ; 3#挡产品（输出）
      AND     M640  ; 3#推产品气缸原点
      AND     M641  ; 3#挡产品气缸原点
      PLS     M1835  ; 9#   3#装产品轴位置6（手动）
112   LDI     M2581  ; 9#复原中
      AND     SM400
      MPS
      LDP     M2172  ; 9#折料
      ORP     M2170  ; 9#手动折料
      ANB
      *       D1170 D1168 D1178  ; 9#每转脉冲 / 9#次数 / 9#折料位置
      MRD
      LDP     M2173  ; 9#INC
      ORP     M2171  ; 9#手动旋转
      ANB
      DMOV    D1172 D1178  ; 9#INC旋转位置
      MRD
      LDP     M1860  ; 9#   3#装产品轴位置1（自动）
      ORP     M1830  ; 9#   3#装产品轴位置1（手动）
      ANB
      DMOV    D2320 D1570  ; 移位置
      MRD
      LDP     M1861  ; 9#   3#装产品轴位置2（自动）
      ORP     M1831  ; 9#   3#装产品轴位置2（手动）
      ANB
      DMOV    D2322 D1570
      MRD
      LDP     M1862  ; 9#   3#装产品轴位置3（自动）
      ORP     M1832  ; 9#   3#装产品轴位置3（手动）
      ANB
      DMOV    D2324 D1570
      MRD
      LDP     M1863  ; 9#   3#装产品轴位置4（自动）
      ORP     M1833  ; 9#   3#装产品轴位置4（手动）
      ANB
      DMOV    D2326 D1570
      MRD
      LDP     M1864  ; 9#   3#装产品轴位置5（自动）
      ORP     M1834  ; 9#   3#装产品轴位置5（手动）
      ANB
      DMOV    D2328 D1570
      MPP
      LDP     M1865  ; 9#   3#装产品轴位置6（自动）
      ORP     M1835  ; 9#   3#装产品轴位置6（手动）
      ANB
      DMOV    D2330 D1570
163   LD      SM400
      MPS
      AND     M20  ; 手动状态
      DMOV    D1164 D1572  ; 9#手动频率 / 运行速度
      MRD
      ANI     M20  ; 手动状态
      DMOV    D1166 D1572  ; 9#自动速度
      MPP
      DMOV    D1572 U3\G14004
      DMOV    D1162 U3\G14006  ; 9#原点位置
      DMOV    D1572 U3\G14014
      DMOV    D1178 U3\G14016
      DMOV    D1572 U3\G14024
      DMOV    D1570 U3\G14026
      DMOV    D1572 U3\G14034
      DMOV    D1244 U3\G14036
205   LDP     T180
      LD      M20  ; 手动状态
      ANDP    M2161  ; 9#复原
      ORB
      LD      T180
      ANDP    M20  ; 手动状态
      ORF     M20  ; 手动状态
      ORF     M2160  ; 9#伺服ON
      AND     M17  ; 急停（外部按钮）
      ORB
      BKRST   B580 K10
      MPS
      AND     B58F
      SET     B580
      MPP
      LDP     T180
      OR      M2161  ; 9#复原
      ORF     M2160  ; 9#伺服ON
      ANB
      SET     M59  ; 3#装产品上电回原点用
227   LD=     K0 K3B580
      OUT     B58F
      INV
      OUT     M2581  ; 9#复原中
233   LD      B580
      MPS
      LDI     M2860  ; 9#  3#装产品轴在原点位置
      OR      M59  ; 3#装产品上电回原点用
      ANB
      ANI     M4030  ; 3#推产品（输出）
      ANI     M4031  ; 3#挡产品（输出）
      AND     M640  ; 3#推产品气缸原点
      AND     M641  ; 3#挡产品气缸原点
      SET     B581
      MPP
      AND     M2860  ; 9#  3#装产品轴在原点位置
      ANI     M59  ; 3#装产品上电回原点用
      RST     B580
247   LD      B581
      RST     B580
      RST     M59  ; 3#装产品上电回原点用
      MOV     K9001 D1562
      MOV     K0 U3\G1721
      ZP.PSTRT3 "U3" D1560 M2175  ; 原点完成
      SET     B582
266   LD      B582
      RST     B581
      AND     M2175  ; 原点完成
      MOV     K1 U3\G1721
      SET     B583
274   LD      B583
      RST     B582
      OUT     T183 K2
      AND     T183
      SET     B584
282   LD      B584
      RST     B583
      PLS     M2174  ; 回原点定位
      ANI     M2174  ; 回原点定位
      SET     B585
288   LD      B585
      RST     B584
      AND     M2177
      SET     B586
292   LD      B586
      RST     B585
      DMOV    K0 U3\G1706
      MOV     K9003 U3\G1700
      MPS
      ANDP    B586
      SET     Y42  ; 2#轴+3定位启动
      MPP
      RST     B586
308   LD      Y42  ; 2#轴+3定位启动
      OUT     T184 K2
      AND     T184
      RST     Y42  ; 2#轴+3定位启动
315   LD      M2174  ; 回原点定位
      OR      M2172  ; 9#折料
      OR      M2173  ; 9#INC
      OR      M2170  ; 9#手动折料
      OR      M2171  ; 9#手动旋转
      OR<>    K0 K2M1860  ; 9#   3#装产品轴位置1（自动）
      OR<>    K0 K4M1830  ; 9#   3#装产品轴位置1（手动）
      MPS
      AND     M2174  ; 回原点定位
      MOVP    K1 D1568
      MRD
      LD      M2172  ; 9#折料
      OR      M2173  ; 9#INC
      OR      M2170  ; 9#手动折料
      OR      M2171  ; 9#手动旋转
      ANB
      MOVP    K2 D1568
      MRD
      LD<>    K0 K2M1860  ; 9#   3#装产品轴位置1（自动）
      OR<>    K0 K4M1830  ; 9#   3#装产品轴位置1（手动）
      ANB
      MOVP    K3 D1568
      MPP
      ZP.PSTRT3 U3 D1566 M2177
357   LDD=    D1160 D2320  ; 9#当前值 / 1
      OUT     M2860  ; 9#  3#装产品轴在原点位置
361   LDD=    D1160 D2320  ; 9#当前值 / 1
      OUT     M2861  ; 9#  3#装产品轴在位置1
365   LDD=    D1160 D2322  ; 9#当前值 / 2
      OUT     M2862  ; 9#  3#装产品轴在位置2
369   LDD=    D1160 D2324  ; 9#当前值 / 3
      OUT     M2863  ; 9#  3#装产品轴在位置3
373   LDD=    D1160 D2326  ; 9#当前值 / 4
      OUT     M2864  ; 9#  3#装产品轴在位置4
377   LDD=    D1160 D2328  ; 9#当前值 / 5
      OUT     M2865  ; 9#  3#装产品轴在位置5
381   LD      M20  ; 手动状态
      MPS
      LD      M2165
      OR      M2166
      ANB
      ANI     X3E  ; 轴3 busy
      SET     M2167
      MRD
      ANI     M2165
      ANI     M2166
      RST     M2167
      MRD
      AND     M2165
      AND     M2167
      ANI     Y3D  ; 2#轴3反向JOG
      OUT     Y3C  ; 2#轴3正向JOG
      MPP
      AND     M2166
      AND     M2167
      ANI     Y3C  ; 2#轴3正向JOG
      OUT     Y3D  ; 2#轴3反向JOG
402   END
END_PROGRAM

PROGRAM 初始化及工位控制
0     LD      X100  ; 下挡载座气缸原点
      OUT     M600  ; 下挡载座气缸原点
2     LD      X101  ; 下挡载座气缸终点
      OUT     M800  ; 下挡载座气缸终点
4     LD      X102  ; 卸载座气缸原点
      OUT     M601  ; 卸载座气缸原点
6     LD      X103  ; 卸载座气缸终点
      OUT     M801  ; 卸载座气缸终点
8     LD      X104  ; 载座升降气缸原点
      OUT     M602  ; 载座升降气缸原点
10    LD      X105  ; 载座升降气缸终点
      OUT     M802  ; 载座升降气缸终点
12    LD      X106  ; 1#前挡载座1气缸原点
      OUT     M603  ; 1#前挡载座1气缸原点
14    LD      X107  ; 1#前挡载座1气缸终点
      OUT     M803  ; 1#前挡载座1气缸终点
16    LD      X108  ; 1#挡载座气缸原点
      OUT     M604  ; 1#挡载座气缸原点
18    LD      X109  ; 1#挡载座气缸终点
      OUT     M804  ; 1#挡载座气缸终点
20    LD      X10A  ; 1#定载座1气缸原点
      OUT     M605  ; 1#定载座1气缸原点
22    LD      X10B  ; 1#定载座1气缸终点
      OUT     M805  ; 1#定载座1气缸终点
24    LD      X10C  ; 1#定载座2气缸原点
      OUT     M606  ; 1#定载座2气缸原点
26    LD      X10D  ; 1#定载座2气缸终点
      OUT     M806  ; 1#定载座2气缸终点
28    LD      X10E  ; 2#前挡载座1气缸原点
      OUT     M607  ; 2#前挡载座1气缸原点
30    LD      X10F  ; 2#前挡载座1气缸终点
      OUT     M807  ; 2#前挡载座1气缸终点
32    LD      X110  ; 2#前挡载座2气缸原点
      OUT     M608  ; 2#前挡载座2气缸原点
34    LD      X111  ; 2#前挡载座2气缸终点
      OUT     M808  ; 2#前挡载座2气缸终点
36    LD      X112  ; 2#挡载座气缸原点
      OUT     M609  ; 2#挡载座气缸原点
38    LD      X113  ; 2#挡载座气缸终点
      OUT     M809  ; 2#挡载座气缸终点
40    LD      X114  ; 2#定载座1气缸原点
      OUT     M610  ; 2#定载座1气缸原点
42    LD      X115  ; 2#定载座1气缸终点
      OUT     M810  ; 2#定载座1气缸终点
44    LD      X116  ; 2#定载座2气缸原点
      OUT     M611  ; 2#定载座2气缸原点
46    LD      X117  ; 2#定载座2气缸终点
      OUT     M811  ; 2#定载座2气缸终点
48    LD      X118  ; 2#压产品气缸原点
      OUT     M612  ; 2#压产品气缸原点
50    LD      X119  ; 2#压产品气缸终点
      OUT     M812  ; 2#压产品气缸终点
52    LD      X11A  ; 1#脚踏启动
      OUT     M613  ; 2#压载带1气缸原点
54    LD      X11B  ; 2#压载带1气缸终点
      OUT     M813  ; 2#压载带1气缸终点
56    LD      X11C  ; 2#压载带2气缸原点
      OUT     M614  ; 2#压载带2气缸原点
58    LD      X11D  ; 2#压载带2气缸终点
      OUT     M814  ; 2#压载带2气缸终点
60    LD      X11E  ; 2#取产品上下气缸原点
      OUT     M615  ; 2#取产品上下气缸原点
62    LD      X11F  ; 2#取产品上下气缸终点
      OUT     M815  ; 2#取产品上下终点
64    LD      X120  ; 2#吸产品气缸原点
      OUT     M616  ; 2#吸产品气缸原点
66    LD      X121  ; 2#吸产品气缸终点
      OUT     M816  ; 2#吸产品气缸终点
68    LD      X122  ; 2#推产品气缸原点
      OUT     M617  ; 2#推产品气缸原点
70    LD      X123  ; 2#推产品气缸终点
      OUT     M817  ; 2#推产品气缸终点
72    LD      X124  ; 2#挡产品气缸原点
      OUT     M618  ; 2#挡产品气缸原点
74    LD      X125  ; 2#挡产品气缸终点
      OUT     M818  ; 2#挡产品气缸终点
76    LD      X126  ; 2#夹产品气缸原点
      OUT     M619  ; 2#夹产品气缸原点
78    LD      X127  ; 3#载座满料感应
      OUT     M819  ; 3#载座满料感应
80    LD      X128  ; 2#移载轴伺服报警
      OUT     M620  ; 2#移载轴伺服报警
82    LD      X129  ; 2#出载带移载轴伺服报警
      OUT     M621  ; 2#出载带移载轴伺服报警
84    LD      X12A  ; 2#装产品轴伺服报警
      OUT     M622  ; 2#装产品轴伺服报警
86    LD      X12B  ; 升载座工位载座到位感应
      OUT     M623  ; 升载座工位载座到位感应
88    LD      X12C  ; 1#前挡载座到位感应
      OUT     M624  ; 1#前挡载座到位感应
90    LD      X12D  ; 1#挡载座载座到位感应
      OUT     M625  ; 1#挡载座载座到位感应
92    LD      X12E  ; 2#前挡载座到位感应
      OUT     M626  ; 2#前挡载座到位感应
94    LD      X12F  ; 2#载座满料感应
      OUT     M627  ; 2#载座满料感应
96    LD      X130  ; 2#挡载座到位感应
      OUT     M628  ; 2#挡载座到位感应
98    LD      X131  ; 启动
      OUT     M15  ; 启动（外部按钮）
100   LD      X132  ; 停止
      OUT     M16  ; 停止（外部按钮）
102   LD      X133  ; 急停
      OUT     M17  ; 急停（外部按钮）
104   LD      X13A  ; 3#前挡载座1气缸原点
      OUT     M630  ; 3#前挡载座1原点
106   LD      X13B  ; 3#前挡载座1气缸终点
      OUT     M830  ; 3#前挡载座1终点
108   LD      X13C  ; 3#前挡载座2气缸原点
      OUT     M631  ; 3#前挡载座2原点
110   LD      X13D  ; 3#前挡载座2气缸终点
      OUT     M831  ; 3#前挡载座2终点
112   LD      X144  ; 3#挡载座原点
      OUT     M632  ; 3#挡载座原点
114   LD      X145  ; 3#挡载座终点
      OUT     M832  ; 3#挡载座终点
116   LD      X146  ; 3#定载座1原点
      OUT     M633  ; 3#定载座1原点
118   LD      X147  ; 3#定载座1终点
      OUT     M833  ; 3#定载座1终点
120   LD      X148  ; 3#定载座2原点
      OUT     M634  ; 3#定载座2原点
122   LD      X149  ; 3#定载座2终点
      OUT     M834  ; 3#定载座2终点
124   LD      X14A  ; 3#压产品气缸原点
      OUT     M635  ; 3#压产品气缸原点
126   LD      X14B  ; 3#压产品气缸终点
      OUT     M835  ; 3#压产品气缸终点
128   LD      X14C  ; 3#压载带1气缸原点
      OUT     M636  ; 3#压载带1气缸原点
130   LD      X14D  ; 3#压载带1气缸终点
      OUT     M836  ; 3#压载带1气缸终点
132   LD      X14E  ; 3#压载带2气缸原点
      OUT     M637  ; 3#压载带2气缸原点
134   LD      X14F  ; 3#压载带2气缸终点
      OUT     M837  ; 3#压载带2气缸终点
136   LD      X150  ; 3#取产品气缸原点
      OUT     M638  ; 3#取产品气缸原点
138   LD      X151  ; 3#取产品气缸终点
      OUT     M838  ; 3#取产品气缸终点
140   LD      X152  ; 降载座工位卸载座原点
      OUT     M639  ; 降载座工位卸载座原点
142   LD      X153  ; 降载座工位卸载座终点
      OUT     M839  ; 降载座工位卸载座终点
144   LD      X154  ; 3#推产品气缸原点
      OUT     M640  ; 3#推产品气缸原点
146   LD      X155  ; 3#推产品气缸终点
      OUT     M840  ; 3#推产品气缸终点
148   LD      X156  ; 3#挡产品气缸原点
      OUT     M641  ; 3#挡产品气缸原点
150   LD      X157  ; 3#挡产品气缸终点
      OUT     M841  ; 3#挡产品气缸终点
152   LD      X158  ; 3#吸产品上下终点2
      OUT     M642  ; 3#夹产品气缸原点
154   LD      X159  ; 3#夹产品气缸终点
      OUT     M842  ; 3#夹产品气缸终点
156   LD      X15A  ; 4#挡载座1气缸原点
      OUT     M643  ; 4#挡载座1气缸原点
158   LD      X15B  ; 4#挡载座1气缸终点
      OUT     M843  ; 4#挡载座1气缸终点
160   LD      X15C  ; 4#定载座1气缸原点
      OUT     M644  ; 4#定载座1气缸原点
162   LD      X15D  ; 4#定载座1气缸终点
      OUT     M844  ; 4#定载座1气缸终点
164   LD      X15E  ; 4#挡载座2气缸原点
      OUT     M645  ; 4#挡载座2气缸原点
166   LD      X15F  ; 4#挡载座2气缸终点
      OUT     M845  ; 4#挡载座2气缸终点
168   LD      X160  ; 4#定载座2气缸原点
      OUT     M646  ; 4#定载座2气缸原点
170   LD      X161  ; 4#定载座2气缸终点
      OUT     M846  ; 4#定载座2气缸终点
172   LD      X162  ; 4#定载座3气缸原点
      OUT     M647  ; 4#定载座3气缸原点
174   LD      X163  ; 4#定载座3气缸终点
      OUT     M847  ; 4#定载座3气缸终点
176   LD      X164  ; 4#顶载座气缸原点
      OUT     M648  ; 4#顶载座气缸原点
178   LD      X165  ; 4#顶载座气缸终点
      OUT     M848  ; 4#顶载座气缸终点
180   LD      X166  ; 4#夹产品气缸原点
      OUT     M649  ; 4#夹产品气缸原点
182   LD      X167  ; 4#夹产品气缸终点
      OUT     M849  ; 4#夹产品气缸终点
184   LD      X168  ; 升降气缸原点
      OUT     M650  ; 升降气缸原点
186   LD      X169  ; 升降气缸终点
      OUT     M850  ; 升降气缸终点
188   LD      X178  ; 4#前挡载座1原点
      OUT     M651  ; 4#前挡气缸1原点
190   LD      X179  ; 4#前挡载座1终点
      OUT     M851  ; 4#前挡气缸1终点
192   LD      X134  ; 1#前挡载座2原点
      OUT     M652  ; 1#前挡气缸2原点
194   LD      X135  ; 1#前挡载座2终点
      OUT     M852  ; 1#前挡气缸2终点
196   LD      X16A  ; 3#移载轴伺服报警
      OUT     M660  ; 3#移载轴伺服报警
198   LD      X16B  ; 3#出载带移载轴伺服报警
      OUT     M661  ; 3#出载带移载轴伺服报警
200   LD      X16C  ; 3#装产品轴伺服报警
      OUT     M662  ; 3#装产品轴伺服报警
202   LD      X16D  ; 4#移载座轴报警
      OUT     M663  ; 4#移载座轴报警
204   LD      X16E  ; 4#取产品轴报警
      OUT     M664  ; 4#取产品轴报警
206   LD      X16F  ; 4#入回流焊轴报警
      OUT     M665  ; 4#入回流焊轴报警
208   LD      X170  ; 2#产品检测光纤感应
      OUT     M666  ; 2#产品检测光纤感应
210   LD      X176  ; 4#前挡载座2载座到位感应
      OUT     M672  ; 4#前挡载座载座到位感应
212   LD      X172  ; 3#前挡料2载座到位感应
      OUT     M668  ; 3#前挡料2载座到位感应
214   LD      X173  ; 3#载座到位感应
      OUT     M669  ; 3#载座到位感应
216   LD      X175  ; 3#产品检测光纤感应
      OUT     M670  ; 3#产品检测光纤感应
218   LD      X174  ; 4#前挡载座满料光纤
      OUT     M667  ; 4#前挡载座满料光纤
220   LD      X177  ; 降载座工位载座到位感应
      OUT     M673  ; 降载座工位载座到位感应
222   LD      X17A  ; 4#前挡载座2原点
      OUT     M653  ; 4#前挡气缸2原点
224   LD      X17B  ; 4#前挡载座2终点
      OUT     M853  ; 4#前挡气缸2终点
226   LD      SM402
      BKRST   M500 K500
      BKRST   M300 K200
      BKRST   M3000 K600  ; 下挡载座(手动)
      BKRST   B100 K300  ; 马达原点回归第一步
      SET     B100  ; 马达原点回归第一步
240   LD      B0
      RST     M4000  ; 下挡载座（输出）
      RST     M4001  ; 卸载座（输出）
      ANI     M4001  ; 卸载座（输出）
      AND     M601  ; 卸载座气缸原点
      SET     B1
      RST     B0
247   LD      B1
      RST     M4002  ; 载座升降（输出）
      ANI     M4002  ; 载座升降（输出）
      AND     M602  ; 载座升降气缸原点
      RST     B1
; 工位1复位
259   LD      B10  ; 工位1复位第一步
      BKRST   B220 K30  ; 工位1启动
      RST     M4003  ; 1#前挡载座1（输出）
      RST     M4005  ; 1#定载座1（输出）
      RST     M4006  ; 1#定载座2（输出）
      OUT     T10 K10
      MPS
      ANI     M4003  ; 1#前挡载座1（输出）
      ANI     M4005  ; 1#定载座1（输出）
      ANI     M4006  ; 1#定载座2（输出）
      AND     M603  ; 1#前挡载座1气缸原点
      AND     M605  ; 1#定载座1气缸原点
      AND     M606  ; 1#定载座2气缸原点
      OUT     T500 K0
      MPP
      LD      T500
      OR      T10
      ANB
      SET     B11  ; 工位1复位第二步
      RST     B10  ; 工位1复位第一步
287   LD      B11  ; 工位1复位第二步
      RST     M4004  ; 1#挡载座（输出）
      ANI     M4004  ; 1#挡载座（输出）
      AND     M604  ; 1#挡载座气缸原点
      RST     B11  ; 工位1复位第二步
      SET     B220  ; 工位1启动
; 工位2复位
300   LD      B20  ; 工位2复位第一步
      BKRST   B240 K100  ; 工位2启动
      RST     M4007  ; 2#前挡载座1（输出）
      RST     M4008  ; 2#前挡载座2（输出）
      RST     M4012  ; 2#压产品（输出）
      RST     M4015  ; 2#取产品上下输出
      RST     M4016  ; 2#吸产品（输出）
      RST     M4017  ; 2#推产品（输出）
      RST     M4018  ; 2#挡产品（输出）
      RST     M4019  ; 2#夹产品（输出）
      MPS
      ANI     M4012  ; 2#压产品（输出）
      ANI     M4008  ; 2#前挡载座2（输出）
      AND     M612  ; 2#压产品气缸原点
      AND     M608  ; 2#前挡载座2气缸原点
      OUT     T112 K1
      MRD
      ANI     M4015  ; 2#取产品上下输出
      ANI     M4017  ; 2#推产品（输出）
      AND     M617  ; 2#推产品气缸原点
      AND     M615  ; 2#取产品上下气缸原点
      OUT     T13 K1
      MPP
      AND     T13
      AND     T112
      SET     B21  ; 工位2复位第二步
      RST     B20  ; 工位2复位第一步
335   LD      B21  ; 工位2复位第二步
      RST     M4010  ; 2#定载座1（输出）
      RST     M4011  ; 2#定载座2（输出）
      MPS
      ANI     M4010  ; 2#定载座1（输出）
      ANI     M4011  ; 2#定载座2（输出）
      AND     M610  ; 2#定载座1气缸原点
      AND     M611  ; 2#定载座2气缸原点
      RST     M4009  ; 2#挡载座（输出）
      MPP
      ANI     M4010  ; 2#定载座1（输出）
      ANI     M4011  ; 2#定载座2（输出）
      ANI     M4009  ; 2#挡载座（输出）
      AND     M610  ; 2#定载座1气缸原点
      AND     M611  ; 2#定载座2气缸原点
      AND     M609  ; 2#挡载座气缸原点
      RST     B21  ; 工位2复位第二步
352   LD      B30  ; 工位3复位第一步
      BKRST   B340 K100  ; 工位3启动
      RST     M4031  ; 3#挡产品（输出）
      RST     M4020  ; 3#前挡载座1（输出）
      RST     M4021  ; 3#前挡载座2（输出）
      RST     M4025  ; 3#压产品（输出）
      RST     M4029  ; 3#吸产品（输出）
      MPS
      ANI     M4029  ; 3#吸产品（输出）
      OUT     T9 K2
      AND     T9
      RST     M4028  ; 3#取产品上下（输出）
      MPP
      RST     M4030  ; 3#推产品（输出）
      RST     M4032  ; 3#夹产品（输出）
      RST     M4026  ; 3#压载带1（输出）
      RST     M4027  ; 3#压载带2（输出）
      MPS
      ANI     M4032  ; 3#夹产品（输出）
      ANI     M4028  ; 3#取产品上下（输出）
      AND     M638  ; 3#取产品气缸原点
      OUT     T11 K1
      MPP
      AND     T11
      SET     B31  ; 工位3复位第二步
      RST     B30  ; 工位3复位第一步
386   LD      B31  ; 工位3复位第二步
      RST     M4032  ; 3#夹产品（输出）
      RST     M4023  ; 3#定载座1（输出）
      RST     M4024  ; 3#定载座2（输出）
      MPS
      ANI     M4023  ; 3#定载座1（输出）
      ANI     M4024  ; 3#定载座2（输出）
      AND     M633  ; 3#定载座1原点
      AND     M634  ; 3#定载座2原点
      RST     M4022  ; 3#挡载座（输出）
      MPP
      ANI     M4032  ; 3#夹产品（输出）
      ANI     M4023  ; 3#定载座1（输出）
      ANI     M4024  ; 3#定载座2（输出）
      AND     M633  ; 3#定载座1原点
      AND     M634  ; 3#定载座2原点
      AND     M632  ; 3#挡载座原点
      RST     B31  ; 工位3复位第二步
; 工位4复位
411   LD      B40  ; 工位4复位第一步
      BKRST   B400 K50  ; 工位4启动
      RST     M4041  ; 4#前挡载座1（输出）
      RST     M4043  ; 4#前挡载座2（输出）
      RST     M4039  ; 4#夹产品（输出）
      RST     M4037  ; 4#定载座3（输出）
      RST     M4038  ; 4#顶载座（输出）
      MPS
      ANI     M4038  ; 4#顶载座（输出）
      AND     M648  ; 4#顶载座气缸原点
      ANI     M4039  ; 4#夹产品（输出）
      AND     M649  ; 4#夹产品气缸原点
      OUT     T117 K1
      MRD
      ANI     M4037  ; 4#定载座3（输出）
      AND     M647  ; 4#定载座3气缸原点
      OUT     T118 K1
      MPP
      AND     T117
      AND     T118
      SET     B41  ; 工位4复位第二步
      RST     B40  ; 工位4复位第一步
441   LD      B41  ; 工位4复位第二步
      RST     M4036  ; 4#定载座2（输出）
      RST     M4034  ; 4#定载座1（输出）
      MPS
      ANI     M4036  ; 4#定载座2（输出）
      AND     M646  ; 4#定载座2气缸原点
      ANI     M4034  ; 4#定载座1（输出）
      AND     M644  ; 4#定载座1气缸原点
      OUT     T119 K1
      MPP
      ANI     M4033  ; 4#挡载座1（输出）
      ANI     M4035  ; 4#挡载座2（输出）
      AND     M643  ; 4#挡载座1气缸原点
      AND     M645  ; 4#挡载座2气缸原点
      AND     T119
      RST     B41  ; 工位4复位第二步
460   LD      B50  ; 降载座复位第一步
      RST     M4060  ; 降载座工位卸载座
      ANI     M4060  ; 降载座工位卸载座
      AND     M639  ; 降载座工位卸载座原点
      SET     B51  ; 降载座复位第二步
      RST     B50  ; 降载座复位第一步
466   LD      B51  ; 降载座复位第二步
      MPS
      ANI     M4036  ; 4#定载座2（输出）
      AND     M646  ; 4#定载座2气缸原点
      RST     M4040  ; 升降气缸（输出）
      MPP
      ANI     M4040  ; 升降气缸（输出）
      AND     M650  ; 升降气缸原点
      RST     B51  ; 降载座复位第二步
475   LD      M10  ; 手动
      ANI     M11  ; 单动
      ANI     M12  ; 自动
      OR      SM402
      ORI     M17  ; 急停（外部按钮）
      SET     M20  ; 手动状态
      RST     M21  ; 单动状态
      RST     M22  ; 自动状态
483   LD      M11  ; 单动
      ANI     M10  ; 手动
      ANI     M12  ; 自动
      SET     M21  ; 单动状态
      RST     M20  ; 手动状态
      RST     M22  ; 自动状态
489   LD      M12  ; 自动
      ANI     M10  ; 手动
      ANI     M11  ; 单动
      SET     M22  ; 自动状态
      RST     M20  ; 手动状态
      RST     M21  ; 单动状态
495   LDP     M13  ; 启动(触摸屏)
      ORP     M15  ; 启动（外部按钮）
      LD      M21  ; 单动状态
      OR      M22  ; 自动状态
      ANB
      ANI     M20  ; 手动状态
      SET     M23  ; 启动
      SET     M25
      RST     M24  ; 停止
504   LD      M80  ; 工位2单动停止
      OR      M81  ; 工位2吸产品单动停止
      OR      M82  ; 工位2放产品单动停止
      OR      M83  ; 工位2装产品单动停止
      OR      M84  ; 工位3单动停止
      OR      M85  ; 工位3吸产品单动停止
      OR      M86  ; 工位3放产品单动停止
      OR      M87  ; 工位3装产品单动停止
      OR      M88  ; 工位4单动停止
      PLS     M4
515   LDI     M2501  ; 1#复原中
      ANI     M2511  ; 2#复原中
      ANI     M2531  ; 4#复原中
      ANI     M2541  ; 5#复原中
      ANI     M2551  ; 6#复原中
      ANI     M2561
      ANI     M2571  ; 8#复原中
      ANI     M2581  ; 9#复原中
      ANI     M2591  ; 10#复原中
      ANI     M2901
      ANI     M2911
      INV
      OUT     M2
528   LDI     M2
      ANI     M0  ; 报警
      ANI     M4
      ANI     M14  ; 停止(触摸屏)
      ANI     M20  ; 手动状态
      ANI     M16  ; 停止（外部按钮）
      AND     M17  ; 急停（外部按钮）
      INV
      RST     M23  ; 启动
      SET     M24  ; 停止
538   LDP     M24  ; 停止
      OR      M14  ; 停止(触摸屏)
      BKRST   M120 K10  ; 工位1前挡放料条件
543   LDI     M20  ; 手动状态
      INV
      RST     M25
546   LD      M20  ; 手动状态
      AND     M24  ; 停止
      OUT     M26
549   LD      M21  ; 单动状态
      OR      M22  ; 自动状态
      ANI     M20  ; 手动状态
      PLS     M28
554   LD      M28
      BKRST   M3000 K600
      BKRST   M100 K300  ; 工位1前挡料1互锁
      RST     M4100  ; 2#手动拉料
      RST     M4200  ; 3#手动拉料
563   LD      M28
      SET     B0
      MOV     K0 D680  ; 2#放料次数计数
      MOV     K0 D690  ; 3#放料次数计数
      MOV     K0 D210  ; 3#吸料次数计数
      MOV     K0 D100  ; 工位2装产品次数计数
      MOV     K0 D110  ; 工位3装产品次数计数
      SET     B10  ; 工位1复位第一步
      SET     B20  ; 工位2复位第一步
      SET     B30  ; 工位3复位第一步
      SET     B40  ; 工位4复位第一步
      SET     B50  ; 降载座复位第一步
580   LDI     B11  ; 工位1复位第二步
      ANI     B21  ; 工位2复位第二步
      ANI     B31  ; 工位3复位第二步
      ANI     B41  ; 工位4复位第二步
      ANI     B51  ; 降载座复位第二步
      OUT     M6
586   LDI     B10  ; 工位1复位第一步
      ANI     B20  ; 工位2复位第一步
      ANI     B30  ; 工位3复位第一步
      ANI     B40  ; 工位4复位第一步
      ANI     B50  ; 降载座复位第一步
      AND     M6
      PLS     M29
594   LDP     M29
      SET     B200  ; 升载座工位启动
      SET     B220  ; 工位1启动
      SET     B240  ; 工位2启动
      SET     B340  ; 工位3启动
      SET     B400  ; 工位4启动
      SET     B420  ; 升载座启动
      SET     B190
      SET     B1A0
      SET     B1B0
604   END
END_PROGRAM

PROGRAM 升载座
VAR
  ZRST : BOOL;
END_VAR
0     LD      M601  ; 卸载座气缸原点
      AND     M602  ; 载座升降气缸原点
      AND=    K2B201 K0  ; 升载座工位第一步
      AND     T301
      OUT     M70  ; 升载座气缸在原点
7     LD      M22  ; 自动状态
      OR      M21  ; 单动状态
      AND     M23  ; 启动
      ANI     M4002  ; 载座升降（输出）
      AND     M602  ; 载座升降气缸原点
      ANI     M623  ; 升载座工位载座到位感应
      AND=    K2B201 K0  ; 升载座工位第一步
      SET     M4000  ; 下挡载座（输出）
17    LD      M623  ; 升载座工位载座到位感应
      OUT     T301 D310
22    LD      T301
      OR<>    K2B201 K0  ; 升载座工位第一步
      RST     M4000  ; 下挡载座（输出）
27    LD      M70  ; 升载座气缸在原点
      AND     M23  ; 启动
      ANI     M24  ; 停止
      AND     B200  ; 升载座工位启动
      SET     B201  ; 升载座工位第一步
32    LD      B201  ; 升载座工位第一步
      MPS
      AND     M602  ; 载座升降气缸原点
      SET     M4002  ; 载座升降（输出）
      MRD
      AND     M4002  ; 载座升降（输出）
      AND     M802  ; 载座升降气缸终点
      OUT     T305 D312
      MRD
      AND     T305
      SET     B202  ; 升载座工位第二步
      RST     B201  ; 升载座工位第一步
      MPP
      RST     B200  ; 升载座工位启动
49    LD      B202  ; 升载座工位第二步
      MPS
      AND     M601  ; 卸载座气缸原点
      ANI     M624  ; 1#前挡载座到位感应
      ANI     M4042  ; 1#前挡载座2（输出）
      SET     M4001  ; 卸载座（输出）
      MRD
      AND     M4001  ; 卸载座（输出）
      AND     M801  ; 卸载座气缸终点
      OUT     T303 D314
      MPP
      AND     T303
      SET     B203  ; 升载座工位第三步
      RST     B202  ; 升载座工位第二步
66    LD      B203  ; 升载座工位第三步
      RST     M4001  ; 卸载座（输出）
      MPS
      ANI     M4001  ; 卸载座（输出）
      AND     M601  ; 卸载座气缸原点
      OUT     T302 D316
      MPP
      AND     T302
      SET     B204  ; 升载座工位第四步
      RST     B203  ; 升载座工位第三步
79    LD      B204  ; 升载座工位第四步
      RST     M4002  ; 载座升降（输出）
      MPS
      ANI     M4002  ; 载座升降（输出）
      AND     M602  ; 载座升降气缸原点
      OUT     T304 D318
      MPP
      AND     T304
      RST     B204  ; 升载座工位第四步
      SET     B200  ; 升载座工位启动
      AND     M21  ; 单动状态
      PLS     M80  ; 工位2单动停止
95    END
END_PROGRAM

PROGRAM 工位1
0     LD      M652  ; 1#前挡气缸2原点
      ANI     M4042  ; 1#前挡载座2（输出）
      AND     M624  ; 1#前挡载座到位感应
      OUT     T14 K2
7     LD      B190
      AND     M22  ; 自动状态
      LD      B190
      AND     M21  ; 单动状态
      ORB
      AND     M23  ; 启动
      ANI     M24  ; 停止
      SET     B191
      RST     B190
16    LD      B191
      AND     M23  ; 启动
      AND     M22  ; 自动状态
      LD      B191
      AND     M23  ; 启动
      AND     M21  ; 单动状态
      ORB
      MPS
      ANI     M625  ; 1#挡载座载座到位感应
      AND     T14
      ANI     M100  ; 工位1前挡料1互锁
      ANI     M4042  ; 1#前挡载座2（输出）
      AND     M652  ; 1#前挡气缸2原点
      SET     M4042  ; 1#前挡载座2（输出）
      SET     M120  ; 工位1前挡放料条件
      SET     M100  ; 工位1前挡料1互锁
      MPP
      AND     M4042  ; 1#前挡载座2（输出）
      SET     B192
      RST     B191
36    LD      B192
      MPS
      AND     M4042  ; 1#前挡载座2（输出）
      OUT     T307 D320
      MPP
      AND     T307
      AND     M625  ; 1#挡载座载座到位感应
      RST     M4042  ; 1#前挡载座2（输出）
      SET     B190
      RST     M191
49    LD      M625  ; 1#挡载座载座到位感应
      OUT     T54 D322
54    LD      M625  ; 1#挡载座载座到位感应
      AND=    K4B221 K0  ; 工位1第一步
      AND     M604  ; 1#挡载座气缸原点
      AND     M605  ; 1#定载座1气缸原点
      AND     M606  ; 1#定载座2气缸原点
      OUT     M71  ; 工位1所有气缸在原点
62    LD      M22  ; 自动状态
      OR      M21  ; 单动状态
      AND     B220  ; 工位1启动
      AND=    K1B230 K0
      AND     M23  ; 启动
      AND     T54
      ANI     M24  ; 停止
      AND     M71  ; 工位1所有气缸在原点
      MPS
      ANI     M4501
      SET     B221  ; 工位1第一步
      MRD
      AND     M4501
      SET     B224  ; 工位1第四步
      MPP
      RST     B220  ; 工位1启动
80    LD      B221  ; 工位1第一步
      MPS
      AND     M605  ; 1#定载座1气缸原点
      SET     M4005  ; 1#定载座1（输出）
      MRD
      AND     M4005  ; 1#定载座1（输出）
      AND     M805  ; 1#定载座1气缸终点
      OUT     T311 D324
      MPP
      AND     T311
      SET     B222  ; 工位1第二步
      RST     B221  ; 工位1第一步
95    LD      B222  ; 工位1第二步
      MPS
      AND     M606  ; 1#定载座2气缸原点
      SET     M4006  ; 1#定载座2（输出）
      MRD
      AND     M4006  ; 1#定载座2（输出）
      AND     M806  ; 1#定载座2气缸终点
      OUT     T312 D326
      MPP
      AND     T312
      SET     B223  ; 工位1第三步
      RST     B222  ; 工位1第二步
110   LD      B223  ; 工位1第三步
      MPS
      ANDP    X11A  ; 1#脚踏启动
      RST     M4006  ; 1#定载座2（输出）
      RST     M4005  ; 1#定载座1（输出）
      MRD
      ANI     M4006  ; 1#定载座2（输出）
      ANI     M4005  ; 1#定载座1（输出）
      AND     M605  ; 1#定载座1气缸原点
      AND     M606  ; 1#定载座2气缸原点
      OUT     T313 D328
      MPP
      AND     T313
      SET     B224  ; 工位1第四步
      RST     B223  ; 工位1第三步
128   LD      B224  ; 工位1第四步
      MPS
      AND     M604  ; 1#挡载座气缸原点
      ANI     T320  ; 工位2满料感应延时
      ANI     M4004  ; 1#挡载座（输出）
      SET     M4004  ; 1#挡载座（输出）
      MRD
      AND     M4004  ; 1#挡载座（输出）
      AND     M804  ; 1#挡载座气缸终点
      OUT     T314 D330
      MPP
      AND     T314
      SET     B225  ; 工位1第五步
      RST     B224  ; 工位1第四步
145   LD      B225  ; 工位1第五步
      RST     M4004  ; 1#挡载座（输出）
      ANI     M4004  ; 1#挡载座（输出）
      AND     M604  ; 1#挡载座气缸原点
      MPS
      AND     M21  ; 单动状态
      PLS     M79  ; 升载座工位单动停止
      MPP
      RST     M100  ; 工位1前挡料1互锁
      SET     B220  ; 工位1启动
      RST     B225  ; 工位1第五步
157   END
END_PROGRAM

PROGRAM 工站2
0     LD      M626  ; 2#前挡载座到位感应
      AND     M608  ; 2#前挡载座2气缸原点
      ANI     M4008  ; 2#前挡载座2（输出）
      OUT     T3 K5
7     LD      B1A0
      AND     M22  ; 自动状态
      LD      B1A0
      AND     M21  ; 单动状态
      ORB
      AND     M23  ; 启动
      ANI     M24  ; 停止
      SET     B1A1
      RST     B1A0
16    LD      B1A1
      AND     M22  ; 自动状态
      LD      B1A1
      AND     M21  ; 单动状态
      ORB
      AND     M23  ; 启动
      ANI     M24  ; 停止
      AND     T3
      SET     M4007  ; 2#前挡载座1（输出）
      MPS
      AND     M4007  ; 2#前挡载座1（输出）
      OUT     T325 D332
      MPP
      AND     T325
      SET     B1A2
      RST     B1A1
35    LD      B1A2
      MPS
      ANI     M628  ; 2#挡载座到位感应
      AND     M23  ; 启动
      ANI     M24  ; 停止
      AND     T3
      ANI     M101  ; 工位2前挡料互锁
      SET     M4008  ; 2#前挡载座2（输出）
      SET     M101  ; 工位2前挡料互锁
      SET     M121  ; 工位2前挡放料条件
      MRD
      AND     M4008  ; 2#前挡载座2（输出）
      AND     M808  ; 2#前挡载座2气缸终点
      OUT     T318 D334
      MPP
      AND     M628  ; 2#挡载座到位感应
      AND     T318
      RST     M4008  ; 2#前挡载座2（输出）
      RST     M4007  ; 2#前挡载座1（输出）
      SET     B1A0
      RST     B1A2
59    LD      SM400
      DMOV    SD1880 D5280  ; 高数计数器1当前值 / 2#拉料编码器当前值
      DMOV    SD1900 D5290  ; 高数计数器2当前值 / 3#l拉料编码器当前值
      DMOV    SD1880 D600  ; 工位3开路测试结果
      DMOV    SD1900 D610  ; 工位3短路测试结果
      D*      D5290 K-1 D5292  ; 3#l拉料编码器当前值
      MPS
      ANI     M4013  ; 2#压载带1（输出）
      ANI     M4014  ; 2#压载带2（输出）
      ANI     M140  ; 计数器清零
      SET     SM1895
      MPP
      ANI     M4026  ; 3#压载带1（输出）
      ANI     M4027  ; 3#压载带2（输出）
      ANI     M140  ; 计数器清零
      SET     SM1915
82    LD      SM402
      SET     M140  ; 计数器清零
84    LDI     M4013  ; 2#压载带1（输出）
      ANI     M4014  ; 2#压载带2（输出）
      OUT     M150
      ANDP    M150
      SET     M151  ; 2#拉料清零
89    LDI     M4026  ; 3#压载带1（输出）
      ANI     M4027  ; 3#压载带2（输出）
      OUT     M152
      ANDP    M152
      SET     M153  ; 3#拉料清零
94    LD      M140  ; 计数器清零
      OR      M151  ; 2#拉料清零
      OR      M153  ; 3#拉料清零
      MPS
      LD      M151  ; 2#拉料清零
      OR      M140  ; 计数器清零
      ANB
      DMOV    K0 D5280
      DMOV    K0 D5180  ; 2#拉料当前值比较
      DMOV    K0 D5186
      DMOV    K0 D500  ; 2#拉料次数计数
      MRD
      LD      M153  ; 3#拉料清零
      OR      M140  ; 计数器清零
      ANB
      DMOV    K0 D5290
      DMOV    K0 D510  ; 3#拉料次数计数
      DMOV    K0 D5190  ; 3#l拉料当前值比较
      DMOV    K0 D5196
      MPP
      OUT     T22 K8
      AND     T22
      RST     M140  ; 计数器清零
      RST     M151  ; 2#拉料清零
      RST     M153  ; 3#拉料清零
138   LD      M151  ; 2#拉料清零
      OR      M140  ; 计数器清零
      ?OP6529 K0
      OUT     SM1893
144   LD      M153  ; 3#拉料清零
      OR      M140  ; 计数器清零
      ?OP652A K0
      OUT     SM1913
150   LD      M627  ; 2#载座满料感应
      OUT     T320 D336  ; 工位2满料感应延时
155   LD      M628  ; 2#挡载座到位感应
      OUT     T321 D338  ; 工位2载座到位感应
; 工位2移载段
168   LD=     K1M609 K15  ; 2#挡载座气缸原点
      AND     T321  ; 工位2载座到位感应
      AND=    K2B241 K0  ; 工位2第一步
      OUT     M72  ; 工位2所有气缸在原点
176   LD      M22  ; 自动状态
      OR      M21  ; 单动状态
      AND     B240  ; 工位2启动
      AND     M72  ; 工位2所有气缸在原点
      AND     M23  ; 启动
      ANI     M24  ; 停止
      MPS
      ANI     M4502  ; 工位2开关（ON为关）
      SET     B241  ; 工位2第一步
      MPP
      RST     M210  ; 2#装料完成
      MPS
      AND=    K2B251 K0  ; 工位2吸产品段第一步
      ANI     M4502  ; 工位2开关（ON为关）
      SET     B250  ; 工位2吸产品段启动
      MRD
      AND=    K2B261 K0  ; 工位2放产品第一步
      ANI     M4502  ; 工位2开关（ON为关）
      SET     B260  ; 工位2放产品启动
      MRD
      AND=    K2B271 K0  ; 工位2插模组第一步
      ANI     M4502  ; 工位2开关（ON为关）
      SET     B270  ; 工位2插模组启动
      MRD
      AND     M4502  ; 工位2开关（ON为关）
      SET     B248  ; 工位2第八步
      MPP
      RST     B240  ; 工位2启动
210   LD      B241  ; 工位2第一步
      MPS
      AND     M610  ; 2#定载座1气缸原点
      SET     M4010  ; 2#定载座1（输出）
      MRD
      AND     M4010  ; 2#定载座1（输出）
      AND     M810  ; 2#定载座1气缸终点
      OUT     T322 D340
      MPP
      AND     T322
      SET     B242  ; 工位2第二步
      RST     B241  ; 工位2第一步
225   LD      B242  ; 工位2第二步
      MPS
      AND     M611  ; 2#定载座2气缸原点
      SET     M4011  ; 2#定载座2（输出）
      MRD
      AND     M4011  ; 2#定载座2（输出）
      AND     M811  ; 2#定载座2气缸终点
      OUT     T323 D342
      MPP
      AND     T323
      SET     B243  ; 工位2第三步
      RST     B242  ; 工位2第二步
240   LD      B243  ; 工位2第三步
      MPS
      AND     M612  ; 2#压产品气缸原点
      SET     M4012  ; 2#压产品（输出）
      MRD
      AND     M4012  ; 2#压产品（输出）
      AND     M812  ; 2#压产品气缸终点
      OUT     T324 D344
      MPP
      AND     T324
      SET     B244  ; 工位2第四步
      RST     B243  ; 工位2第三步
255   LD      B244  ; 工位2第四步
      AND     B27F  ; 工位2插模组段完成标志
      MPS
      AND=    D100 K1  ; 工位2装产品次数计数
      PLS     M1361  ; 4#  2#移载座轴位置2（自动）
      MRD
      AND=    D100 K2  ; 工位2装产品次数计数
      PLS     M1362  ; 4#  2#移载座轴位置3（自动）
      MRD
      AND=    D100 K3  ; 工位2装产品次数计数
      PLS     M1363  ; 4#  2#移载座轴位置4（自动）
      MRD
      AND=    D100 K4  ; 工位2装产品次数计数
      PLS     M1364  ; 4#  2#移载座轴位置5（自动）
      MRD
      AND=    D100 K5  ; 工位2装产品次数计数
      PLS     M1365  ; 4#  2#移载座轴位置6（自动）
      MRD
      AND=    D100 K6  ; 工位2装产品次数计数
      PLS     M1366  ; 4#  2#移载座轴位置7（自动）
      MRD
      AND=    D100 K7  ; 工位2装产品次数计数
      PLS     M1367  ; 4#  2#移载座轴位置8（自动）
      MRD
      AND=    D100 K8  ; 工位2装产品次数计数
      PLS     M1368  ; 4#  2#移载座轴位置9（自动）
      MRD
      AND=    D100 K9  ; 工位2装产品次数计数
      ANI     M4515  ; 产品选择按钮（OFF为产品1）
      PLS     M1369  ; 4#  2#移载座轴位置10（自动）
      MRD
      LD<>    K2M2761 K0  ; 4#  2#移载座轴在位置1
      OR      M2769  ; 4#  2#移载座轴在位置9
      OR      M2770  ; 4#  2#移载座轴在位置10
      ANB
      OUT     T340 K1
      MPP
      AND     T340
      SET     B245  ; 工位2第五步
      RST     B244  ; 工位2第四步
327   LD      B245  ; 工位2第五步
      OUT     T341 K1
      RST     B27F  ; 工位2插模组段完成标志
      LD      T341
      OR      T341
      ANB
      MPS
      LD<     D100 K10  ; 工位2装产品次数计数
      ANI     M4515  ; 产品选择按钮（OFF为产品1）
      LD<     D100 K9  ; 工位2装产品次数计数
      AND     M4515  ; 产品选择按钮（OFF为产品1）
      ORB
      ANB
      SET     B244  ; 工位2第四步
      MRD
      LD>=    D100 K10  ; 工位2装产品次数计数
      ANI     M4515  ; 产品选择按钮（OFF为产品1）
      LD>=    D100 K9  ; 工位2装产品次数计数
      AND     M4515  ; 产品选择按钮（OFF为产品1）
      ORB
      ANB
      SET     B246  ; 工位2第六步
      MPP
      RST     B245  ; 工位2第五步
362   LD      B246  ; 工位2第六步
      RST     M4012  ; 2#压产品（输出）
      MPS
      ANI     M4012  ; 2#压产品（输出）
      AND     M612  ; 2#压产品气缸原点
      OUT     T342 D346
      MPP
      AND     T342
      SET     B247  ; 工位2第七步
      MOV     K0 D100
      RST     B246  ; 工位2第六步
377   LD      B247  ; 工位2第七步
      RST     M4010  ; 2#定载座1（输出）
      RST     M4011  ; 2#定载座2（输出）
      MPS
      ANI     M4010  ; 2#定载座1（输出）
      ANI     M4011  ; 2#定载座2（输出）
      AND     M610  ; 2#定载座1气缸原点
      AND     M611  ; 2#定载座2气缸原点
      OUT     T343 D348
      MPP
      AND     T343
      SET     B248  ; 工位2第八步
      RST     B247  ; 工位2第七步
393   LD      B248  ; 工位2第八步
      MPS
      ANI     T350  ; 工位3前挡满料感应光纤延时
      SET     M4009  ; 2#挡载座（输出）
      MRD
      AND     M4009  ; 2#挡载座（输出）
      AND     M809  ; 2#挡载座气缸终点
      OUT     T344 D350
      PLS     M1360  ; 4#  2#移载座轴位置1（自动）
      MPP
      AND     T344
      SET     B249  ; 工位2第九步
      RST     B248  ; 工位2第八步
410   LD      B249  ; 工位2第九步
      MPS
      AND     M2761  ; 4#  2#移载座轴在位置1
      RST     M4009  ; 2#挡载座（输出）
      RST     M101  ; 工位2前挡料互锁
      MPP
      ANI     M4009  ; 2#挡载座（输出）
      AND     M609  ; 2#挡载座气缸原点
      SET     B240  ; 工位2启动
      RST     M101  ; 工位2前挡料互锁
      MOV     K0 D100
      MPS
      AND     M21  ; 单动状态
      PLS     M80  ; 工位2单动停止
      MPP
      RST     B249  ; 工位2第九步
; 工位2吸产品段
437   LDI     B25F  ; 工位2吸产品段完成标志
      OR      M22  ; 自动状态
      AND     M615  ; 2#取产品上下气缸原点
      AND=    K1B251 K0  ; 工位2吸产品段第一步
      OUT     M73  ; 工位2吸产品段气缸在原点
444   LD      B250  ; 工位2吸产品段启动
      AND     M22  ; 自动状态
      LD      B250  ; 工位2吸产品段启动
      AND     M21  ; 单动状态
      ORB
      AND     M23  ; 启动
      ANI     M24  ; 停止
      AND     M73  ; 工位2吸产品段气缸在原点
      ANI     X1C  ; 轴1 busy
      SET     B251  ; 工位2吸产品段第一步
      RST     B250  ; 工位2吸产品段启动
455   LD      B251  ; 工位2吸产品段第一步
      OUT     M2300
      MPS
      AND     M2300
      ANI     M4540  ; 2#送载带开关（ON为关）
      INCP    D500
      MPP
      D*      D500 D1050 D5180  ; 2#料带间距
      D+P     D5180 D502 D5186  ; 2#拉料修正
      LDI     M4540  ; 2#送载带开关（ON为关）
      ANDD>=  D5280 D5186  ; 2#拉料编码器当前值
      OR      M4540  ; 2#送载带开关（ON为关）
      ANB
      SET     B252  ; 工位2吸产品段第二步
      RST     M2300
      RST     B251  ; 工位2吸产品段第一步
478   LD      M23  ; 启动
      AND     B252  ; 工位2吸产品段第二步
      MPS
      AND     M2781  ; 5#  2#出载带移载在位置1
      AND     M615  ; 2#取产品上下气缸原点
      ANI     X1E  ; 轴3 busy
      SET     M4015  ; 2#取产品上下输出
      MRD
      AND     M2781  ; 5#  2#出载带移载在位置1
      AND     M4015  ; 2#取产品上下输出
      AND     M815  ; 2#取产品上下终点
      OUT     T8 D352
      MPP
      AND     T8
      SET     B253  ; 工位2吸产品段第三步
      RST     B252  ; 工位2吸产品段第二步
497   LD      B253  ; 工位2吸产品段第三步
      SET     M4016  ; 2#吸产品（输出）
      MPS
      AND     M4016  ; 2#吸产品（输出）
      OUT     T326 D356
      MPP
      AND     T326
      SET     B254  ; 工位2吸产品段第四步
      RST     B253  ; 工位2吸产品段第三步
509   LD      B254  ; 工位2吸产品段第四步
      RST     M4015  ; 2#取产品上下输出
      MPS
      ANI     M4015  ; 2#取产品上下输出
      AND     M615  ; 2#取产品上下气缸原点
      OUT     T327 D354
      MPP
      AND     T327
      SET     B255  ; 工位2吸产品段第五步
      RST     B254  ; 工位2吸产品段第四步
522   LD      B255  ; 工位2吸产品段第五步
      MPS
      ANI     M4015  ; 2#取产品上下输出
      AND     M615  ; 2#取产品上下气缸原点
      PLS     M1461  ; 5#  2#出载带移载位置2（自动）
      MRD
      AND     M2782  ; 5#  2#出载带移载在位置2
      OUT     T328 K0
      MPP
      AND     T328
      MPS
      ANI     M210  ; 2#装料完成
      SET     B250  ; 工位2吸产品段启动
      MPP
      SET     B25F  ; 工位2吸产品段完成标志
      MPS
      AND     M21  ; 单动状态
      ANI     SM400
      PLS     M81  ; 工位2吸产品单动停止
      MPP
      RST     B255  ; 工位2吸产品段第五步
; 工位2放产品段
557   LDI     B26F  ; 工位2放产品段完成标准
      OR      M22  ; 自动状态
      ANI     X17F  ; 工位2产品产应
      AND     M615  ; 2#取产品上下气缸原点
      AND=    K1B261 K0  ; 工位2放产品第一步
      AND     M2782  ; 5#  2#出载带移载在位置2
      OUT     M74  ; 工位2放产品段气缸在原点
566   LD      M22  ; 自动状态
      OR      M21  ; 单动状态
      AND     B260  ; 工位2放产品启动
      AND     M23  ; 启动
      AND     B25F  ; 工位2吸产品段完成标志
      ANI     M24  ; 停止
      ANI     X17F  ; 工位2产品产应
      SET     B261  ; 工位2放产品第一步
      RST     B260  ; 工位2放产品启动
575   LD      B261  ; 工位2放产品第一步
      MPS
      AND     M615  ; 2#取产品上下气缸原点
      ANI     M4017  ; 2#推产品（输出）
      AND     M617  ; 2#推产品气缸原点
      ANI     X17F  ; 工位2产品产应
      ANI     M132  ; 2#放料控制（第一次）
      ANI     X1E  ; 轴3 busy
      AND     M2782  ; 5#  2#出载带移载在位置2
      SET     M4015  ; 2#取产品上下输出
      MRD
      AND     M2782  ; 5#  2#出载带移载在位置2
      AND     M4015  ; 2#取产品上下输出
      AND     X136  ; 2#吸产品上下终点2
      OUT     T12 D352
      SET     M132  ; 2#放料控制（第一次）
      MPP
      AND     T12
      SET     B262  ; 工位2放产品第二步
      RST     B261  ; 工位2放产品第一步
598   LD      B262  ; 工位2放产品第二步
      RST     M4016  ; 2#吸产品（输出）
      MPS
      ANI     M4016  ; 2#吸产品（输出）
      OUT     T330 D358
      MPP
      AND     T330
      SET     B263  ; 工位2放产品第三步
      RST     B262  ; 工位2放产品第二步
610   LD      B263  ; 工位2放产品第三步
      RST     M4015  ; 2#取产品上下输出
      MPS
      ANI     M4015  ; 2#取产品上下输出
      AND     M615  ; 2#取产品上下气缸原点
      OUT     T331 D354
      MPP
      INCP    D680  ; 2#放料次数计数
      AND     T331
      SET     B264  ; 工位2放产品第四步
      RST     B263  ; 工位2放产品第三步
625   LD      B264  ; 工位2放产品第四步
      MPS
      ANI     M4015  ; 2#取产品上下输出
      AND     M615  ; 2#取产品上下气缸原点
      PLS     M1460  ; 5#  2#出载带移载位置1（自动）
      MRD
      AND     M2781  ; 5#  2#出载带移载在位置1
      OUT     T334 K1
      MRD
      ANDP    B264  ; 工位2放产品第四步
      SET     B26F  ; 工位2放产品段完成标准
      MRD
      ANI     SM400
      RST     B25F  ; 工位2吸产品段完成标志
      MPP
      AND     T334
      MPS
      ANI     M210  ; 2#装料完成
      SET     B260  ; 工位2放产品启动
      MRD
      AND     M82  ; 工位2放产品单动停止
      ANI     SM400
      PLS     M82  ; 工位2放产品单动停止
      MPP
      RST     B264  ; 工位2放产品第四步
; 工位2插模组段
664   LD      X17F  ; 工位2产品产应
      OR      M4520  ; 2#产品感应开关（ON为关）
      AND     M617  ; 2#推产品气缸原点
      AND     M618  ; 2#挡产品气缸原点
      AND=    K2B271 K0  ; 工位2插模组第一步
      OUT     M75  ; 工位2插模组段气缸在原点
672   LD      B270  ; 工位2插模组启动
      AND     M22  ; 自动状态
      LD      B270  ; 工位2插模组启动
      AND     M21  ; 单动状态
      ORB
      LD      X17F  ; 工位2产品产应
      OR      M4520  ; 2#产品感应开关（ON为关）
      ANB
      AND     M75  ; 工位2插模组段气缸在原点
      AND     M23  ; 启动
      ANI     M24  ; 停止
      SET     B271  ; 工位2插模组第一步
      RST     B270  ; 工位2插模组启动
685   LD      B271  ; 工位2插模组第一步
      MPS
      AND     M618  ; 2#挡产品气缸原点
      SET     M4018  ; 2#挡产品（输出）
      MPP
      RST     M134
      MPS
      AND     M4018  ; 2#挡产品（输出）
      AND     M818  ; 2#挡产品气缸终点
      OUT     T333 D360
      MPP
      AND     T333
      SET     B272  ; 工位2插模组第二步
      RST     B271  ; 工位2插模组第一步
702   LD      X17F  ; 工位2产品产应
      OR      M4520  ; 2#产品感应开关（ON为关）
      LD      M22  ; 自动状态
      ANI     M130
      LD      M21  ; 单动状态
      AND     SM400
      ORB
      OR      B26F  ; 工位2放产品段完成标准
      ANB
      ANI     M4015  ; 2#取产品上下输出
      AND     M615  ; 2#取产品上下气缸原点
      OUT     M40  ; 工位2推料条件
714   LDF     M22  ; 自动状态
      RST     M130
      RST     M130
717   LD      B272  ; 工位2插模组第二步
      OR      B270  ; 工位2插模组启动
      ANI     M134
      ANI     M4520  ; 2#产品感应开关（ON为关）
      ANI     X17F  ; 工位2产品产应
      AND     B25F  ; 工位2吸产品段完成标志
      AND     B26F  ; 工位2放产品段完成标准
      MPS
      AND>=   D680 D700  ; 2#放料次数计数
      SET     M5045  ; 2#吸料异常
      MPP
      RST     M132  ; 2#放料控制（第一次）
      RST     B25F  ; 工位2吸产品段完成标志
      RST     B26F  ; 工位2放产品段完成标准
733   LD      B272  ; 工位2插模组第二步
      MPS
      AND     M818  ; 2#挡产品气缸终点
      AND     M617  ; 2#推产品气缸原点
      AND     M40  ; 工位2推料条件
      SET     M4017  ; 2#推产品（输出）
      SET     M134
      MPP
      SET     M130
      MPS
      AND     M4017  ; 2#推产品（输出）
      AND     M817  ; 2#推产品气缸终点
      OUT     T335 D362
      RST     B26F  ; 工位2放产品段完成标准
      MOV     K0 D680
      MPP
      AND     T335
      SET     B273  ; 工位2插模组第三步
      RST     B272  ; 工位2插模组第二步
756   LD      B273  ; 工位2插模组第三步
      SET     M4019  ; 2#夹产品（输出）
      MPS
      AND     M4019  ; 2#夹产品（输出）
      OUT     T336 D364
      MPP
      AND     T336
      SET     B274  ; 工位2插模组第四步
      RST     B273  ; 工位2插模组第三步
768   LD      B274  ; 工位2插模组第四步
      RST     M4017  ; 2#推产品（输出）
      RST     M134
      MPS
      AND     M22  ; 自动状态
      RST     M132  ; 2#放料控制（第一次）
      MPP
      RST     M4018  ; 2#挡产品（输出）
      MOV     K0 D200  ; 2#吸料次数计数
      MPS
      ANI     M4017  ; 2#推产品（输出）
      ANI     M4018  ; 2#挡产品（输出）
      AND     M617  ; 2#推产品气缸原点
      AND     M618  ; 2#挡产品气缸原点
      OUT     T337 D366
      MPP
      AND     T337
      SET     B275  ; 工位2插模组第五步
      RST     B274  ; 工位2插模组第四步
791   LD      B275  ; 工位2插模组第五步
      MPS
      AND     B244  ; 工位2第四步
      AND     M4012  ; 2#压产品（输出）
      ANI     B27F  ; 工位2插模组段完成标志
      AND     M617  ; 2#推产品气缸原点
      AND     M618  ; 2#挡产品气缸原点
      PLS     M1561  ; 6#  2#装产品轴位置2（自动）
      INCP    D100
      MRD
      AND     M2802  ; 6#  2#装产品轴在位置2
      OUT     T338 K1
      MPP
      AND     T338
      SET     B276  ; 工位2插模组第六步
      RST     B275  ; 工位2插模组第五步
812   LD      B276  ; 工位2插模组第六步
      RST     M4019  ; 2#夹产品（输出）
      MPS
      ANI     M4019  ; 2#夹产品（输出）
      OUT     T339 D368
      MPP
      AND     T339
      SET     B277  ; 工位2插模组第七步
      RST     B276  ; 工位2插模组第六步
824   LD      B277  ; 工位2插模组第七步
      PLS     M1560  ; 6#   2#装产品轴位置1（自动）
      MPS
      LD      M21  ; 单动状态
      AND>=   D100 K10  ; 工位2装产品次数计数
      ANI     M4515  ; 产品选择按钮（OFF为产品1）
      LD      M21  ; 单动状态
      AND>=   D100 K9  ; 工位2装产品次数计数
      AND     M4515  ; 产品选择按钮（OFF为产品1）
      ORB
      ANB
      SET     M210  ; 2#装料完成
      BKRST   B250 K5
      MPP
      AND     M2801  ; 6#  2#装产品轴在位置1
      MPS
      LDI     M210  ; 2#装料完成
      AND     M21  ; 单动状态
      LD<     D100 K10  ; 工位2装产品次数计数
      ANI     M4515  ; 产品选择按钮（OFF为产品1）
      LD<     D100 K9  ; 工位2装产品次数计数
      AND     M4515  ; 产品选择按钮（OFF为产品1）
      ORB
      AND     M22  ; 自动状态
      ORB
      ANB
      SET     B270  ; 工位2插模组启动
      MRD
      AND     M21  ; 单动状态
      PLS     M83  ; 工位2装产品单动停止
      RST     B25F  ; 工位2吸产品段完成标志
      RST     B26F  ; 工位2放产品段完成标准
      RST     M132  ; 2#放料控制（第一次）
      MPP
      SET     B27F  ; 工位2插模组段完成标志
      RST     B277  ; 工位2插模组第七步
872   END
END_PROGRAM

PROGRAM 工站3
0     LD      M630  ; 3#前挡载座1原点
      ANI     M4030  ; 3#推产品（输出）
      AND     M668  ; 3#前挡料2载座到位感应
      OUT     M184
4     LD      M668  ; 3#前挡料2载座到位感应
      OUT     T4 K5
9     LD      B1B0
      AND     M22  ; 自动状态
      LD      B1B0
      AND     M21  ; 单动状态
      ORB
      AND     M23  ; 启动
      ANI     M24  ; 停止
      SET     B1B1
      RST     B1B0
18    LD      B1B1
      AND     M22  ; 自动状态
      LD      B1B1
      AND     M21  ; 单动状态
      ORB
      AND     M23  ; 启动
      ANI     M24  ; 停止
      AND     T4
      SET     M4020  ; 3#前挡载座1（输出）
      MPS
      AND     M4020  ; 3#前挡载座1（输出）
      OUT     T317 D370
      MPP
      AND     T317
      SET     B1B2
      RST     B1B1
37    LD      B1B2
      MPS
      ANI     M669  ; 3#载座到位感应
      AND     M23  ; 启动
      ANI     M24  ; 停止
      AND     T4
      ANI     M102  ; 工位3前挡料互锁
      SET     M4021  ; 3#前挡载座2（输出）
      SET     M102  ; 工位3前挡料互锁
      SET     M122  ; 工位3前挡放料条件
      MRD
      AND     M4021  ; 3#前挡载座2（输出）
      AND     M831  ; 3#前挡载座2终点
      OUT     T6 D372
      MPP
      AND     M669  ; 3#载座到位感应
      AND     T6
      RST     M4020  ; 3#前挡载座1（输出）
      RST     M4021  ; 3#前挡载座2（输出）
      SET     B1B0
      RST     B1B2
61    LD      M669  ; 3#载座到位感应
      OUT     T351 D374  ; 工位3载座到位感应延时
66    LD      M819  ; 3#载座满料感应
      OUT     T350 D376  ; 工位3前挡满料感应光纤延时
71    LD      M667  ; 4#前挡载座满料光纤
      OUT     T26 D376
76    LD=     K1M632 K15  ; 3#挡载座原点
      AND     T351  ; 工位3载座到位感应延时
      AND=    K2B341 K0  ; 工位3第一步
      OUT     M63  ; 工位3所有气缸在原点
84    LD      M22  ; 自动状态
      OR      M21  ; 单动状态
      AND     B340  ; 工位3启动
      AND     M63  ; 工位3所有气缸在原点
      AND     M23  ; 启动
      ANI     M24  ; 停止
      MPS
      ANI     M4503  ; 工位3开关（ON为关）
      SET     B341  ; 工位3第一步
      MPP
      RST     M220  ; 3#装料完成
      MPS
      AND=    K2B351 K0  ; 工位3吸产品段第一步
      ANI     M4503  ; 工位3开关（ON为关）
      SET     B350  ; 工位3吸产品段启动
      MRD
      AND=    K2B361 K0  ; 工位3放产品第一步
      ANI     M4503  ; 工位3开关（ON为关）
      SET     B360  ; 工位3放产品启动
      MRD
      AND=    K2B31 K0  ; 工位3复位第二步
      ANI     M4503  ; 工位3开关（ON为关）
      SET     B370  ; 工位3插模组启动
      MRD
      AND     M4503  ; 工位3开关（ON为关）
      SET     B348  ; 工位3第八步
      MPP
      RST     B340  ; 工位3启动
118   LD      B341  ; 工位3第一步
      MPS
      AND     M633  ; 3#定载座1原点
      SET     M4023  ; 3#定载座1（输出）
      MRD
      AND     M4023  ; 3#定载座1（输出）
      AND     M833  ; 3#定载座1终点
      OUT     T352 D378
      MPP
      AND     T352
      SET     B342  ; 工位3第二步
      RST     B341  ; 工位3第一步
133   LD      B342  ; 工位3第二步
      MPS
      AND     M634  ; 3#定载座2原点
      SET     M4024  ; 3#定载座2（输出）
      MRD
      AND     M4024  ; 3#定载座2（输出）
      AND     M834  ; 3#定载座2终点
      OUT     T353 D380
      MPP
      AND     T353
      SET     B343  ; 工位3第三步
      RST     B342  ; 工位3第二步
148   LD      B343  ; 工位3第三步
      MPS
      AND     M635  ; 3#压产品气缸原点
      SET     M4025  ; 3#压产品（输出）
      MRD
      AND     M4025  ; 3#压产品（输出）
      AND     M835  ; 3#压产品气缸终点
      OUT     T354 D382
      MPP
      AND     T354
      SET     B344  ; 工位3第四步
      RST     B343  ; 工位3第三步
163   LD      B344  ; 工位3第四步
      AND     B37F  ; 工位3插模组完成标志
      MPS
      AND=    D110 K1  ; 工位3装产品次数计数
      PLS     M1661  ; 7#  3#移载座轴位置2（自动）
      MRD
      AND=    D110 K2  ; 工位3装产品次数计数
      PLS     M1662  ; 7#  3#移载座轴位置3（自动）
      MRD
      AND=    D110 K3  ; 工位3装产品次数计数
      PLS     M1663  ; 7#  3#移载座轴位置4（自动）
      MRD
      AND=    D110 K4  ; 工位3装产品次数计数
      PLS     M1664  ; 7#  3#移载座轴位置5（自动）
      MRD
      AND=    D110 K5  ; 工位3装产品次数计数
      PLS     M1665  ; 7#  3#移载座轴位置6（自动）
      MRD
      AND=    D110 K6  ; 工位3装产品次数计数
      PLS     M1666  ; 7#  3#位置7
      MRD
      AND=    D110 K7  ; 工位3装产品次数计数
      PLS     M1667  ; 7#  3#位置8
      MRD
      AND=    D110 K8  ; 工位3装产品次数计数
      PLS     M1668  ; 7#  3#位置9
      MRD
      AND=    D110 K9  ; 工位3装产品次数计数
      ANI     M4515  ; 产品选择按钮（OFF为产品1）
      PLS     M1669  ; 7#  3#位置10
      MRD
      LD<>    K2M2821 K0  ; 7#  3#移载座轴在位置1
      OR      M2829  ; 7#  3#移载座轴在位置9
      OR      M2830  ; 7#  3#移载座轴在位置10
      ANB
      OUT     T360 K1
      MPP
      AND     T360
      SET     B345  ; 工位3第五步
      RST     B344  ; 工位3第四步
235   LD      B345  ; 工位3第五步
      OUT     T361 K1
      RST     B37F  ; 工位3插模组完成标志
      LD      T361
      OR      T361
      ANB
      MPS
      LD<     D110 K10  ; 工位3装产品次数计数
      ANI     M4515  ; 产品选择按钮（OFF为产品1）
      LD<     D110 K9  ; 工位3装产品次数计数
      AND     M4515  ; 产品选择按钮（OFF为产品1）
      ORB
      ANB
      SET     B344  ; 工位3第四步
      MRD
      LD>=    D110 K10  ; 工位3装产品次数计数
      ANI     M4515  ; 产品选择按钮（OFF为产品1）
      LD>=    D110 K9  ; 工位3装产品次数计数
      AND     M4515  ; 产品选择按钮（OFF为产品1）
      ORB
      ANB
      SET     B346  ; 工位3第六步
      MPP
      RST     B345  ; 工位3第五步
270   LD      B346  ; 工位3第六步
      RST     M4025  ; 3#压产品（输出）
      MPS
      ANI     M4025  ; 3#压产品（输出）
      AND     M635  ; 3#压产品气缸原点
      OUT     T362 D384
      MPP
      AND     T362
      SET     B347  ; 工位3第七步
      MOV     K0 D110
      RST     B346  ; 工位3第六步
285   LD      B347  ; 工位3第七步
      RST     M4023  ; 3#定载座1（输出）
      RST     M4024  ; 3#定载座2（输出）
      MPS
      ANI     M4023  ; 3#定载座1（输出）
      ANI     M4024  ; 3#定载座2（输出）
      AND     M633  ; 3#定载座1原点
      AND     M634  ; 3#定载座2原点
      OUT     T363 D386
      MPP
      AND     T363
      SET     B348  ; 工位3第八步
      RST     B347  ; 工位3第七步
301   LD      B348  ; 工位3第八步
      MPS
      ANI     T26
      SET     M4022  ; 3#挡载座（输出）
      MRD
      AND     M4022  ; 3#挡载座（输出）
      AND     M832  ; 3#挡载座终点
      OUT     T364 D388
      PLS     M1660  ; 7#  3#移载座轴位置1（自动）
      MPP
      AND     T364
      SET     B349  ; 工位3第九步
      RST     B348  ; 工位3第八步
318   LD      B349  ; 工位3第九步
      MPS
      AND     M2820  ; 7#  3#移载座轴在原点位置
      RST     M4022  ; 3#挡载座（输出）
      MPP
      ANI     M4022  ; 3#挡载座（输出）
      AND     M632  ; 3#挡载座原点
      SET     B340  ; 工位3启动
      RST     M102  ; 工位3前挡料互锁
      MOV     K0 D110
      MPS
      AND     M21  ; 单动状态
      PLS     M84  ; 工位3单动停止
      MPP
      RST     B349  ; 工位3第九步
335   LDI     B35F  ; 工位3吸产品段完成标志
      OR      M22  ; 自动状态
      AND     M638  ; 3#取产品气缸原点
      AND=    K1B351 K0  ; 工位3吸产品段第一步
      OUT     M64  ; 工位3吸产品段气缸在原点
342   LD      B350  ; 工位3吸产品段启动
      AND     M22  ; 自动状态
      LD      B350  ; 工位3吸产品段启动
      AND     M21  ; 单动状态
      ORB
      AND     M23  ; 启动
      ANI     M24  ; 停止
      AND     M64  ; 工位3吸产品段气缸在原点
      ANI     SM1840  ; 1#BUSY
      SET     B351  ; 工位3吸产品段第一步
      RST     B350  ; 工位3吸产品段启动
353   LD      B351  ; 工位3吸产品段第一步
      OUT     M2310  ; 3#自动拉料
      MPS
      AND     M2310  ; 3#自动拉料
      ANI     M4550  ; 2#送载带开关（ON为关）
      INCP    D510  ; 3#拉料次数计数
      MPP
      D*      D510 D1010 D5190  ; 3#料带间距 / 3#l拉料当前值比较
      D+      D5190 D512 D5196  ; 3#拉料修正
      LDI     M4550  ; 2#送载带开关（ON为关）
      AND>=   D5292 D5196  ; 3#l拉料编码器当前值
      OR      M4550  ; 2#送载带开关（ON为关）
      ANB
      SET     B352  ; 工位3吸产品段第二步
      RST     B351  ; 工位3吸产品段第一步
      RST     M2310  ; 3#自动拉料
376   LD      M23  ; 启动
      AND     B352  ; 工位3吸产品段第二步
      MPS
      AND     M2841  ; 8#  3#出载带移载在位置1
      AND     M638  ; 3#取产品气缸原点
      ANI     X3D  ; 轴2 busy
      SET     M4028  ; 3#取产品上下（输出）
      MRD
      AND     M2841  ; 8#  3#出载带移载在位置1
      AND     M4028  ; 3#取产品上下（输出）
      AND     M838  ; 3#取产品气缸终点
      OUT     T355 D390
      MPP
      AND     T355
      SET     B353  ; 工位3吸产品段第三步
      RST     B352  ; 工位3吸产品段第二步
395   LD      B353  ; 工位3吸产品段第三步
      SET     M4029  ; 3#吸产品（输出）
      MPS
      AND     M4029  ; 3#吸产品（输出）
      OUT     T346 D392
      MPP
      AND     T346
      SET     B354  ; 工位3吸产品段第四步
      RST     B353  ; 工位3吸产品段第三步
407   LD      B354  ; 工位3吸产品段第四步
      RST     M4028  ; 3#取产品上下（输出）
      MPS
      ANI     M4028  ; 3#取产品上下（输出）
      AND     M638  ; 3#取产品气缸原点
      OUT     T357 D394
      MPP
      AND     T357
      SET     B355  ; 工位3吸产品段第五步
      RST     B354  ; 工位3吸产品段第四步
420   LD      B355  ; 工位3吸产品段第五步
      MPS
      ANI     M4028  ; 3#取产品上下（输出）
      AND     M638  ; 3#取产品气缸原点
      PLS     M1761  ; 8#  3#出载带移载位置2（自动）
      MRD
      AND     M2842  ; 8#  3#出载带移载在位置2
      OUT     T358 K1
      MPP
      AND     T358
      MPS
      ANI     M220  ; 3#装料完成
      SET     B350  ; 工位3吸产品段启动
      MRD
      AND     M21  ; 单动状态
      ANI     SM400
      PLS     M85  ; 工位3吸产品单动停止
      MPP
      SET     B35F  ; 工位3吸产品段完成标志
      RST     B355  ; 工位3吸产品段第五步
445   LDI     B36F  ; 工位3放产品完成标志
      OR      M22  ; 自动状态
      ANI     X17D  ; 工位3产品感应
      AND     M638  ; 3#取产品气缸原点
      AND=    K1B361 K0  ; 工位3放产品第一步
      AND     M2842  ; 8#  3#出载带移载在位置2
      OUT     M65  ; 工位3放产品段气缸在原点
454   LD      M22  ; 自动状态
      OR      M21  ; 单动状态
      AND     M65  ; 工位3放产品段气缸在原点
      AND     B360  ; 工位3放产品启动
      AND     M23  ; 启动
      AND     B35F  ; 工位3吸产品段完成标志
      ANI     M24  ; 停止
      ANI     X17D  ; 工位3产品感应
      SET     B361  ; 工位3放产品第一步
      RST     B360  ; 工位3放产品启动
464   LD      B361  ; 工位3放产品第一步
      MPS
      AND     M638  ; 3#取产品气缸原点
      ANI     M4030  ; 3#推产品（输出）
      AND     M640  ; 3#推产品气缸原点
      ANI     X17D  ; 工位3产品感应
      ANI     M133  ; 3#放料控制（第一次）
      ANI     X3D  ; 轴2 busy
      SET     M4028  ; 3#取产品上下（输出）
      MRD
      AND     M4028  ; 3#取产品上下（输出）
      AND     X158  ; 3#吸产品上下终点2
      OUT     T359 D390
      SET     M133  ; 3#放料控制（第一次）
      MPP
      AND     T359
      SET     B362  ; 工位3放产品第二步
      RST     B361  ; 工位3放产品第一步
485   LD      B362  ; 工位3放产品第二步
      RST     M4029  ; 3#吸产品（输出）
      MPS
      ANI     M4029  ; 3#吸产品（输出）
      OUT     T371 D396
      MPP
      AND     T371
      SET     B363  ; 工位3放产品第三步
      RST     B362  ; 工位3放产品第二步
497   LD      B363  ; 工位3放产品第三步
      RST     M4028  ; 3#取产品上下（输出）
      INCP    D690  ; 3#放料次数计数
      MPS
      ANI     M4028  ; 3#取产品上下（输出）
      AND     M638  ; 3#取产品气缸原点
      OUT     T372 D394
      MPP
      AND     T372
      SET     B364  ; 工位3放产品第四步
      RST     B363  ; 工位3放产品第三步
512   LD      B364  ; 工位3放产品第四步
      MPS
      ANI     M4028  ; 3#取产品上下（输出）
      AND     M638  ; 3#取产品气缸原点
      PLS     M1760  ; 8#  3#出载带移载位置1（自动）
      MPP
      INCP    D210  ; 3#吸料次数计数
      MPS
      AND     M2841  ; 8#  3#出载带移载在位置1
      OUT     T370 K0
      MRD
      ANDP    B364  ; 工位3放产品第四步
      SET     B36F  ; 工位3放产品完成标志
      MPP
      AND     T370
      MPS
      ANI     M220  ; 3#装料完成
      SET     B360  ; 工位3放产品启动
      MRD
      AND     M82  ; 工位2放产品单动停止
      ANI     SM400
      PLS     M86  ; 工位3放产品单动停止
      MRD
      ANI     SM400
      RST     B35F  ; 工位3吸产品段完成标志
      MPP
      RST     B364  ; 工位3放产品第四步
545   LD      X17D  ; 工位3产品感应
      OR      M4521  ; 3#产品感应开关（ON为关）
      AND     M640  ; 3#推产品气缸原点
      AND     M641  ; 3#挡产品气缸原点
      AND=    K2B371 K0  ; 工位3插模组第一步
      OUT     M66  ; 工位3插模组段气缸在原点
553   LD      B370  ; 工位3插模组启动
      AND     M22  ; 自动状态
      LD      B370  ; 工位3插模组启动
      AND     M21  ; 单动状态
      ORB
      LD      X17D  ; 工位3产品感应
      OR      M4521  ; 3#产品感应开关（ON为关）
      ANB
      AND     M66  ; 工位3插模组段气缸在原点
      AND     M23  ; 启动
      ANI     M24  ; 停止
      SET     B371  ; 工位3插模组第一步
      RST     B370  ; 工位3插模组启动
566   LD      B371  ; 工位3插模组第一步
      MPS
      AND     M641  ; 3#挡产品气缸原点
      SET     M4031  ; 3#挡产品（输出）
      MPP
      RST     M135
      MPS
      AND     M4031  ; 3#挡产品（输出）
      AND     M841  ; 3#挡产品气缸终点
      OUT     T764 D400
      MPP
      AND     T764
      SET     B372  ; 工位3插模组第二步
      RST     B371  ; 工位3插模组第一步
583   LD      X17D  ; 工位3产品感应
      OR      M4521  ; 3#产品感应开关（ON为关）
      LD      M22  ; 自动状态
      ANI     M131
      LD      M21  ; 单动状态
      AND     SM400
      ORB
      OR      B36F  ; 工位3放产品完成标志
      ANB
      AND     M638  ; 3#取产品气缸原点
      ANI     M4028  ; 3#取产品上下（输出）
      OUT     M41  ; 工位3推料条件
595   LD      B372  ; 工位3插模组第二步
      OR      B370  ; 工位3插模组启动
      ANI     M135
      ANI     M4521  ; 3#产品感应开关（ON为关）
      ANI     X17D  ; 工位3产品感应
      AND     B35F  ; 工位3吸产品段完成标志
      AND     B36F  ; 工位3放产品完成标志
      MPS
      AND>=   D690 D700  ; 3#放料次数计数
      SET     M5046  ; 3#吸料异常
      MPP
      RST     M133  ; 3#放料控制（第一次）
      RST     B35F  ; 工位3吸产品段完成标志
      RST     B36F  ; 工位3放产品完成标志
611   LD      B372  ; 工位3插模组第二步
      MPS
      AND     M841  ; 3#挡产品气缸终点
      AND     M640  ; 3#推产品气缸原点
      AND     M41  ; 工位3推料条件
      SET     M4030  ; 3#推产品（输出）
      SET     M135
      MPP
      SET     M131
      MPS
      AND     M4030  ; 3#推产品（输出）
      AND     M840  ; 3#推产品气缸终点
      OUT     T365 D402
      RST     B36F  ; 工位3放产品完成标志
      MOV     K0 D690
      MPP
      AND     T365
      SET     B373  ; 工位3插模组第三步
      RST     B36F  ; 工位3放产品完成标志
      RST     B372  ; 工位3插模组第二步
635   LD      B373  ; 工位3插模组第三步
      SET     M4032  ; 3#夹产品（输出）
      MPS
      AND     M4032  ; 3#夹产品（输出）
      OUT     T366 D404
      MPP
      AND     T366
      SET     B374  ; 工位3插模组第四步
      RST     B373  ; 工位3插模组第三步
647   LD      B374  ; 工位3插模组第四步
      RST     M4031  ; 3#挡产品（输出）
      RST     M4030  ; 3#推产品（输出）
      RST     M135
      MPS
      AND     M22  ; 自动状态
      RST     M133  ; 3#放料控制（第一次）
      MPP
      MOV     K0 D210
      MPS
      ANI     M4031  ; 3#挡产品（输出）
      ANI     M4030  ; 3#推产品（输出）
      AND     M640  ; 3#推产品气缸原点
      AND     M641  ; 3#挡产品气缸原点
      OUT     T367 D406
      MPP
      AND     T367
      SET     B375  ; 工位3插模组第五步
      RST     B374  ; 工位3插模组第四步
670   LD      B375  ; 工位3插模组第五步
      MPS
      AND     B344  ; 工位3第四步
      AND     M4025  ; 3#压产品（输出）
      ANI     B37F  ; 工位3插模组完成标志
      AND     M640  ; 3#推产品气缸原点
      AND     M641  ; 3#挡产品气缸原点
      PLS     M1861  ; 9#   3#装产品轴位置2（自动）
      INCP    D110
      MRD
      AND     M2862  ; 9#  3#装产品轴在位置2
      OUT     T368 K0
      MPP
      AND     T368
      SET     B376  ; 工位3插模组第六步
      RST     B375  ; 工位3插模组第五步
691   LD      B376  ; 工位3插模组第六步
      RST     M4032  ; 3#夹产品（输出）
      INCP    D300  ; 总产能
      INCP    D302  ; 当前产能
      MPS
      ANI     M4032  ; 3#夹产品（输出）
      OUT     T369 D408
      MPP
      AND     T369
      SET     B377  ; 工位3插模组第七步
      RST     B376  ; 工位3插模组第六步
707   LD      B377  ; 工位3插模组第七步
      PLS     M1860  ; 9#   3#装产品轴位置1（自动）
      MPS
      LD>=    D110 K10  ; 工位3装产品次数计数
      ANI     M4515  ; 产品选择按钮（OFF为产品1）
      LD>=    D110 K9  ; 工位3装产品次数计数
      AND     M4515  ; 产品选择按钮（OFF为产品1）
      ORB
      ANB
      AND     M21  ; 单动状态
      SET     M220  ; 3#装料完成
      BKRST   B350 K5
      MPP
      AND     M2861  ; 9#  3#装产品轴在位置1
      MPS
      LDI     M220  ; 3#装料完成
      LD<     D110 K10  ; 工位3装产品次数计数
      ANI     M4515  ; 产品选择按钮（OFF为产品1）
      LD<     D110 K9  ; 工位3装产品次数计数
      AND     M4515  ; 产品选择按钮（OFF为产品1）
      ORB
      AND     M22  ; 自动状态
      ORB
      ANB
      SET     B370  ; 工位3插模组启动
      MRD
      AND     M21  ; 单动状态
      PLS     M87  ; 工位3装产品单动停止
      RST     B35F  ; 工位3吸产品段完成标志
      RST     B36F  ; 工位3放产品完成标志
      RST     M133  ; 3#放料控制（第一次）
      MPP
      SET     B37F  ; 工位3插模组完成标志
      RST     B377  ; 工位3插模组第七步
753   END
END_PROGRAM

PROGRAM 工站4
0     LD      M651  ; 4#前挡气缸1原点
      ANI     M4041  ; 4#前挡载座1（输出）
      AND     M653  ; 4#前挡气缸2原点
      ANI     M4043  ; 4#前挡载座2（输出）
      AND     M672  ; 4#前挡载座载座到位感应
      OUT     M185
6     LD      M22  ; 自动状态
      OR      M21  ; 单动状态
      LDI     X17E  ; 4#挡载座1到位感应
      OR      M123  ; 工位4前挡放料条件
      ANB
      AND     M23  ; 启动
      ANI     M24  ; 停止
      ANI     M103  ; 工位4前挡料互锁
      MPS
      ANI     M4041  ; 4#前挡载座1（输出）
      AND     M185
      SET     M4041  ; 4#前挡载座1（输出）
      MRD
      AND     M4041  ; 4#前挡载座1（输出）
      AND     M851  ; 4#前挡气缸1终点
      OUT     T380 D410
      MRD
      AND     T380
      SET     M4043  ; 4#前挡载座2（输出）
      MPP
      AND     M4043  ; 4#前挡载座2（输出）
      SET     M103  ; 工位4前挡料互锁
      SET     M123  ; 工位4前挡放料条件
32    LD      M4043  ; 4#前挡载座2（输出）
      MPS
      AND     M853  ; 4#前挡气缸2终点
      OUT     T381 D412
      MPP
      AND     T381
      RST     M4043  ; 4#前挡载座2（输出）
      RST     M4041  ; 4#前挡载座1（输出）
43    LD=     K1M643 K15  ; 4#挡载座1气缸原点
      AND=    K2B401 K0  ; 工位4第一步
      AND     M646  ; 4#定载座2气缸原点
      AND     M647  ; 4#定载座3气缸原点
      AND     M648  ; 4#顶载座气缸原点
      AND     M650  ; 升降气缸原点
      OUT     M76  ; 工位4所有气缸在原点
54    LD      X17E  ; 4#挡载座1到位感应
      OUT     T20 K5
59    LD      B400  ; 工位4启动
      AND     M22  ; 自动状态
      LD      B400  ; 工位4启动
      AND     M21  ; 单动状态
      ORB
      AND     T20
      AND     M23  ; 启动
      ANI     M24  ; 停止
      AND     M76  ; 工位4所有气缸在原点
      SET     B401  ; 工位4第一步
      RST     B400  ; 工位4启动
70    LD      B401  ; 工位4第一步
      MPS
      AND     M644  ; 4#定载座1气缸原点
      AND     M646  ; 4#定载座2气缸原点
      SET     M4034  ; 4#定载座1（输出）
      SET     M4037  ; 4#定载座3（输出）
      MRD
      AND     M4034  ; 4#定载座1（输出）
      AND     M4037  ; 4#定载座3（输出）
      AND     M844  ; 4#定载座1气缸终点
      AND     M847  ; 4#定载座3气缸终点
      OUT     T383 D414
      MPP
      AND     T383
      SET     B402  ; 工位4第二步
      RST     B401  ; 工位4第一步
89    LD      B402  ; 工位4第二步
      MPS
      ANI     M673  ; 降载座工位载座到位感应
      AND     M650  ; 升降气缸原点
      ANI     X17C  ; 降载座感应
      PLS     M1961  ; 10#  4#移载座轴位置2（自动）
      MRD
      AND     M2882  ; 10#  4#移载座轴在位置2
      OUT     T384 K1
      MPP
      AND     T384
      SET     B403  ; 工位4第三步
      RST     B402  ; 工位4第二步
106   LD      B403  ; 工位4第三步
      MPS
      AND     M646  ; 4#定载座2气缸原点
      SET     M4036  ; 4#定载座2（输出）
      MRD
      AND     M4036  ; 4#定载座2（输出）
      AND     M846  ; 4#定载座2气缸终点
      OUT     T385 D416
      RST     M4037  ; 4#定载座3（输出）
      MPP
      ANI     M4037  ; 4#定载座3（输出）
      AND     T385
      SET     B404  ; 工位4第四步
      RST     B403  ; 工位4第三步
123   LD      B404  ; 工位4第四步
      PLS     M2461  ; 11#  4#取产品上下轴位置2（自动）
      MPS
      AND     M2602  ; 11#   4#取产品上下轴在位置2
      OUT     T386 K1
      MPP
      AND     T386
      MPS
      ANI     M4504  ; 工位4开关（ON为开）
      SET     B405  ; 工位4第五步
      MRD
      AND     M4504  ; 工位4开关（ON为开）
      SET     B408  ; 工位4第八步
      MPP
      RST     B404  ; 工位4第四步
142   LD      B405  ; 工位4第五步
      MPS
      AND     M648  ; 4#顶载座气缸原点
      SET     M4038  ; 4#顶载座（输出）
      MRD
      AND     M4038  ; 4#顶载座（输出）
      OUT     T387 D418
      MPP
      AND     T387
      SET     B406  ; 工位4第六步
      RST     B405  ; 工位4第五步
156   LD      B406  ; 工位4第六步
      MPS
      AND     M649  ; 4#夹产品气缸原点
      SET     M4039  ; 4#夹产品（输出）
      MRD
      AND     M4039  ; 4#夹产品（输出）
      AND     M849  ; 4#夹产品气缸终点
      OUT     T388 D420
      MPP
      AND     T388
      SET     B407  ; 工位4第七步
      RST     B406  ; 工位4第六步
171   LD      B407  ; 工位4第七步
      PLS     M2460  ; 11#  4#取产品上下轴位置1（自动）
      MPS
      AND     M2601  ; 11#   4#取产品上下轴在位置1
      OUT     T389 K1
      MPP
      AND     T389
      SET     B408  ; 工位4第八步
      RST     M4038  ; 4#顶载座（输出）
      SET     B410  ; 工位4分段动作第一步
      RST     B407  ; 工位4第七步
186   LD      B410  ; 工位4分段动作第一步
      MPS
      AND     M2601  ; 11#   4#取产品上下轴在位置1
      AND=    K1B411 K0  ; 工位4分段动作第二步
      PLS     M6061  ; 12#  4#入回流焊轴位置2（自动）
      MRD
      AND     M2622  ; 12#   4#入回流焊轴在位置2
      OUT     T400 K1
      MPP
      AND     T400
      SET     B411  ; 工位4分段动作第二步
      RST     B410  ; 工位4分段动作第一步
204   LD      B411  ; 工位4分段动作第二步
      PLS     M2462  ; 11#  4#取产品上下轴位置3（自动）
      MPS
      AND     M2603  ; 11#   4#取产品上下轴在位置3
      OUT     T401 K1
      MPP
      AND     T401
      SET     B412  ; 工位4分段动作第三步
      RST     B411  ; 工位4分段动作第二步
217   LD      B412  ; 工位4分段动作第三步
      RST     M4039  ; 4#夹产品（输出）
      MPS
      ANI     M4039  ; 4#夹产品（输出）
      AND     M649  ; 4#夹产品气缸原点
      OUT     T402 D422
      MPP
      AND     T402
      SET     B413  ; 工位4分段动作第四步
      RST     B412  ; 工位4分段动作第三步
230   LD      B413  ; 工位4分段动作第四步
      PLS     M2469  ; 11#  4#取产品上下轴位置1（自动）
      MPS
      AND     M2601  ; 11#   4#取产品上下轴在位置1
      OUT     T403 K0
      MPP
      AND     T403
      SET     B414  ; 工位4分段动作第五步
      RST     B413  ; 工位4分段动作第四步
243   LD      B414  ; 工位4分段动作第五步
      PLS     M6060  ; 12#  4#入回流焊轴位置1（自动）
      AND     M2621  ; 12#   4#入回流焊轴在位置1
      SET     B415  ; 工位4分段动作第六步
      RST     B414  ; 工位4分段动作第五步
249   LD      B408  ; 工位4第八步
      RST     M4037  ; 4#定载座3（输出）
      RST     M4036  ; 4#定载座2（输出）
      RST     M4034  ; 4#定载座1（输出）
      MPS
      ANI     M4037  ; 4#定载座3（输出）
      ANI     M4036  ; 4#定载座2（输出）
      ANI     M4034  ; 4#定载座1（输出）
      AND     M647  ; 4#定载座3气缸原点
      AND     M646  ; 4#定载座2气缸原点
      AND     M644  ; 4#定载座1气缸原点
      OUT     T390 D424
      MPP
      AND     T390
      SET     B409  ; 工位4第九步
      RST     B408  ; 工位4第八步
268   LD      B409  ; 工位4第九步
      MPS
      AND     M643  ; 4#挡载座1气缸原点
      SET     M4033  ; 4#挡载座1（输出）
      MRD
      AND     M645  ; 4#挡载座2气缸原点
      SET     M4035  ; 4#挡载座2（输出）
      MRD
      AND     M4033  ; 4#挡载座1（输出）
      AND     M4035  ; 4#挡载座2（输出）
      AND     M843  ; 4#挡载座1气缸终点
      AND     M845  ; 4#挡载座2气缸终点
      OUT     T391 D426
      MPP
      AND     T391
      SET     B40A  ; 工位4第十步
      RST     B409  ; 工位4第九步
288   LD      B40A  ; 工位4第十步
      PLS     M1960  ; 10#  4#移载座轴位置1（自动）
      MPS
      AND     M2881  ; 10#  4#移载座轴在位置1
      OUT     T392 K1
      MPP
      AND     T392
      SET     B40B  ; 工位4第十一步
      RST     B40A  ; 工位4第十步
301   LD      B40B  ; 工位4第十一步
      RST     M4033  ; 4#挡载座1（输出）
      RST     M4035  ; 4#挡载座2（输出）
      MPS
      ANI     M4033  ; 4#挡载座1（输出）
      ANI     M4035  ; 4#挡载座2（输出）
      AND     M643  ; 4#挡载座1气缸原点
      AND     M645  ; 4#挡载座2气缸原点
      OUT     T393 D428
      MPP
      AND     T393
      SET     B40C  ; 工位4第十二步
      RST     M103  ; 工位4前挡料互锁
      RST     B40B  ; 工位4第十一步
318   LD      B415  ; 工位4分段动作第六步
      OR      M4504  ; 工位4开关（ON为开）
      AND     B40C  ; 工位4第十二步
      SET     B400  ; 工位4启动
      MPS
      AND     M21  ; 单动状态
      PLS     M88  ; 工位4单动停止
      MPP
      SET     B40F
      RST     B415  ; 工位4分段动作第六步
      RST     B40C  ; 工位4第十二步
330   END
END_PROGRAM

PROGRAM 工站5（降载座）
0     LD=     K1B421 K0  ; 升载座工位第一步
      AND     M639  ; 降载座工位卸载座原点
      AND     M650  ; 升降气缸原点
      AND     X17C  ; 降载座感应
      OUT     M77  ; 降载座工位在原点
7     LD      M22  ; 自动状态
      OR      M21  ; 单动状态
      AND     B420  ; 升载座启动
      AND     M77  ; 降载座工位在原点
      AND     M23  ; 启动
      ANI     M24  ; 停止
      SET     B421  ; 升载座工位第一步
14    LD      B421  ; 升载座工位第一步
      MPS
      ANI     M4037  ; 4#定载座3（输出）
      AND     M647  ; 4#定载座3气缸原点
      AND     M650  ; 升降气缸原点
      SET     M4040  ; 升降气缸（输出）
      MRD
      AND     M4040  ; 升降气缸（输出）
      AND     M850  ; 升降气缸终点
      OUT     T410 D430
      MPP
      AND     T410
      SET     B422  ; 升载座工位第二步
      RST     B421  ; 升载座工位第一步
31    LD      B422  ; 升载座工位第二步
      MPS
      AND     M639  ; 降载座工位卸载座原点
      SET     M4060  ; 降载座工位卸载座
      MRD
      AND     M4060  ; 降载座工位卸载座
      AND     M839  ; 降载座工位卸载座终点
      OUT     T411 D432
      MPP
      AND     T411
      SET     B423  ; 升载座工位第三步
      RST     B422  ; 升载座工位第二步
46    LD      B423  ; 升载座工位第三步
      RST     M4060  ; 降载座工位卸载座
      MPS
      ANI     M4060  ; 降载座工位卸载座
      AND     M639  ; 降载座工位卸载座原点
      OUT     T412 D434
      MPP
      AND     T412
      SET     B424  ; 升载座工位第四步
      RST     B423  ; 升载座工位第三步
59    LD      B424  ; 升载座工位第四步
      RST     M4040  ; 升降气缸（输出）
      MPS
      ANI     M4040  ; 升降气缸（输出）
      AND     M650  ; 升降气缸原点
      OUT     T413 D436
      MPP
      AND     T413
      RST     B424  ; 升载座工位第四步
71    END
END_PROGRAM

PROGRAM 手动
0     LD      M20  ; 手动状态
      MC      N0 M18
3     LDP     M18
      ORF     M17  ; 急停（外部按钮）
      BKRST   B200 K300  ; 升载座工位启动
      MOV     K0 D100  ; 工位2装产品次数计数
      MOV     K0 D120  ; 点胶A面产品点胶次数计数
      MOV     K0 D140  ; 工位3测试次数计数
      MOV     K0 D150  ; 工位4测试次数计数
      MOV     K0 D160
      MOV     K0 D122
      BKRST   M100 K300  ; 工位1前挡料1互锁
      BKRST   B101 K10  ; 马达原点回归第二步
      BKRST   M300 K300
29    LDP     M18
      ORF     M17  ; 急停（外部按钮）
      SET     B0
      SET     B10  ; 工位1复位第一步
      SET     B20  ; 工位2复位第一步
      SET     B30  ; 工位3复位第一步
      SET     B40  ; 工位4复位第一步
      SET     B50  ; 降载座复位第一步
      SET     M90
38    LDP     M3000  ; 下挡载座(手动)
      FF      M4000  ; 下挡载座（输出）
41    LDP     M3001  ; 卸载座(手动)
      FF      M4001  ; 卸载座（输出）
44    LDP     M3002  ; 载座升降(手动)
      FF      M4002  ; 载座升降（输出）
47    LDP     M3003  ; 1#前挡载座1(手动)
      FF      M4003  ; 1#前挡载座1（输出）
50    LDP     M3004  ; 1#挡载座(手动)
      FF      M4004  ; 1#挡载座（输出）
53    LDP     M3005  ; 1#定载座1(手动)
      FF      M4005  ; 1#定载座1（输出）
56    LDP     M3006  ; 1#定载座2(手动)
      FF      M4006  ; 1#定载座2（输出）
59    LDP     M3007  ; 2#前挡载座1(手动)
      FF      M4007  ; 2#前挡载座1（输出）
62    LDP     M3008  ; 2#前挡载座2(手动)
      FF      M4008  ; 2#前挡载座2（输出）
65    LDP     M3009  ; 2#挡载座(手动)
      FF      M4009  ; 2#挡载座（输出）
68    LDP     M3010  ; 2#定载座1(手动)
      FF      M4010  ; 2#定载座1（输出）
71    LDP     M3011  ; 2#定载座2(手动)
      FF      M4011  ; 2#定载座2（输出）
74    LDP     M3012  ; 2#压产品(手动)
      FF      M4012  ; 2#压产品（输出）
77    LDP     M3015  ; 2#取产品上下(手动)
      FF      M4015  ; 2#取产品上下输出
80    LDP     M3016  ; 2#吸产品(手动)
      FF      M4016  ; 2#吸产品（输出）
83    LDP     M3017  ; 2#推产品(手动)
      AND     M4018  ; 2#挡产品（输出）
      AND     M818  ; 2#挡产品气缸终点
      LDP     M3017  ; 2#推产品(手动)
      AND     M4017  ; 2#推产品（输出）
      AND     M4019  ; 2#夹产品（输出）
      ORB
      FF      M4017
92    LDP     M3018  ; 2#挡产品(手动)
      FF      M4018
95    LDP     M3019  ; 2#夹产品(手动)
      FF      M4019
98    LDP     M3020  ; 3#前挡载座1(手动)
      FF      M4020  ; 3#前挡载座1（输出）
101   LDP     M3021  ; 3#前挡载座2(手动)
      FF      M4021  ; 3#前挡载座2（输出）
104   LDP     M3022  ; 3#挡载座(手动)
      FF      M4022  ; 3#挡载座（输出）
107   LDP     M3023  ; 3#定载座1(手动)
      FF      M4023  ; 3#定载座1（输出）
110   LDP     M3024  ; 3#定载座2(手动)
      FF      M4024  ; 3#定载座2（输出）
113   LDP     M3025  ; 3#压产品(手动)
      FF      M4025  ; 3#压产品（输出）
116   LDP     M3028  ; 3#取产品上下(手动)
      FF      M4028  ; 3#取产品上下（输出）
119   LDP     M3029  ; 3#吸产品(手动)
      FF      M4029  ; 3#吸产品（输出）
122   LDP     M3030  ; 3#推产品(手动)
      AND     M4031  ; 3#挡产品（输出）
      AND     M841  ; 3#挡产品气缸终点
      LDP     M3030  ; 3#推产品(手动)
      AND     M4030  ; 3#推产品（输出）
      AND     M4032  ; 3#夹产品（输出）
      ORB
      FF      M4030
131   LDP     M3031  ; 3#挡产品(手动)
      FF      M4031
134   LDP     M3032  ; 3#夹产品(手动)
      FF      M4032
137   LDP     M3033  ; 4#挡载座1(手动)
      FF      M4033  ; 4#挡载座1（输出）
140   LDP     M3034  ; 4#定载座1(手动)
      FF      M4034  ; 4#定载座1（输出）
143   LDP     M3060
      FF      M4060  ; 降载座工位卸载座
146   LDP     M3035  ; 4#挡载座2(手动)
      FF      M4035  ; 4#挡载座2（输出）
149   LDP     M3036  ; 4#定载座2(手动)
      FF      M4036  ; 4#定载座2（输出）
152   LDP     M3037  ; 4#定载座3(手动)
      FF      M4037  ; 4#定载座3（输出）
155   LDP     M3038  ; 4#顶载座(手动)
      FF      M4038  ; 4#顶载座（输出）
158   LDP     M3039  ; 4#夹产品(手动)
      FF      M4039  ; 4#夹产品（输出）
161   LDP     M3040  ; 升降气缸(手动)
      FF      M4040  ; 升降气缸（输出）
164   LDP     M3041  ; 4#前挡载座1(手动)
      FF      M4041  ; 4#前挡载座1（输出）
167   LDP     M3042  ; 1#前挡载座2(手动)
      FF      M4042  ; 1#前挡载座2（输出）
170   LDP     M3043  ; 4#前挡载座2(手动)
      FF      M4043  ; 4#前挡载座2（输出）
173   END
END_PROGRAM

PROGRAM 报警
0     LDI     M4000  ; 下挡载座（输出）
      AND     M600  ; 下挡载座气缸原点
      ANI     M800  ; 下挡载座气缸终点
      LD      M4000  ; 下挡载座（输出）
      ANI     M600  ; 下挡载座气缸原点
      AND     M800  ; 下挡载座气缸终点
      ORB
      INV
      OUT     T1000 K20
      AND     T1000
      SET     M5000  ; 下挡载座（报警）
14    LDI     M4001  ; 卸载座（输出）
      AND     M601  ; 卸载座气缸原点
      ANI     M801  ; 卸载座气缸终点
      LD      M4001  ; 卸载座（输出）
      ANI     M601  ; 卸载座气缸原点
      AND     M801  ; 卸载座气缸终点
      ORB
      INV
      OUT     T1001 K20
      AND     T1001
      SET     M5001  ; 卸载座（报警）
28    LDI     M4002  ; 载座升降（输出）
      AND     M602  ; 载座升降气缸原点
      ANI     M802  ; 载座升降气缸终点
      LD      M4002  ; 载座升降（输出）
      ANI     M602  ; 载座升降气缸原点
      AND     M802  ; 载座升降气缸终点
      ORB
      INV
      OUT     T1002 K30
      AND     T1002
      SET     M5002  ; 载座升降（报警）
42    LDI     M4003  ; 1#前挡载座1（输出）
      AND     M603  ; 1#前挡载座1气缸原点
      ANI     M803  ; 1#前挡载座1气缸终点
      LD      M4003  ; 1#前挡载座1（输出）
      ANI     M603  ; 1#前挡载座1气缸原点
      AND     M803  ; 1#前挡载座1气缸终点
      ORB
      INV
      OUT     T1003 K20
      AND     T1003
      ANI     SM400
      SET     M5003  ; 1#前挡载座1（报警）
57    LDI     M4004  ; 1#挡载座（输出）
      AND     M604  ; 1#挡载座气缸原点
      ANI     M804  ; 1#挡载座气缸终点
      LD      M4004  ; 1#挡载座（输出）
      ANI     M604  ; 1#挡载座气缸原点
      AND     M804  ; 1#挡载座气缸终点
      ORB
      INV
      OUT     T1004 K20
      AND     T1004
      SET     M5004  ; 1#挡载座（报警）
71    LDI     M4005  ; 1#定载座1（输出）
      AND     M605  ; 1#定载座1气缸原点
      ANI     M805  ; 1#定载座1气缸终点
      LD      M4005  ; 1#定载座1（输出）
      ANI     M605  ; 1#定载座1气缸原点
      AND     M805  ; 1#定载座1气缸终点
      ORB
      INV
      OUT     T1005 K20
      AND     T1005
      SET     M5005  ; 1#定载座1（报警）
85    LDI     M4006  ; 1#定载座2（输出）
      AND     M606  ; 1#定载座2气缸原点
      ANI     M806  ; 1#定载座2气缸终点
      LD      M4006  ; 1#定载座2（输出）
      ANI     M606  ; 1#定载座2气缸原点
      AND     M806  ; 1#定载座2气缸终点
      ORB
      INV
      OUT     T1006 K20
      AND     T1006
      SET     M5006  ; 1#定载座2（报警）
99    LDI     M4007  ; 2#前挡载座1（输出）
      AND     M607  ; 2#前挡载座1气缸原点
      ANI     M807  ; 2#前挡载座1气缸终点
      LD      M4007  ; 2#前挡载座1（输出）
      ANI     M607  ; 2#前挡载座1气缸原点
      AND     M807  ; 2#前挡载座1气缸终点
      ORB
      INV
      OUT     T1007 K20
      AND     T1007
      SET     M5007  ; 2#前挡载座1（报警）
113   LDI     M4008  ; 2#前挡载座2（输出）
      AND     M608  ; 2#前挡载座2气缸原点
      ANI     M808  ; 2#前挡载座2气缸终点
      LD      M4008  ; 2#前挡载座2（输出）
      ANI     M608  ; 2#前挡载座2气缸原点
      AND     M808  ; 2#前挡载座2气缸终点
      ORB
      INV
      OUT     T1008 K20
      AND     T1008
      SET     M5008  ; 2#前挡载座2（报警）
127   LDI     M4009  ; 2#挡载座（输出）
      AND     M609  ; 2#挡载座气缸原点
      ANI     M809  ; 2#挡载座气缸终点
      LD      M4009  ; 2#挡载座（输出）
      ANI     M609  ; 2#挡载座气缸原点
      AND     M809  ; 2#挡载座气缸终点
      ORB
      INV
      OUT     T1009 K20
      AND     T1009
      SET     M5009  ; 2#挡载座（报警）
141   LDI     M4010  ; 2#定载座1（输出）
      AND     M610  ; 2#定载座1气缸原点
      ANI     M810  ; 2#定载座1气缸终点
      LD      M4010  ; 2#定载座1（输出）
      ANI     M610  ; 2#定载座1气缸原点
      AND     M810  ; 2#定载座1气缸终点
      ORB
      INV
      OUT     T1010 K20
      AND     T1010
      SET     M5010  ; 2#定载座1（报警）
155   LDI     M4011  ; 2#定载座2（输出）
      AND     M611  ; 2#定载座2气缸原点
      ANI     M811  ; 2#定载座2气缸终点
      LD      M4011  ; 2#定载座2（输出）
      ANI     M611  ; 2#定载座2气缸原点
      AND     M811  ; 2#定载座2气缸终点
      ORB
      INV
      OUT     T1011 K20
      AND     T1011
      SET     M5011  ; 2#定载座2（报警）
169   LDI     M4012  ; 2#压产品（输出）
      AND     M612  ; 2#压产品气缸原点
      ANI     M812  ; 2#压产品气缸终点
      LD      M4012  ; 2#压产品（输出）
      ANI     M612  ; 2#压产品气缸原点
      AND     M812  ; 2#压产品气缸终点
      ORB
      INV
      OUT     T1012 K20
      AND     T1012
      SET     M5012  ; 2#压产品（报警）
183   LDI     M4013  ; 2#压载带1（输出）
      AND     M613  ; 2#压载带1气缸原点
      ANI     M813  ; 2#压载带1气缸终点
      LD      M4013  ; 2#压载带1（输出）
      ANI     M613  ; 2#压载带1气缸原点
      AND     M813  ; 2#压载带1气缸终点
      ORB
      INV
      MPS
      ANI     SM400
      OUT     T1013 K20
      MPP
      AND     T1013
      SET     M5013  ; 2#压载带1（报警）
200   LDI     M4014  ; 2#压载带2（输出）
      AND     M614  ; 2#压载带2气缸原点
      ANI     M814  ; 2#压载带2气缸终点
      LD      M4014  ; 2#压载带2（输出）
      ANI     M614  ; 2#压载带2气缸原点
      AND     M814  ; 2#压载带2气缸终点
      ORB
      INV
      MPS
      ANI     SM400
      OUT     T1014 K20
      MPP
      AND     T1014
      ANI     SM400
      SET     M5014  ; 2#压载带2（报警）
218   LDI     M4015  ; 2#取产品上下输出
      ANI     M615  ; 2#取产品上下气缸原点
      LD      M2781  ; 5#  2#出载带移载在位置1
      AND     M4015  ; 2#取产品上下输出
      ANI     M815  ; 2#取产品上下终点
      ORB
      LD      M2782  ; 5#  2#出载带移载在位置2
      AND     M4015  ; 2#取产品上下输出
      ANI     X136  ; 2#吸产品上下终点2
      ORB
      OUT     T1015 K20
      AND     T1015
      SET     M5015  ; 2#取产品上下（报警）
234   LDI     M4016  ; 2#吸产品（输出）
      AND     M616  ; 2#吸产品气缸原点
      ANI     M816  ; 2#吸产品气缸终点
      LD      M4041  ; 4#前挡载座1（输出）
      ANI     M641  ; 3#挡产品气缸原点
      AND     M841  ; 3#挡产品气缸终点
      ORB
      INV
      MPS
      ANI     SM400
      OUT     T1016 K20
      MPP
      AND     T1016
      ANI     SM400
      SET     M5016  ; 2#吸产品（报警）
252   LDI     M4017  ; 2#推产品（输出）
      AND     M617  ; 2#推产品气缸原点
      ANI     M817  ; 2#推产品气缸终点
      LD      M4017  ; 2#推产品（输出）
      ANI     M617  ; 2#推产品气缸原点
      AND     M817  ; 2#推产品气缸终点
      ORB
      INV
      OUT     T1017 K20
      AND     T1017
      SET     M5017  ; 2#推产品（报警）
266   LDI     M4018  ; 2#挡产品（输出）
      AND     M618  ; 2#挡产品气缸原点
      ANI     M818  ; 2#挡产品气缸终点
      LD      M4018  ; 2#挡产品（输出）
      ANI     M618  ; 2#挡产品气缸原点
      AND     M818  ; 2#挡产品气缸终点
      ORB
      INV
      OUT     T1018 K20
      AND     T1018
      SET     M5018  ; 2#挡产品（报警）
280   LDI     M4019  ; 2#夹产品（输出）
      AND     M619  ; 2#夹产品气缸原点
      ANI     M819  ; 3#载座满料感应
      LD      M4019  ; 2#夹产品（输出）
      ANI     M619  ; 2#夹产品气缸原点
      AND     M819  ; 3#载座满料感应
      ORB
      INV
      OUT     T1019 K20
      AND     T1019
      ANI     SM400
      SET     M5019  ; 2#夹产品（报警）
295   LDI     M4020  ; 3#前挡载座1（输出）
      AND     M630  ; 3#前挡载座1原点
      ANI     M830  ; 3#前挡载座1终点
      LD      M4020  ; 3#前挡载座1（输出）
      ANI     M630  ; 3#前挡载座1原点
      AND     M830  ; 3#前挡载座1终点
      ORB
      INV
      OUT     T1020 K20
      AND     T1020
      SET     M5020  ; 3#前挡载座1（报警）
309   LDI     M4021  ; 3#前挡载座2（输出）
      AND     M631  ; 3#前挡载座2原点
      ANI     M831  ; 3#前挡载座2终点
      LD      M4021  ; 3#前挡载座2（输出）
      ANI     M631  ; 3#前挡载座2原点
      AND     M831  ; 3#前挡载座2终点
      ORB
      INV
      OUT     T1021 K20
      AND     T1021
      SET     M5021  ; 3#前挡载座2（报警）
323   LDI     M4022  ; 3#挡载座（输出）
      AND     M632  ; 3#挡载座原点
      ANI     M832  ; 3#挡载座终点
      LD      M4022  ; 3#挡载座（输出）
      ANI     M632  ; 3#挡载座原点
      AND     M832  ; 3#挡载座终点
      ORB
      INV
      OUT     T1022 K20
      AND     T1022
      SET     M5022  ; 3#挡载座（报警）
337   LDI     M4023  ; 3#定载座1（输出）
      AND     M633  ; 3#定载座1原点
      ANI     M833  ; 3#定载座1终点
      LD      M4023  ; 3#定载座1（输出）
      ANI     M633  ; 3#定载座1原点
      AND     M833  ; 3#定载座1终点
      ORB
      INV
      OUT     T1023 K20
      AND     T1023
      SET     M5023  ; 3#定载座1（报警）
351   LDI     M4024  ; 3#定载座2（输出）
      AND     M634  ; 3#定载座2原点
      ANI     M834  ; 3#定载座2终点
      LD      M4024  ; 3#定载座2（输出）
      ANI     M634  ; 3#定载座2原点
      AND     M834  ; 3#定载座2终点
      ORB
      INV
      OUT     T1024 K20
      AND     T1024
      SET     M5024  ; 3#定载座2（报警）
365   LDI     M4025  ; 3#压产品（输出）
      AND     M635  ; 3#压产品气缸原点
      ANI     M835  ; 3#压产品气缸终点
      LD      M4025  ; 3#压产品（输出）
      ANI     M635  ; 3#压产品气缸原点
      AND     M835  ; 3#压产品气缸终点
      ORB
      INV
      OUT     T1025 K20
      AND     T1025
      SET     M5025  ; 3#压产品（报警）
379   LDI     M4026  ; 3#压载带1（输出）
      AND     M636  ; 3#压载带1气缸原点
      ANI     M836  ; 3#压载带1气缸终点
      LD      M4026  ; 3#压载带1（输出）
      ANI     M636  ; 3#压载带1气缸原点
      AND     M836  ; 3#压载带1气缸终点
      ORB
      INV
      MPS
      ANI     SM400
      OUT     T1026 K20
      MPP
      AND     T1026
      ANI     SM400
      SET     M5026  ; 3#压载带1（报警）
397   LDI     M4027  ; 3#压载带2（输出）
      AND     M637  ; 3#压载带2气缸原点
      ANI     M837  ; 3#压载带2气缸终点
      LD      M4027  ; 3#压载带2（输出）
      ANI     M637  ; 3#压载带2气缸原点
      AND     M837  ; 3#压载带2气缸终点
      ORB
      INV
      MPS
      ANI     SM400
      OUT     T1027 K20
      MPP
      AND     T1027
      ANI     SM400
      SET     M5027  ; 3#压载带2（报警）
415   LDI     M4028  ; 3#取产品上下（输出）
      ANI     M638  ; 3#取产品气缸原点
      LD      M2841  ; 8#  3#出载带移载在位置1
      AND     M4028  ; 3#取产品上下（输出）
      ANI     M838  ; 3#取产品气缸终点
      ORB
      LD      M2842  ; 8#  3#出载带移载在位置2
      AND     M4028  ; 3#取产品上下（输出）
      ANI     X158  ; 3#吸产品上下终点2
      ORB
      OUT     T1028 K20
      AND     T1028
      SET     M5028  ; 3#取产品上下（报警）
431   LDI     M4060  ; 降载座工位卸载座
      AND     M639  ; 降载座工位卸载座原点
      ANI     M839  ; 降载座工位卸载座终点
      LD      M4060  ; 降载座工位卸载座
      ANI     M639  ; 降载座工位卸载座原点
      AND     M839  ; 降载座工位卸载座终点
      ORB
      INV
      OUT     T1029 K20
      AND     T1029
      SET     M5029  ; 3#吸产品（报警）
445   LDI     M4030  ; 3#推产品（输出）
      AND     M640  ; 3#推产品气缸原点
      ANI     M840  ; 3#推产品气缸终点
      LD      M4030  ; 3#推产品（输出）
      ANI     M640  ; 3#推产品气缸原点
      AND     M840  ; 3#推产品气缸终点
      ORB
      INV
      OUT     T1030 K20
      AND     T1030
      SET     M5030  ; 3#推产品（报警）
459   LDI     M4031  ; 3#挡产品（输出）
      AND     M641  ; 3#挡产品气缸原点
      ANI     M841  ; 3#挡产品气缸终点
      LD      M4031  ; 3#挡产品（输出）
      ANI     M641  ; 3#挡产品气缸原点
      AND     M841  ; 3#挡产品气缸终点
      ORB
      INV
      OUT     T1031 K20
      AND     T1031
      SET     M5031  ; 3#挡产品（报警）
473   LDI     M4032  ; 3#夹产品（输出）
      AND     M642  ; 3#夹产品气缸原点
      ANI     M842  ; 3#夹产品气缸终点
      LD      M4032  ; 3#夹产品（输出）
      ANI     M642  ; 3#夹产品气缸原点
      AND     M842  ; 3#夹产品气缸终点
      ORB
      INV
      MPS
      ANI     SM400
      OUT     T1032 K20
      MPP
      AND     T1032
      SET     M5032  ; 3#夹产品（报警）
490   LDI     M4033  ; 4#挡载座1（输出）
      AND     M643  ; 4#挡载座1气缸原点
      ANI     M843  ; 4#挡载座1气缸终点
      LD      M4033  ; 4#挡载座1（输出）
      ANI     M643  ; 4#挡载座1气缸原点
      AND     M843  ; 4#挡载座1气缸终点
      ORB
      INV
      OUT     T1033 K20
      AND     T1033
      SET     M5033  ; 4#挡载座1（报警）
504   LDI     M4034  ; 4#定载座1（输出）
      AND     M644  ; 4#定载座1气缸原点
      ANI     M844  ; 4#定载座1气缸终点
      LD      M4034  ; 4#定载座1（输出）
      ANI     M644  ; 4#定载座1气缸原点
      AND     M844  ; 4#定载座1气缸终点
      ORB
      INV
      OUT     T1034 K20
      AND     T1034
      SET     M5034  ; 4#定载座1（报警）
518   LDI     M4035  ; 4#挡载座2（输出）
      AND     M645  ; 4#挡载座2气缸原点
      ANI     M845  ; 4#挡载座2气缸终点
      LD      M4035  ; 4#挡载座2（输出）
      ANI     M645  ; 4#挡载座2气缸原点
      AND     M845  ; 4#挡载座2气缸终点
      ORB
      INV
      OUT     T1035 K20
      AND     T1035
      SET     M5035  ; 4#挡载座2（报警）
532   LDI     M4036  ; 4#定载座2（输出）
      AND     M646  ; 4#定载座2气缸原点
      ANI     M846  ; 4#定载座2气缸终点
      LD      M4036  ; 4#定载座2（输出）
      ANI     M646  ; 4#定载座2气缸原点
      AND     M846  ; 4#定载座2气缸终点
      ORB
      INV
      OUT     T1036 K20
      AND     T1036
      SET     M5036  ; 4#定载座2（报警）
546   LDI     M4037  ; 4#定载座3（输出）
      AND     M647  ; 4#定载座3气缸原点
      ANI     M847  ; 4#定载座3气缸终点
      LD      M4037  ; 4#定载座3（输出）
      ANI     M647  ; 4#定载座3气缸原点
      AND     M847  ; 4#定载座3气缸终点
      ORB
      INV
      OUT     T1037 K20
      AND     T1037
      SET     M5037  ; 4#定载座3（报警）
560   LDI     M4038  ; 4#顶载座（输出）
      ANI     M648  ; 4#顶载座气缸原点
      OUT     T1038 K20
      AND     T1038
      SET     M5038  ; 4#顶载座（报警）
568   LDI     M4039  ; 4#夹产品（输出）
      AND     M649  ; 4#夹产品气缸原点
      ANI     M849  ; 4#夹产品气缸终点
      LD      M4039  ; 4#夹产品（输出）
      ANI     M649  ; 4#夹产品气缸原点
      AND     M849  ; 4#夹产品气缸终点
      ORB
      INV
      OUT     T1039 K20
      AND     T1039
      SET     M5039  ; 4#夹产品（报警）
582   LDI     M4040  ; 升降气缸（输出）
      AND     M650  ; 升降气缸原点
      ANI     M850  ; 升降气缸终点
      LD      M4040  ; 升降气缸（输出）
      ANI     M650  ; 升降气缸原点
      AND     M850  ; 升降气缸终点
      ORB
      INV
      OUT     T1040 K20
      AND     T1040
      SET     M5040  ; 升降气缸（报警）
596   LDI     M4041  ; 4#前挡载座1（输出）
      AND     M651  ; 4#前挡气缸1原点
      ANI     M851  ; 4#前挡气缸1终点
      LD      M4041  ; 4#前挡载座1（输出）
      ANI     M651  ; 4#前挡气缸1原点
      AND     M851  ; 4#前挡气缸1终点
      ORB
      INV
      OUT     T1041 K20
      AND     T1041
      SET     M5041  ; 4#前挡载座1（报警）
610   LDI     M4042  ; 1#前挡载座2（输出）
      AND     M652  ; 1#前挡气缸2原点
      ANI     M852  ; 1#前挡气缸2终点
      LD      M4042  ; 1#前挡载座2（输出）
      ANI     M652  ; 1#前挡气缸2原点
      AND     M852  ; 1#前挡气缸2终点
      ORB
      INV
      OUT     T1042 K20
      AND     T1042
      SET     M5042  ; 1#前挡载座2（报警）
624   LDI     M4043  ; 4#前挡载座2（输出）
      AND     M653  ; 4#前挡气缸2原点
      ANI     M853  ; 4#前挡气缸2终点
      LD      M4043  ; 4#前挡载座2（输出）
      ANI     M653  ; 4#前挡气缸2原点
      AND     M853  ; 4#前挡气缸2终点
      ORB
      INV
      OUT     T1043 K20
      AND     T1043
      SET     M5043  ; 4#前挡载座2（报警）
638   LD      M5045  ; 2#吸料异常
      ANDP    M1  ; 报警清除
      MOV     K0 D200  ; 2#吸料次数计数
642   LD      M5046  ; 3#吸料异常
      ANDP    M1  ; 报警清除
      MOV     K0 D210  ; 3#吸料次数计数
646   LD>=    D970 D980  ; AOI测试NG数量（生产） / AOI测试NG数量（设定）
      MPS
      ANI     SM400
      OUT     M5101
      MPP
      AND     M5101
      ANDP    M1  ; 报警清除
      MOV     K0 D970
657   LD>=    D972 D982  ; 开路NG数量（生产） / 开路NG数量（设定）
      MPS
      ANI     SM400
      OUT     M5102
      MPP
      AND     M5102
      ANDP    M1  ; 报警清除
      MOV     K0 D972
668   LD>=    D974 D984  ; 短路NG数量（生产） / 短路NG数量（设定）
      MPS
      ANI     SM400
      OUT     M5103
      MPP
      AND     M5103
      ANDP    M1  ; 报警清除
      MOV     K0 D974
679   LDI     M2532  ; 2#移载轴伺服报警
      ANI     M2542  ; 5#装产品轴伺服报警
      ANI     M2552  ; 6#AOI产品测试轴报警
      ANI     M2562  ; 3#移载轴伺服报警
      ANI     M2572  ; 点胶B面伺服报警
      ANI     M2582  ; 3#装产品轴伺服报警
      ANI     M2592  ; 4#移载座轴伺服报警
      ANI     M2902  ; 4#取产品轴伺服报警
      ANI     M2912  ; 4#入回流焊轴伺服报警
      INV
      OUT     M8  ; 伺服报警
690   LDD<>   K0 K4M5000  ; 下挡载座（报警）
      OR<>    K4M5016 K0  ; 2#吸产品（报警）
      OR<>    K0 K4M5032  ; 3#夹产品（报警）
      OR      M8  ; 伺服报警
      ANI     M1  ; 报警清除
      OUT     M0  ; 报警
703   LDI     B10F  ; 马达原点回归中（OFF有效）
      ANI     SM400
      OUT     T5 K150
709   LD      M1  ; 报警清除
      OR      M16  ; 停止（外部按钮）
      BKRST   M5000 K200
      RST     M8  ; 伺服报警
715   END
END_PROGRAM

PROGRAM 输出1
VAR
  KD910 : DINT;
END_VAR
0     LD      M4000  ; 下挡载座（输出）
      OUT     Y200  ; 下挡载座输出
2     LD      M4001  ; 卸载座（输出）
      OUT     Y201  ; 卸载座输出
4     LD      M4002  ; 载座升降（输出）
      OUT     Y202  ; 载座升降输出
6     LDI     M4511  ; 2#卷下带马达开关（ON为关）
      AND     M17  ; 急停（外部按钮）
      OUT     Y203  ; 2#卷下带马达
9     LD      M4004  ; 1#挡载座（输出）
      OUT     Y204  ; 1#挡载座输出
11    LD      M4005  ; 1#定载座1（输出）
      OUT     Y205  ; 1#定载座1输出
13    LD      M4006  ; 1#定载座2（输出）
      OUT     Y206  ; 1#定载座2输出
15    LD      M4007  ; 2#前挡载座1（输出）
      OUT     Y207  ; 2#前挡载座1输出
17    LD      M4008  ; 2#前挡载座2（输出）
      OUT     Y208  ; 2#前挡载座2输出
19    LD      M4009  ; 2#挡载座（输出）
      OUT     Y209  ; 2#挡载座输出
21    LDI     M3  ; 流水线开关（ON为关）
      AND     M17  ; 急停（外部按钮）
      OUT     Y218  ; 流水线马达控制输出
24    LDI     M9  ; 总气阀开关（ON为关）
      AND     M17  ; 急停（外部按钮）
      OUT     Y219  ; 总气阀输出
27    LD      M4010  ; 2#定载座1（输出）
      OUT     Y20A  ; 2#定载座1输出
29    LD      M4011  ; 2#定载座2（输出）
      OUT     Y20B  ; 2#定载座2输出
31    LD      M4012  ; 2#压产品（输出）
      OUT     Y20C  ; 2#压产品输出
33    LD      M4013  ; 2#压载带1（输出）
      OUT     Y20D  ; 2#压载带1输出
35    LDI     M4510  ; 2#卷上带马达开关（ON为关）
      AND     M17  ; 急停（外部按钮）
      OUT     Y20E  ; 2#卷上带马达
38    LDI     M23  ; 启动
      ANDP    M3013  ; 2#压载带1(手动)
      LDI     M23  ; 启动
      ANDP    M3014  ; 2#压载带2(手动)
      ORB
      FF      M4013
      FF      M4014  ; 2#压载带2（输出）
47    LD      M4015  ; 2#取产品上下输出
      OUT     Y20F  ; 2#取产品上下输出
49    LD      M4016  ; 2#吸产品（输出）
      OUT     Y210  ; 2#吸产品输出
51    LD      M4017  ; 2#推产品（输出）
      OUT     Y211  ; 2#推产品输出
53    LD      M4018  ; 2#挡产品（输出）
      OUT     Y212  ; 2#挡产品输出
55    LD      M4019  ; 2#夹产品（输出）
      OUT     Y213  ; 2#夹产品输出
57    LD      M4020  ; 3#前挡载座1（输出）
      OUT     Y21B  ; 3#前挡载座1输出
59    LD      M4021  ; 3#前挡载座2（输出）
      OUT     Y21C  ; 3#前挡载座2输出
61    LD      M4022  ; 3#挡载座（输出）
      OUT     Y222  ; 3#挡载座输出
63    LD      M4023  ; 3#定载座1（输出）
      OUT     Y223  ; 3#定载座1输出
65    LD      M4024  ; 3#定载座2（输出）
      OUT     Y224  ; 3#定载座2输出
67    LD      M4025  ; 3#压产品（输出）
      OUT     Y225  ; 3#压产品输出
69    LDI     M23  ; 启动
      ANDP    M3026  ; 3#压载带1(手动)
      LDI     M23  ; 启动
      ANDP    M3027  ; 3#压载带2(手动)
      ORB
      FF      M4026  ; 3#压载带1（输出）
      FF      M4027  ; 3#压载带2（输出）
78    LD      M4026  ; 3#压载带1（输出）
      OUT     Y226  ; 3#压载带1输出
80    LD      M4027  ; 3#压载带2（输出）
      OUT     Y227  ; 3#压载带2输出
82    LD      M4028  ; 3#取产品上下（输出）
      OUT     Y228  ; 3#取产品上下输出
84    LD      M4029  ; 3#吸产品（输出）
      OUT     Y229  ; 3#吸产品输出
86    LD      M4030  ; 3#推产品（输出）
      OUT     Y22A  ; 3#推产品输出
88    LD      M4031  ; 3#挡产品（输出）
      OUT     Y22B  ; 3#挡产品输出
90    LD      M4032  ; 3#夹产品（输出）
      OUT     Y22C  ; 3#夹产品输出
92    LD      M4033  ; 4#挡载座1（输出）
      OUT     Y22D  ; 4#挡载座1输出
94    LD      M4034  ; 4#定载座1（输出）
      OUT     Y22E  ; 4#定载座1输出
96    LD      M4035  ; 4#挡载座2（输出）
      OUT     Y22F  ; 4#挡载座2输出
98    LD      M4036  ; 4#定载座2（输出）
      OUT     Y230  ; 4#定载座2输出
100   LD      M4037  ; 4#定载座3（输出）
      OUT     Y231  ; 4#定载座3输出
102   LD      M4038  ; 4#顶载座（输出）
      OUT     Y232  ; 4#顶载座输出
104   LD      M4039  ; 4#夹产品（输出）
      OUT     Y233  ; 4#夹产品输出
106   LD      M4040  ; 升降气缸（输出）
      OUT     Y234  ; 升降气缸输出
108   LD      M4060  ; 降载座工位卸载座
      OUT     Y237
110   LDI     M4512  ; 3#卷上带马达开关（ON为关）
      AND     M17  ; 急停（外部按钮）
      OUT     Y238  ; 3#卷上带马达
113   LDI     M4513  ; 3#卷下带马达开关（ON为关）
      AND     M17  ; 急停（外部按钮）
      OUT     Y239  ; 3#卷下带马达
116   LD      M4041  ; 4#前挡载座1（输出）
      OUT     Y235  ; 4#前挡载座2输出
118   LD      M4042  ; 1#前挡载座2（输出）
      OUT     Y21A  ; 1#前挡载座2输出
120   LD      M4043  ; 4#前挡载座2（输出）
      OUT     Y236
122   LD      M23  ; 启动
      ANI     M24  ; 停止
      OR      M22  ; 自动状态
      ANI     M20  ; 手动状态
      ANI     M0  ; 报警
      ANI     M161
      OUT     Y216  ; 绿灯
129   LDI     M23  ; 启动
      AND     M24  ; 停止
      OR      M20  ; 手动状态
      OR      M21  ; 单动状态
      ANI     M22  ; 自动状态
      ANI     M0  ; 报警
      OUT     Y215  ; 黄灯
136   LD      M0  ; 报警
      OR      M161
      OUT     T1 K20
      MPS
      AND     SM411
      ANI     T1
      OUT     Y217  ; 蜂鸣器
      MPP
      OUT     Y214  ; 红灯
148   LD      M2
      MOV     T0 D304
151   LD      M23  ; 启动
      ANI     M2
      OUTH    T0 K9999
157   LD      M5  ; 产能清除
      OUT     T2 K5
      AND     T2
      MOV     K0 D302  ; 当前产能
165   END
END_PROGRAM

PROGRAM 降载座工位
VAR
  XX37 : BOOL;
END_VAR
0     LD      X3C  ; 轴1 busy
      ANI     M2007
      OR      M2007
      AND=    K0 K3B271  ; 工位2插模组第一步
      AND     X39  ; 轴2出错
      AND     X36  ; 轴3M代码on
      OUT     T236 K5
12    LDI     X3C  ; 轴1 busy
      ANI     M2007
      OR      M2007
      ANI     M4074
      AND     X39  ; 轴2出错
      AND     B270  ; 工位2插模组启动
      ANI     SM400
      SET     M4075
20    LD      X3C  ; 轴1 busy
      OUT     T237 K5
25    LD      T237
      OR<>    K0 K3B271  ; 工位2插模组第一步
      ANI     SM400
      RST     M4075
31    LD      B270  ; 工位2插模组启动
      AND     M23  ; 启动
      ANI     M24  ; 停止
      ANI     SM400
      AND     T236
      SET     B271  ; 工位2插模组第一步
      RST     B270  ; 工位2插模组启动
38    LDI     SM400
      AND     B271  ; 工位2插模组第一步
      MPS
      AND     X39  ; 轴2出错
      SET     M4074
      MRD
      AND     M4074
      AND     X38  ; 轴1出错
      OUT     T600 D3054
      MPP
      AND     T600
      SET     B272  ; 工位2插模组第二步
      RST     B271  ; 工位2插模组第一步
54    LDI     SM400
      AND     B272  ; 工位2插模组第二步
      MPS
      AND     X38  ; 轴1出错
      AND     X36  ; 轴3M代码on
      SET     M4076
      MRD
      AND     M4076
      AND     X37  ; 轴4M代码on
      OUT     T601 D3055
      MPP
      AND     T601
      SET     B273  ; 工位2插模组第三步
      RST     B272  ; 工位2插模组第二步
71    LDI     SM400
      AND     B273  ; 工位2插模组第三步
      RST     M4076
      MPS
      ANI     M4076
      AND     X36  ; 轴3M代码on
      OUT     T610 D3056
      MPP
      AND     T610
      SET     B274  ; 工位2插模组第四步
      RST     B273  ; 工位2插模组第三步
85    LDI     SM400
      AND     B274  ; 工位2插模组第四步
      RST     M4074
      MPS
      ANI     M4074
      AND     X39  ; 轴2出错
      OUT     T611 D3057
      MPP
      AND     T611
      SET     B270  ; 工位2插模组启动
      MPS
      AND     M21  ; 单动状态
      PLS     M88  ; 工位4单动停止
      MPP
      RST     B274  ; 工位2插模组第四步
104   END
END_PROGRAM

PROGRAM 马达初始化
0     LD      M17  ; 急停（外部按钮）
      AND     SM400
      MPS
      ANI     M2080  ; 5#伺服ON
      OUT     Y21E
      INV
      OUT     M2540
      MRD
      ANI     M2100  ; 6#伺服ON
      OUT     Y21F
      INV
      OUT     M2550
      MRD
      ANI     M2000  ; 1#伺服ON
      INV
      OUT     M2500  ; 1#伺服ON
      MRD
      ANI     M2020  ; 2#伺服ON
      INV
      OUT     M2510  ; 2#伺服ON
      MRD
      ANI     M2040  ; 3#伺服ON
      OUT     M2520  ; 伺服ON状态
      MRD
      ANI     M2060  ; 4#伺服ON
      OUT     Y21D
      INV
      OUT     M2530  ; 伺服ON状态
      MRD
      ANI     M2120  ; 7#伺服ON
      OUT     Y240
      INV
      OUT     M2560
      MRD
      ANI     M2140  ; 8#伺服ON
      OUT     Y241
      INV
      OUT     M2570
      MRD
      ANI     M2160  ; 9#伺服ON
      OUT     Y242
      INV
      OUT     M2580
      MRD
      ANI     M2180  ; 10#伺服ON
      OUT     Y243
      INV
      OUT     M2590
      MPP
      OUT     Y10  ; LD75P4-CM
      OUT     Y30  ; 2#LD75P4-CM
      OUT     Y60
52    LD      M17  ; 急停（外部按钮）
      AND     SM400
      MPS
      ANI     M2200
      MPS
      INV
      OUT     M2900
      MPP
      OUT     Y244
      MPP
      ANI     M2220
      MPS
      INV
      OUT     M2910
      MPP
      OUT     Y245
68    LD      SM403
      ANI     M17  ; 急停（外部按钮）
      ?OP6542
      ?OP6543
      OUT     Y14  ; 轴1停止
      OUT     Y15  ; 轴2停止
      OUT     Y16  ; 轴3停止
      OUT     Y17  ; 轴4停止
      OUT     Y34  ; 2#轴1停止
      OUT     Y35  ; 2#轴2停止
      OUT     Y36  ; 2#轴3停止
      OUT     Y37  ; 2#轴4停止
      OUT     Y64
      OUT     Y65
      RST     M4100  ; 2#手动拉料
      RST     M4200  ; 3#手动拉料
84    LD      SM400
      DMOV    SD1840 D1000  ; 1#当前值
      DMOV    SD1860 D1020  ; 2#当前
      DMOV    U1\G800 D1040  ; 3#当前值
      DMOV    U1\G900 D1060  ; 4#当前值
      DMOV    U1\G1000 D1080  ; 5#当前值
      DMOV    U1\G1100 D1100  ; 6#当前值
      MOV     SD1845 D1014  ; 1#出错
      MOV     SD1865 D1034  ; 2#轴出错码
      MOV     U1\G806 D1054  ; 3#轴出错码
      MOV     U1\G906 D1074  ; 4#轴出错码
      MOV     U1\G1006 D1094  ; 5#轴出错码
      MOV     U1\G1106 D1114  ; 6#轴出错码
125   LD      SM400
      MOV     SD1846 D1016  ; 1#轴有效M码
      MOV     SD1866 D1036  ; 2#有效M码
      MOV     U1\G808 D1056  ; 3#有效M码
      MOV     U1\G908 D1076  ; 4#有效M码
      MOV     U1\G1008 D1096  ; 5#有效M码
      MOV     U1\G1108 D1116  ; 6#有效M码
146   LD      SM400
      DMOV    U3\G800 D1120  ; 7#当前值
      DMOV    U3\G900 D1140  ; 8#当前值
      DMOV    U3\G1000 D1160  ; 9#当前值
      DMOV    U3\G1100 D1180  ; 10#当前值
      DMOV    U6\G800 D1200
      DMOV    U6\G900 D1240
      MOV     U3\G806 D1134  ; 7#轴出错码
      MOV     U3\G906 D1154  ; 8#轴出错码
      MOV     U3\G1006 D1174  ; 9#轴出错码
      MOV     U3\G1106 D1194  ; 10#轴出错码
      MOV     U6\G806 D1214
      MOV     U6\G906 D1254
      MOV     U3\G808 D1136  ; 7#有效M码
      MOV     U3\G908 D1156  ; 8#有效M码
      MOV     U3\G1008 D1176  ; 9#有效M码
      MOV     U3\G1108 D1196  ; 10#有效M码
      MOV     U6\G808 D1216
      MOV     U6\G908 D1256
219   LD      SM400
      AND     M17  ; 急停（外部按钮）
      OUT     T100 K10
      OUT     T110 K10
      OUT     T120 K10
      OUT     T130 K10
      OUT     T140 K10
      OUT     T150 K10
      OUT     T160 K10
      OUT     T170 K10
      OUT     T180 K10
      OUT     T190 K10
      OUT     T200 K10
      OUT     T210 K10
      OUT     T220 K10
      OUT     T230 K10
      OUT     T240 K10
      OUT     T250 K10
      OUT     T260 K10
      OUT     T270 K10
      OUT     T280 K10
      OUT     T290 K10
      OUT     T300 K10
305   LD      X14  ; 轴1M代码on
      MOV     K1 U1\G1504
310   LD      X15  ; 轴2M代码on
      MOV     K1 U1\G1604
315   LD      X16  ; 轴3M代码on
      MOV     K1 U1\G1704
320   LD      X17  ; 轴4M代码on
      MOV     K1 U1\G1804
325   LD      X34  ; 轴1M代码on
      MOV     K1 U3\G1504
330   LD      X35  ; 轴2M代码on
      MOV     K1 U3\G1604
335   LD      X36  ; 轴3M代码on
      MOV     K1 U3\G1704
340   LD      X37  ; 轴4M代码on
      MOV     K1 U3\G1804
345   LD      X64
      MOV     K1 U6\G1504
350   LD      X65
      MOV     K1 U6\G1604
355   LD      M1  ; 报警清除
      OR      M16  ; 停止（外部按钮）
      OUT     SM1850
      OUT     SM1870
      MOV     K1 U1\G1502
      MOV     K1 U1\G1602
      MOV     K1 U1\G1702
      MOV     K1 U1\G1802
      MOV     K1 U3\G1502
      MOV     K1 U3\G1602
      MOV     K1 U3\G1702
      MOV     K1 U3\G1802
      MOV     K1 U6\G1502
      MOV     K1 U6\G1602
399   LDI     X129  ; 2#出载带移载轴伺服报警
      OUT     M2542  ; 5#装产品轴伺服报警
401   LDI     X12A  ; 2#装产品轴伺服报警
      OUT     M2552  ; 6#AOI产品测试轴报警
403   LDI     X193
      ANI     SM400
      OUT     M2502  ; 1#测试移位轴伺服报警
406   LDI     X194
      ANI     SM400
      OUT     M2512  ; 2#排不良轴伺服报警
409   LDI     X1BC
      ANI     SM400
      OUT     M2522  ; 点胶A面伺服报警
412   LDI     X128  ; 2#移载轴伺服报警
      OUT     M2532  ; 2#移载轴伺服报警
414   LDI     X16A  ; 3#移载轴伺服报警
      OUT     M2562  ; 3#移载轴伺服报警
416   LDI     X16B  ; 3#出载带移载轴伺服报警
      OUT     M2572  ; 点胶B面伺服报警
418   LDI     X16C  ; 3#装产品轴伺服报警
      OUT     M2582  ; 3#装产品轴伺服报警
420   LDI     X16D  ; 4#移载座轴报警
      OUT     M2592  ; 4#移载座轴伺服报警
422   LDI     X16E  ; 4#取产品轴报警
      OUT     M2902  ; 4#取产品轴伺服报警
424   LDI     X16F  ; 4#入回流焊轴报警
      OUT     M2912  ; 4#入回流焊轴伺服报警
426   LD<>    D1014 K0  ; 1#出错
      OR      X0C  ; 一般输入
      OUT     M2503
431   LD<>    D1034 K0  ; 2#轴出错码
      OR      X0D  ; 一般输入
      OUT     M2513
436   LD<>    D1054 K0  ; 3#轴出错码
      OUT     M2523
440   LD<>    D1074 K0  ; 4#轴出错码
      OUT     M2533
444   LD<>    D1094 K0  ; 5#轴出错码
      OUT     M2543
448   LD<>    D1114 K0  ; 6#轴出错码
      OUT     M2553
452   LD<>    D1134 K0  ; 7#轴出错码
      OUT     M2563
456   LD<>    D1154 K0  ; 8#轴出错码
      OUT     M2573
460   LD<>    D1174 K0  ; 9#轴出错码
      OUT     M2583
464   LD<>    D1194 K0  ; 10#轴出错码
      OUT     M2593
468   LD<>    D1214 K0
      OUT     M2903
472   LD<>    D1254 K0
      OUT     M2913
476   LD      M20  ; 手动状态
      MOVP    K0 D1455
      MOVP    K0 D1475
      MOVP    K0 D1495
      MOVP    K0 D1515
      MOVP    K0 D1535
      MOVP    K0 D1555
      MOVP    K0 D1575
      MOVP    K0 D1595
      MOVP    K0 D1235
      MOVP    K0 D1275
497   LD      M20  ; 手动状态
      MOVP    D1455 U1\G1517
      MOVP    D1475 U1\G1617
      MOVP    D1495 U1\G1717
      MOVP    D1515 U1\G1817
      MOVP    D1535 U3\G1517
      MOVP    D1555 U3\G1617
      MOVP    D1575 U3\G1717
      MOVP    D1595 U3\G1817
      MOVP    D1235 U6\G1517
      MOVP    D1275 U6\G1617
538   LD      M20  ; 手动状态
      DMOV    D1456 U1\G1518
      DMOV    D1476 U1\G1618
      DMOV    D1496 U1\G1718
      DMOV    D1516 U1\G1818
      DMOV    D1536 U3\G1518
      DMOV    D1556 U3\G1618
      DMOV    D1576 U3\G1718
      DMOV    D1596 U3\G1818
      DMOV    D1236 U6\G1518
      DMOV    D1276 U6\G1618
579   END
END_PROGRAM

// device comments not shown above
X0  ; 高速计数器A相
X1  ; 高速计数器B相
X2  ; 高速计数器A相
X3  ; 高速计数器B相
X5  ; 急停
X6  ; 启动
X7  ; 停止
X0A  ; 轴1 近点DOG信号
X0B  ; 轴2 近点DOG信号
X10  ; LD75P4-CM
X18  ; 轴1出错
X19  ; 轴2出错
X1A  ; 轴3出错
X1B  ; 轴4出错
X20  ; 轴1启动完成
X21  ; 轴2启动完成
X22  ; 轴3启动完成
X23  ; 轴4启动完成
X24  ; 轴1定位完成
X25  ; 轴2定位完成
X26  ; 轴3定位完成
X27  ; 轴4定位完成
X30  ; LD75P4-CM
X3A  ; 轴3出错
X3B  ; 轴4出错
X40  ; 轴1启动完成
X41  ; 轴2启动完成
X42  ; 轴3启动完成
X43  ; 轴4启动完成
X44  ; 轴1定位完成
X45  ; 轴2定位完成
X46  ; 轴3定位完成
X47  ; 轴4定位完成
X137  ; 脚踏启动（工位1）
X140  ; 3#前挡载座1原点
X141  ; 3#前挡载座1终点
X142  ; 3#前挡载座2原点
X143  ; 3#前挡载座2终点
X171  ; 4#挡载座2到位感应
Y0  ; 急停断气
Y2  ; 伺服ON
Y3  ; 报警清除
Y4  ; 轴1 CW/PULSE/A相输出
Y5  ; 伺服脉冲
Y6  ; 轴1 CCW/SIGN/B相输出
Y7  ; 伺服方向
Y100  ; 挡载座1
Y101  ; 挡载座2
Y102  ; 定载座
Y103  ; 刹载座
Y104  ; 卸载座
Y105  ; 载座升降
Y106  ; 压带1
Y107  ; 压带2
Y108  ; 吸盘上下
Y109  ; 排NG
Y10A  ; 排NG分类
Y10B  ; 破真空
Y10E  ; 1#顶料盘
Y10F  ; 2#顶料盘
Y110  ; 下压轮一
Y111  ; 下压轮二
Y112  ; 下压轮三
Y113  ; 下压轮四
Y114  ; 断电气
Y115  ; 轴1报警清除
Y116  ; 轴1伺服ON
Y117  ; 轴2报警清除
Y118  ; 轴2伺服ON
Y119  ; 轴3报警清除
Y11A  ; 轴3伺服ON
Y11B  ; 轴4报警清除
Y11C  ; 轴4伺服ON
Y124  ; 蜂鸣器
Y125  ; 绿
Y126  ; 红
Y127  ; 黄
Y12A  ; 收料1
M19  ; 气阀
M30  ; 排不良马达移动条件
M51  ; 3#送料步进上电回原点用
M52  ; 备用轴上电回原点用
M53  ; 2#送料步进上电回原点用
M89  ; 降载座单动停止
M105  ; 工位3与4前挡料互锁
M106  ; 工位5互锁
M107  ; 工位6前挡料互锁
M108  ; 工位6互锁
M109  ; 工位7前挡料互所
M671  ; 4#前挡载座满料感应
M1006  ; 3#送载带位置7（手动）
M1036  ; 3#送载带位置7（手动）
M1066  ; 3#送载带位置7（自动）
M1310  ; 4#  2#移载座轴位置11（手动）
M1311  ; 4#  2#移载座轴位置12（手动）
M1312  ; 4#  2#移载座轴位置13（手动）
M1340  ; 4#  2#移载座轴位置11（手动）
M1341  ; 4#  2#移载座轴位置12（手动）
M1342  ; 4#  2#移载座轴位置13（手动）
M1370  ; 4#  2#移载座轴位置11（自动）
M1371  ; 4#  2#移载座轴位置12（自动）
M1372  ; 4#  2#移载座轴位置13（自动）
M1406  ; 5#  2#出载带移载位置7（手动）
M1436  ; 5#  2#出载带移载位置7（手动）
M1466  ; 5#  2#出载带移载位置7（自动）
M1506  ; 6#  2#位置7
M1508  ; 6# 2# 位置9
M1512  ; 6#  2#位置13
M1514  ; 6#  2#位置15
M1515  ; 6# 2# 位置16
M1517  ; 6# 2# 位置18
M1519  ; 6#  2#位置20
M1536  ; 6#  2#位置7
M1538  ; 6#  2#位置9
M1542  ; 6#  2# 位置13
M1544  ; 6#  2# 位置15
M1545  ; 6#  2#位置16
M1547  ; 6#  2#位置18
M1549  ; 6#  2# 位置20
M1566  ; 6#   2#位置7
M1568  ; 6#  2#位置9
M1572  ; 6#  2#位置13
M1574  ; 6#  2#位置15
M1575  ; 6#  2#位置16
M1577  ; 6#  2#位置18
M1579  ; 6#  2#位置20
M1616  ; 7#  3#位置17
M1617  ; 7#  3#位置18
M1618  ; 7#  3#位置19
M1619  ; 7#  3#位置20
M1676  ; 7#  3#位置17
M1677  ; 7#  3#位置18
M1678  ; 7#  3#位置19
M1679  ; 7#  3#位置20
M1706  ; 8#   3#位置7（手动）
M1707  ; 8#   3#位置8（手动）
M1708  ; 8#   3#位置9（手动）
M1709  ; 8#   3#位置10（手动）
M1710  ; 8#   3#位置11（手动）
M1711  ; 8#   3#位置12（手动）
M1712  ; 8#   3#位置13（手动）
M1713  ; 8#   3#位置14（手动）
M1714  ; 8#   3#位置15（手动）
M1715  ; 8#   3#位置16（手动）
M1716  ; 8#   3#位置17（手动）
M1717  ; 8#   3#位置18（手动）
M1718  ; 8#   3#位置19（手动）
M1719  ; 8#   3#位置20（手动）
M1736  ; 8#  3#位置7（手动）
M1737  ; 8#  3#位置8（手动）
M1738  ; 8#  3#位置9（手动）
M1739  ; 8#  3#位置10（手动）
M1740  ; 8#  3#位置11（手动）
M1741  ; 8#  3#位置12（手动）
M1742  ; 8#  3#位置13（手动）
M1743  ; 8#  3#位置14（手动）
M1744  ; 8#  3#位置15（手动）
M1745  ; 8#  3#位置16（手动）
M1746  ; 8#  3#位置17（手动）
M1747  ; 8#  3#位置18（手动）
M1748  ; 8#  3#位置19（手动）
M1749  ; 8#  3#位置20（手动）
M1766  ; 8#  3#位置7（自动）
M1767  ; 8#  3#位置8（自动）
M1768  ; 8#  3#位置9（自动）
M1769  ; 8#  3#位置10（自动）
M1770  ; 8#  3#位置11（自动）
M1771  ; 8#  3#位置12（自动）
M1772  ; 8#  3#位置13（自动）
M1773  ; 8#  3#位置14（自动）
M1774  ; 8#  3#位置15（自动）
M1775  ; 8#  3#位置16（自动）
M1776  ; 8#  3#位置17（自动）
M1777  ; 8#  3#位置18（自动）
M1778  ; 8#  3#位置19（自动）
M1779  ; 8#  3#位置20（自动）
M1806  ; 9#   3#装产品轴位置7（手动）
M1807  ; 9#   3#位置8（手动）
M1808  ; 9#   3#位置9（手动）
M1809  ; 9#   3#位置10（手动）
M1810  ; 9#   3#位置11（手动）
M1811  ; 9#   3#位置12（手动）
M1812  ; 9#   3#位置13（手动）
M1813  ; 9#   3#位置14（手动）
M1814  ; 9#   3#位置15（手动）
M1815  ; 9#   3#位置16（手动）
M1816  ; 9#   3#位置17（手动）
M1817  ; 9#   3#位置18（手动）
M1818  ; 9#   3#位置19（手动）
M1819  ; 9#   3#位置20（手动）
M1836  ; 9#   3#装产品轴位置7（手动）
M1837  ; 9#   3#位置8（手动）
M1838  ; 9#   3#位置9（手动）
M1839  ; 9#   3#位置10（手动）
M1840  ; 9#   3#位置11（手动）
M1841  ; 9#   3#位置12（手动）
M1842  ; 9#   3#位置13（手动）
M1843  ; 9#   3#位置14（手动）
M1844  ; 9#   3#位置15（手动）
M1845  ; 9#   3#位置16（手动）
M1846  ; 9#   3#位置17（手动）
M1847  ; 9#   3#位置18（手动）
M1848  ; 9#   3#位置19（手动）
M1849  ; 9#   3#位置20（手动）
M1866  ; 9#   3#装产品轴位置7（自动）
M1867  ; 9#   3#位置8
M1868  ; 9#   3#位置9
M1869  ; 9#   3#位置10
M1870  ; 9#   3#位置11
M1871  ; 9#   3#位置12
M1872  ; 9#   3#位置13
M1873  ; 9#   3#位置14
M1874  ; 9#   3#位置15
M1875  ; 9#   3#位置16
M1906  ; 10#  4#移载座轴位置7（手动）
M1907  ; 10#  4#位置8（手动）
M1908  ; 10#  4#位置9（手动）
M1909  ; 10#  4#位置10（手动）
M1910  ; 10#  4#位置11（手动）
M1911  ; 10#  4#位置12（手动）
M1912  ; 10#  4#位置13（手动）
M1913  ; 10#  4#位置14（手动）
M1914  ; 10#  4#位置15（手动）
M1915  ; 10#  4#位置16（手动）
M1916  ; 10#  4#位置17（手动）
M1917  ; 10#  4#位置18（手动）
M1918  ; 10#  4#位置19（手动）
M1919  ; 10#  4#位置20（手动）
M1937  ; 10#  4#位置8（手动）
M1938  ; 10#  4#位置9（手动）
M1939  ; 10#  4#位置10（手动）
M1940  ; 10#  4#位置11（手动）
M1941  ; 10#  4#位置12（手动）
M1942  ; 10#  4#位置13（手动）
M1943  ; 10#  4#位置14（手动）
M1944  ; 10#  4#位置15（手动）
M1945  ; 10#  4#位置16（手动）
M1946  ; 10#  4#位置17（手动）
M1947  ; 10#  4#位置18（手动）
M1948  ; 10#  4#位置19（手动）
M1949  ; 10#  4#位置20（手动）
M1967  ; 10#  4#位置8
M1968  ; 10#  4#位置9
M1969  ; 10#  4#位置10
M1970  ; 10#  4#位置11
M1971  ; 10#  4#位置12
M1972  ; 10#  4#位置13
M1973  ; 10#  4#位置14
M1974  ; 10#  4#位置15
M1975  ; 10#  4#位置16
M1976  ; 10#  4#位置17
M1977  ; 10#  4#位置18
M1978  ; 10#  4#位置19
M1979  ; 10#  4#位置20
M2406  ; 11#  4#位置7（手动）
M2407  ; 11#  4#位置8（手动）
M2408  ; 11#  4#位置9（手动）
M2409  ; 11#  4#位置10（手动）
M2410  ; 11#  4#位置11（手动）
M2411  ; 11#  4#位置12（手动）
M2412  ; 11#  4#位置13（手动）
M2413  ; 11#  4#位置14（手动）
M2414  ; 11#  4#位置15（手动）
M2415  ; 11#  4#位置16（手动）
M2416  ; 11#  4#位置17（手动）
M2417  ; 11#  4#位置18（手动）
M2418  ; 11#  4#位置19（手动）
M2419  ; 11#  4#位置20（手动）
M2436  ; 11#  4#位置7（手动）
M2437  ; 11#  4#位置8（手动）
M2438  ; 11#  4#位置9（手动）
M2439  ; 11#  4#位置10（手动）
M2440  ; 11#  4#位置11（手动）
M2441  ; 11#  4#位置12（手动）
M2442  ; 11#  4#位置13（手动）
M2443  ; 11#  4#位置14（手动）
M2444  ; 11#  4#位置15（手动）
M2445  ; 11#  4#位置16（手动）
M2446  ; 11#  4#位置17（手动）
M2447  ; 11#  4#位置18（手动）
M2448  ; 11#  4#位置19（手动）
M2449  ; 11#  4#位置20（手动）
M2466  ; 11#  4#位置7（自动）
M2467  ; 11#  4#位置8（自动）
M2468  ; 11#  4#位置9（自动）
M2470  ; 11#  4#位置11（自动）
M2471  ; 11#  4#位置12（自动）
M2472  ; 11#  4#位置13（自动）
M2473  ; 11#  4#位置14（自动）
M2474  ; 11#  4#位置15（自动）
M2475  ; 11#  4#位置16（自动）
M2476  ; 11#  4#位置17（自动）
M2477  ; 11#  4#位置18（自动）
M2478  ; 11#  4#位置19（自动）
M2479  ; 11#  4#位置20（自动）
M2626  ; 12#   4#入回流焊轴在位置6
M2746  ; 3#  2#送载带步进在位置6
M2747  ; 3#  2#送载带步进在位置7
M2748  ; 3#  2#送载带步进在位置8
M2866  ; 9#  3#装产品轴在位置6
M3500  ; 挡载座1
M3501  ; 挡载座2
M3502  ; 定载座
M3503  ; 刹载座
M3504  ; 卸载座
M3505  ; 载座升降
M3506  ; 压带1
M3507  ; 压带2
M3508  ; 吸盘上下
M3509  ; 排NG
M3510  ; 排NG分类
M3511  ; 1#下压轮
M3512  ; 2#下压轮
M3513  ; 1#顶料盘
M3514  ; 2#顶料盘
M3515  ; 破真空
M3542  ; 收料1
M4110  ; 3#手动拉料
M5044  ; 工位2产品感应异常报警
M6006  ; 12#  4#入回流焊轴位置7（手动）
M6007  ; 12#  4#入回流焊轴位置8（手动）
M6008  ; 12#  4#入回流焊轴位置9（手动）
M6009  ; 12#  4#入回流焊轴位置10（手动）
M6010  ; 12#  4#入回流焊轴位置11（手动）
M6011  ; 12#  4#入回流焊轴位置12（手动）
M6036  ; 12#  4#入回流焊轴位置7（手动）
M6037  ; 12#  4#入回流焊轴位置8（手动）
M6038  ; 12#  4#入回流焊轴位置9（手动）
M6039  ; 12#  4#入回流焊轴位置10（手动）
M6040  ; 12#  4#入回流焊轴位置11（手动）
M6041  ; 12#  4#入回流焊轴位置12（手动）
M6066  ; 12#  4#入回流焊轴位置7（自动）
M6067  ; 12#  4#入回流焊轴位置8（自动）
M6068  ; 12#  4#入回流焊轴位置9（自动）
M6069  ; 12#  4#入回流焊轴位置10（自动）
M6070  ; 12#  4#入回流焊轴位置11（自动）
M6071  ; 12#  4#入回流焊轴位置12（自动）
B12  ; 工位1复位第三步
B13  ; 工位1复位第四步
B14  ; 工位1复位第五步
B15  ; 工位1复位第六步
B16  ; 工位1复位第七步
B22  ; 工位2复位第三步
B23  ; 工位2复位第四步
B24  ; 工位2复位第五步
B25  ; 工位2复位第六步
B26  ; 工位2复位第七步
B32  ; 工位3复位第三步
B33  ; 工位3复位第四步
B34  ; 工位3复位第五步
B35  ; 工位3复位第六步
B36  ; 工位3复位第七步
B42  ; 工位4复位第三步
B43  ; 工位4复位第四步
B44  ; 工位4复位第五步
B45  ; 工位4复位第六步
B46  ; 工位4复位第七步
B52  ; 降载座复位第三步
B53  ; 降载座复位第四步
B54  ; 降载座复位第五步
B55  ; 降载座复位第六步
B56  ; 降载座复位第七步
B60  ; 工位6复位第一步
B61  ; 工位6复位第二步
B62  ; 工位6复位第三步
B63  ; 工位6复位第四步
B64  ; 工位6复位第五步
B65  ; 工位6复位第六步
B66  ; 工位6复位第七步
B70  ; 工位7复位第一步
B71  ; 工位7复位第二步
B72  ; 工位7复位第三步
B73  ; 工位7复位第四步
B74  ; 工位7复位第五步
B75  ; 工位7复位第六步
B76  ; 工位7复位第七步
B80  ; 工位9复位第一步
B81  ; 工位9复位第二步
B82  ; 工位9复位第三步
B83  ; 工位9复位第四步
B84  ; 工位9复位第五步
B85  ; 工位9复位第六步
B86  ; 工位9复位第七步
B90  ; 升载座工位复位第一步
B91  ; 升载座工位复位第二步
B92  ; 升载座工位复位第三步
B93  ; 升载座工位复位第四步
B94  ; 升载座工位复位第五步
B95  ; 升载座工位复位第六步
B102  ; 马达原点回归第三步
B103  ; 马达原点回归第四步
B104  ; 马达原点回归第五步
B105  ; 马达原点回归第六步
B106  ; 马达原点回归第七步
B11F  ; 2#回原中
B14F  ; +3#回原中
B15F  ; +4#回原中
B205  ; 升载座工位第五步
B206  ; 升载座工位第六步
B207  ; 升载座工位第七步
B208  ; 升载座工位第八步
B209  ; 升载座工位第九步
B20A  ; 升载座工位第十步
B20B  ; 升载座工位第十一步
B226  ; 工位1第六步
B227  ; 工位1第七步
B228  ; 工位1第八步
B229  ; 工位1第九步
B22A  ; 工位1第十步
B22B  ; 工位1第十一步
B24A  ; 工位2第十步
B24B  ; 工位2第十一步
B256  ; 工位2吸产品段第六步
B257  ; 工位2吸产品段第七步
B258  ; 工位2吸产品段第八步
B259  ; 工位2吸产品段第九步
B25A  ; 工位2吸产品段第十步
B25B  ; 工位2吸产品段第十一步
B265  ; 工位2放产品第五步
B266  ; 工位2放产品第六步
B267  ; 工位2放产品第七步
B268  ; 工位2放产品第八步
B269  ; 工位2放产品第九步
B26A  ; 工位2放产品第十步
B26B  ; 工位2放产品第十一步
B278  ; 工位2插模组第八步
B279  ; 工位2插模组第九步
B27A  ; 工位2插模组第十步
B27B  ; 工位2插模组第十一步
B34A  ; 工位3第十步
B34B  ; 工位3第十一步
B34F  ; 工位3完成标志
B356  ; 工位3吸产品段第六步
B357  ; 工位3吸产品段第七步
B358  ; 工位3吸产品段第八步
B359  ; 工位3吸产品段第九步
B35A  ; 工位3吸产品段第十步
B35B  ; 工位3吸产品段第十一步
B365  ; 工位3放产品第五步
B366  ; 工位3放产品第六步
B367  ; 工位3放产品第七步
B368  ; 工位3放产品第八步
B369  ; 工位3放产品第九步
B36A  ; 工位3放产品第十步
B36B  ; 工位3放产品第十一步
B378  ; 工位3插模组第八步
B379  ; 工位3插模组第九步
B37A  ; 工位3插模组第十步
B37B  ; 工位3插模组第十一步
B40D  ; 工位4第十三步
B40E  ; 工位4第十三步
B416  ; 工位4分段动作第七步
B417  ; 工位4分段动作第八步
B418  ; 工位4分段动作第九步
B425  ; 升载座工位第五步
B426  ; 升载座工位第六步
B427  ; 升载座工位第七步
B428  ; 升载座工位第八步
B1600  ; 、
D130  ; 点胶B面产品点胶次数计数
D306  ; 开路NG数
D308  ; 短路NG数
D614  ; CPU轴1当前值
D640  ; 工位4开路测试结果
D650  ; 工位4短路测试结果
D900  ; 总产量
D910  ; 设定产量
D1021  ; 2#轴出错码
D1023  ; +2#轴出错码
D1025  ; +4#轴出错码
D1031  ; 2#有效M码
D1033  ; +2#有效M码
D1035  ; +4#有效M码
D1402  ; 1#次数
D1404  ; 1#INC
D1422  ; 2#次数
D1424  ; 2#INC
D1444  ; +3#INC
D1454  ; +4#INC
D1504  ; 位置3
D2011  ; 加速时间
D2012  ; 减速时间
D2013  ; 停顿时间
D2014  ; 定位速度
D2016  ; 定位距离
D2018  ; 1#位置10
D2020  ; JOG速度
D2022  ; 加速时间
D2023  ; 减速时间
D2058  ; 2#位置10
D2060  ; 2#位置11
D2062  ; 2#位置12
D2102  ; 第一次点胶速度（A面）
D2104  ; 第二次点胶速度（A面）
D2140  ; 4#位置11
D2142  ; 4#位置12
D2144  ; 4#位置13
D2146  ; 4#位置14
D2148  ; 4#位置15
D2150  ; 4#位置16
D2152  ; 4#位置17
D2154  ; 4#位置18
D2156  ; 4#位置19
D2158  ; 4#位置20
D2188  ; 第一次点胶距离（A面）
D2190  ; 第二次点胶距离（A面）
D2308  ; 点胶B面产品第二点胶位
D3070  ; 开路产品不良盒测试
D3071  ; 短路产品不良盒测试
D4000  ; 点胶速度
D4010  ; 关胶位置
D4020  ; 关胶位置（实际）
D4100  ; A面第一次点胶提前关胶位（设定）
D4110  ; A面第一次点胶提前关胶位
D4120  ; A面第二次点胶提前关胶位（设定）
D4130  ; A面第二次点胶提前关胶位
